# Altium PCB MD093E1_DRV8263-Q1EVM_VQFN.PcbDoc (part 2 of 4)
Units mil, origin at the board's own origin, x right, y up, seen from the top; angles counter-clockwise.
Board outline 3224.41 x 4078.74 mil, 4 copper layers (Top Layer, Signal Layer 1, Signal Layer 2, Bottom Layer), stack 61.2 mil thick; 228 components, 126 nets, 641 pads, 753 vias.
Unrouted connection lines stored in the file: 76.

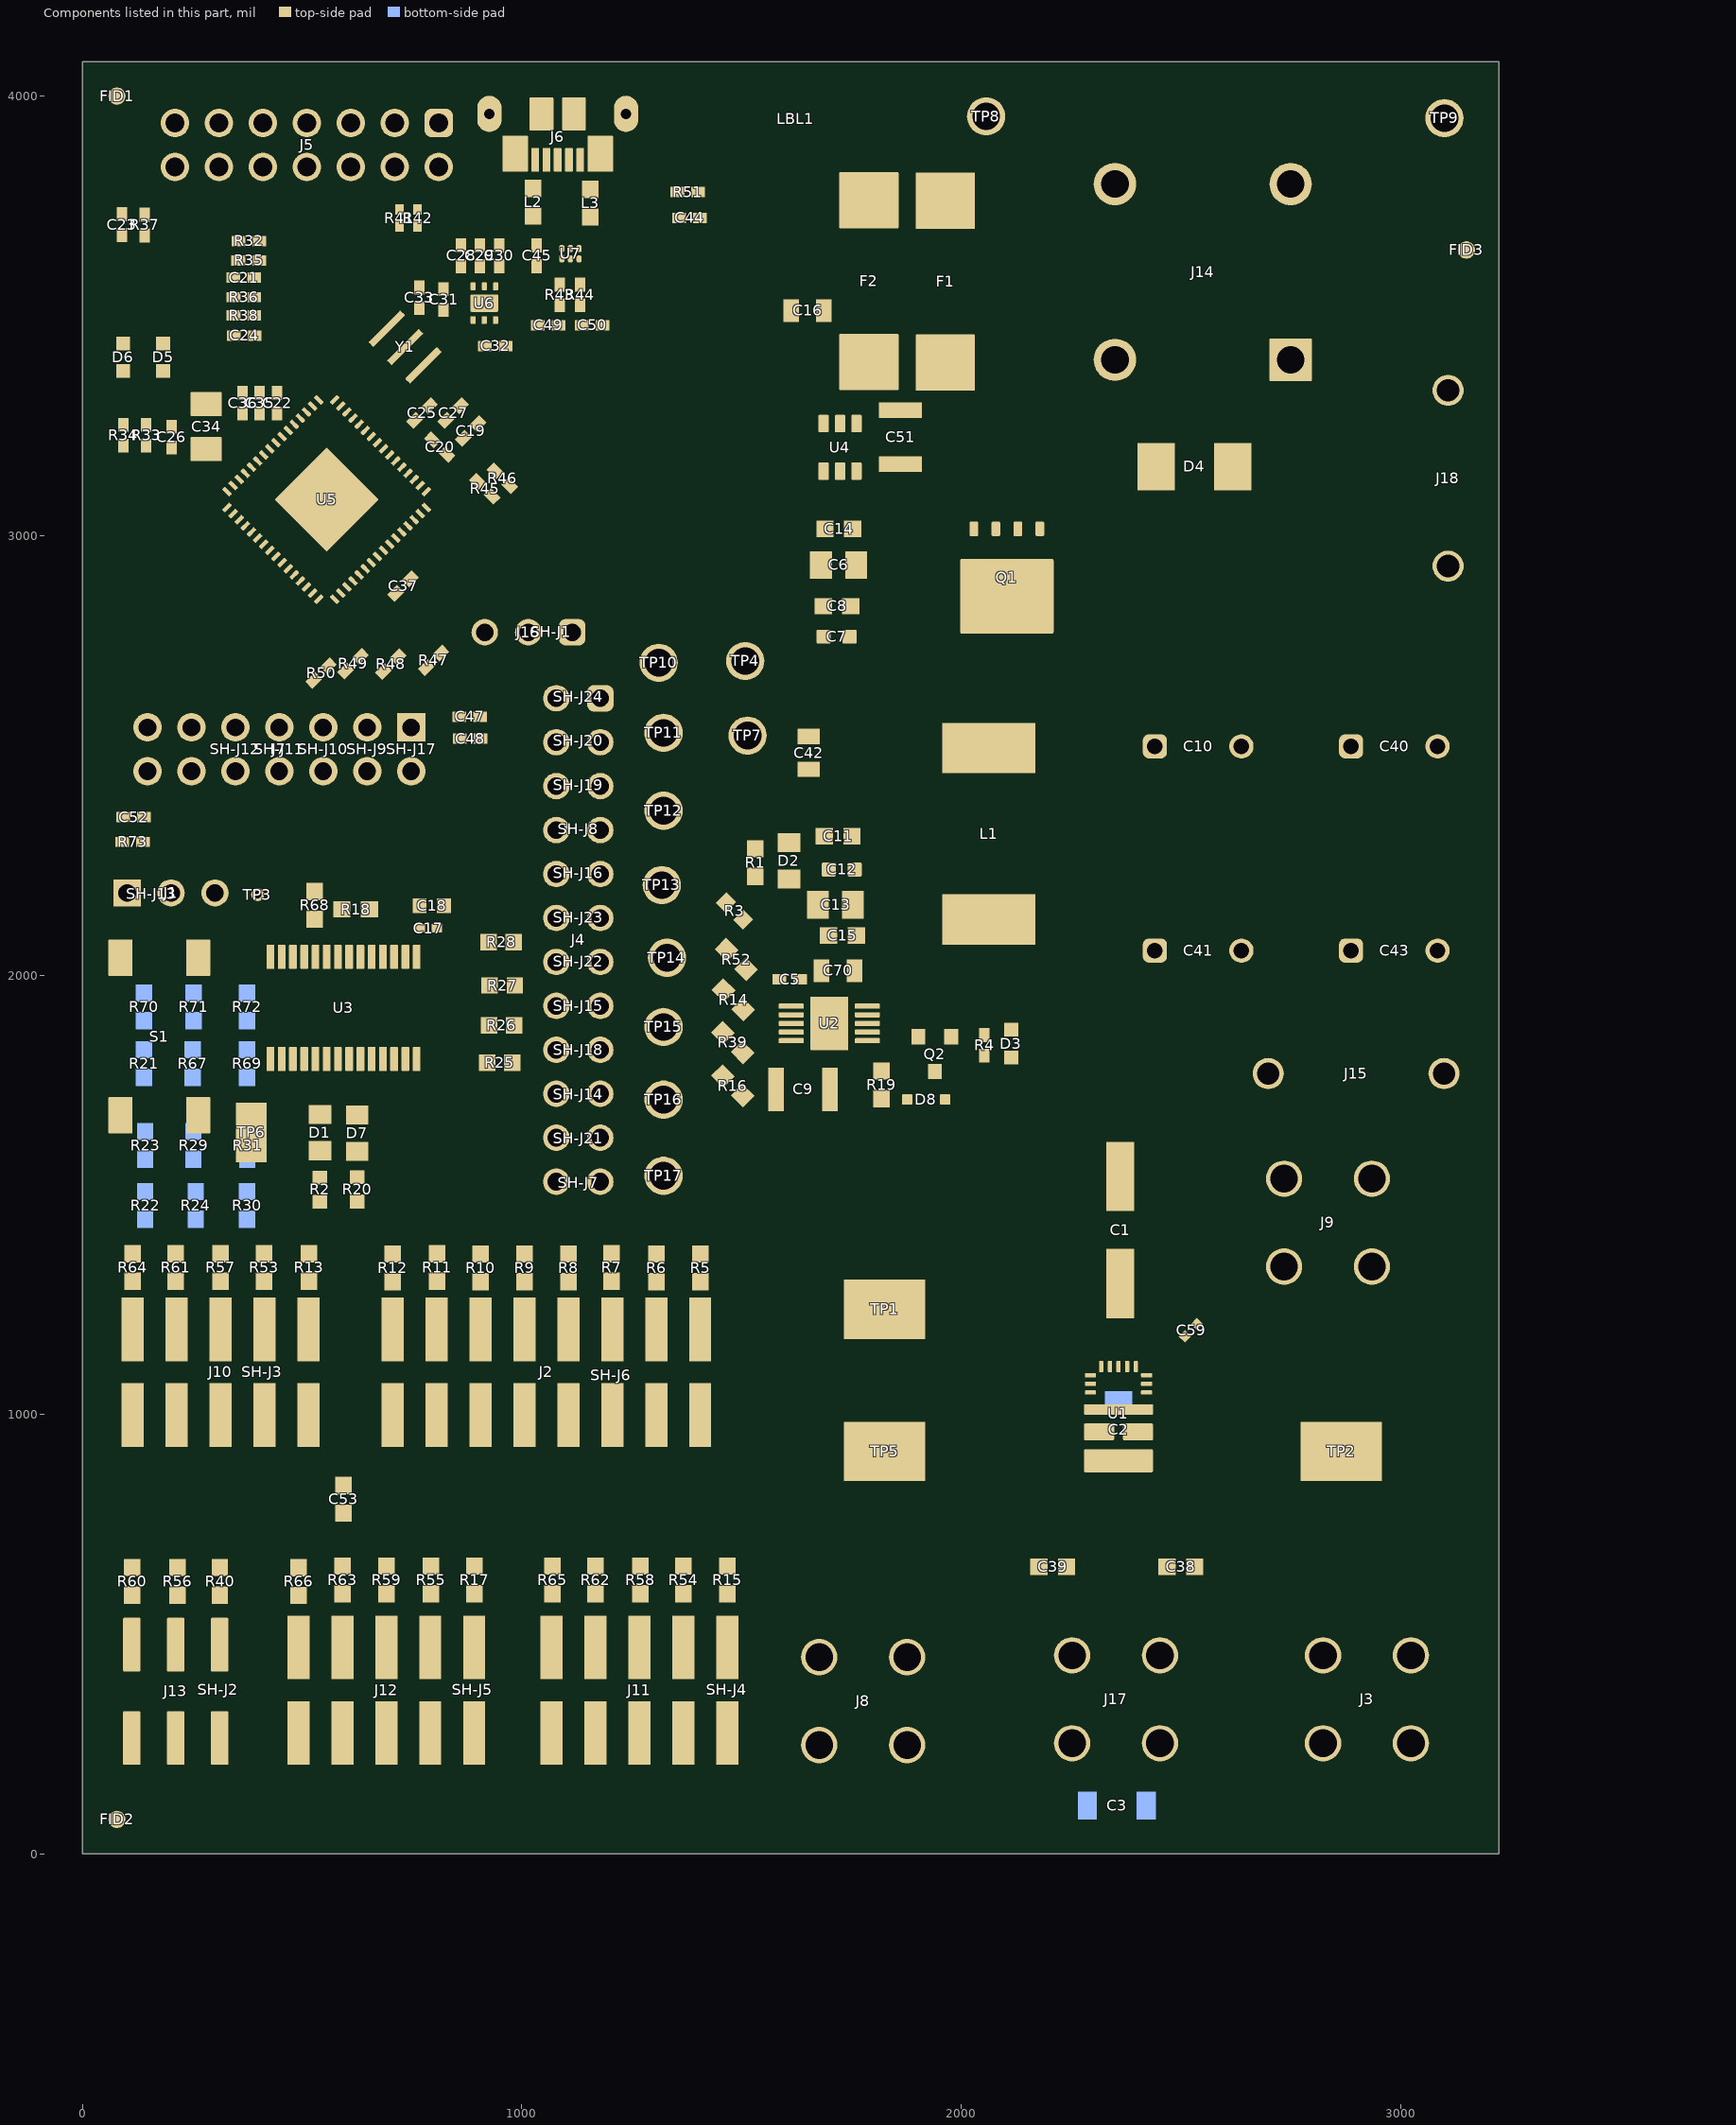
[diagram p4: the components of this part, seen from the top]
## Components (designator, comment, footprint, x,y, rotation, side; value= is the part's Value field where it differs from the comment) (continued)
C10 "860040875004" WCAP-ATUL_D10H20 2539.51,2520.41 r180 top
C11 "885012206114" 0603 1720.21,2315.81 r0 top value=0.01uF
C12 "885012206120" FP-885012206120_0603-MFG 1728.36,2240.08 r0 top value=100nF
C13 "C2012X7S2A105K125AB" 0805_HV 1713.9,2160.08 r0 top value=1uF
C14 "06031C102KAT2A" 0603 1721.82,3015.01 r180 top value=1000pF
C15 "06031C102KAT2A" 0603 1730,2090 r180 top value=1000pF
C16 "885012207124" WCAP-CSGP_0805_L2W1.25H0.8_Reflow 1650.4,3512 r180 top
C17 "Capacitor" 0402_065L 787.4,2106.3 r0 top value=4.7uF
C18 "885012206020" 0603L 795.28,2157.48 r0 top value=0.1uF
C19 "C1005X5R1A475M050BC" 0402 884.15,3238.01 r45 top value=4.7uF
C20 "GRM155R61A104KA01D" 0402 813.3,3201.7 r315 top value=0.1uF
C21 "C1005C0G1H330J050BA" 0402 367.6,3586.85 r180 top value=33pF
C22 "GRM155R61A104KA01D" 0402 443.31,3301.13 r90 top value=0.1uF
C23 "GRM155R71H102KA01D" 0402 90,3707.62 r270 top value=1000pF
C24 "C1005C0G1H330J050BA" 0402 368.6,3454.9 r180 top value=33pF
C25 "GRM155R61A224KE19D" 0402 773.36,3279.06 r45 top value=0.22uF
C26 "GRM155R61C474KE01" 0402 203.16,3224.35 r90 top value=0.47uF
C27 "GRM155R61A224KE19D" 0402 844.2,3279.06 r45 top value=0.22uF
C28 "885012105012" 0402 861.87,3636.71 r90 top value=1uF
C29 "GRM155R61A104KA01D" 0402 904.31,3636.73 r90 top value=0.1uF
C30 "GRM155R71C103KA01D" 0402 948.35,3636.71 r90 top value=0.01uF
C31 "2.2uF" 0402 822,3537 r90 top
C32 "GRM155R71C103KA01D" 0402 939.95,3431.27 r0 top value=0.01uF
C33 "885012105012" 0402 767,3541 r90 top value=1uF
C34 "T520A106M010ATE080" 3216-18 281.9,3247.97 r90 top value=10uF
C35 "GRM155R61A104KA01D" 0402 403.55,3301.13 r90 top value=0.1uF
C36 "GRM155R61A104KA01D" 0402 364.77,3301.13 r90 top value=0.1uF
C37 "GRM155R61A104KA01D" 0402 729.94,2885.18 r225 top value=0.1uF
C38 "CGA3E2X7R2A102K080AA" 0603 2500,653.54 r0 top value=1000pF
C39 "CGA3E2X7R2A102K080AA" 0603 2208.66,653.54 r180 top value=1000pF
C40 "860040875004" WCAP-ATUL_D10H20 2985.96,2520.41 r180 top
C41 "860040875004" WCAP-ATUL_D10H20 2539.51,2055.76 r180 top
C42 "885382207009" WCAP-CSST_0805_L2W1.25H1.25 1653,2505.6 r90 top
C43 "860040875004" WCAP-ATUL_D10H20 2985.96,2055.76 r180 top
C44 "GRM155R61A224KE19D" 0402 1381.91,3722.82 r0 top value=0.22uF
C45 "GRM155R61A104KA01D" 0402 1034.23,3636.73 r90 top value=0.1uF
C47 "GRM1555C1H100FA01D" 0402 881.38,2588 r180 top value=10pF
C48 "GRM1555C1H100FA01D" 0402 882.62,2538 r180 top value=10pF
C49 "GRM1555C1H100FA01D" 0402 1060.06,3478.58 r180 top value=10pF
C50 "GRM1555C1H100FA01D" 0402 1160,3478.58 r0 top value=10pF
C51 "885382209002" WCAP-CSST_1210_L3.2W2.5H2.5 1862,3224.02 r270 top
C52 "GRM155R71H102KA01D" 0402 116.62,2359 r0 top value=1000pF
C53 "CGA3E2X7R1H104K080AA" 0603 594.49,807.09 r270 top value=0.1uF
C59 "885012105001" WCAP-CSGP_0402_L1W0.5H0.5 2523,1192 r45 top
C70 "885012207128" WCAP-CSGP_0805_L2W1.25H1.25 1720,2010 r180 top
D1 "150080VS75000" WL-SMCW_0805_150080xx75000 540.94,1641.73 r90 top
D2 "150080SS75000" WL-SMCW_0805_150080xx75000 1608.19,2260.03 r90 top
D3 "150060VS75000" WL-SMCW_GREEN 2114,1844 r90 top value=Green
D4 "SMBJ33CA-13-F" SMB-Bi 2530.99,3156.95 r180 top value=33V
D5 "150060RS75000" WL-SMCW_RED 183.95,3405.78 r270 top value=Red
D6 "CMP-0002894-2" WL-SMCW_GREEN 93.28,3405.78 r270 top value=Green
D7 "150080VS75000" WL-SMCW_0805_150080xx75000 625.43,1640.3 r90 top
D8 "BZX84J-B4V7,115" FP-BZX84J-B4V7,115_SC90-MFG 1920.31,1717 r180 top
F1 "0463030.ER" Fuse_0463 1964,3577.95 r90 top
F2 "0463030.ER" Fuse_0463 1790,3578.95 r90 top
FID1 "Fiducial" Fiducial10-20 78.74,4000 r0 top
FID2 "Fiducial" Fiducial10-20 78.74,78.74 r90 top
FID3 "Fiducial" Fiducial10-20 3150,3650 r0 top
J1 "PR20203VBNN" FP-PR20203VBNN-MFG 202,2187 r0 top
J2 "TSM-108-01-L-DV" Samtec_TSM-108-01-x-DV 1056.38,1096.5 r270 top
J3 "CT3151SP-2" CTE_CT3151SP-2 2923.62,-492.03 r90 top
J4 "67997-224HLF" FCI_67997-224HLF 1128.74,2079.92 r270 top locked
J5 "61301421121" Wurth_61301421121 511.02,3888.87 r270 top
J6 "CMP-0055311-1" Molex_1051640001 1081.95,4016.64 r180 top
J7 "PEC07DAAN" CONN_PEC07DAAN 448.4,2513.8 r180 top
J8 "CT3151SP-2" CTE_CT3151SP-2 1777.17,-495.97 r90 top
J9 "CT3151SP-2" CTE_CT3151SP-2 3679,1436.74 r180 top
J10 "TSM-105-01-L-DV-P" Samtec_TSM-105-01-x-DV 314.57,1096.5 r270 top
J11 "TSM-105-01-L-DV-P" Samtec_TSM-105-01-x-DV 1267.87,372.64 r270 top
J12 "TSM-105-01-L-DV-P" Samtec_TSM-105-01-x-DV 691.99,372.64 r270 top
J13 "61000621121" Wurth_61000621121 212.6,370.08 r270 top
J14 "691256610002" FP-691256610002_HDR2-MFG 2550,3697.25 r180 top
J15 "D3082-05" Harwin_D3082-05 2899,1776 r180 top
J16 "TSW-103-08-G-S" Samtec_TSW-103-08-x-S 1015,2780 r180 top
J17 "CT3151SP-0" CTE_CT3151SP-0 2352.76,-492.03 r90 top
J18 "D3082-05" Harwin_D3082-05 3108.29,3130.56 r90 top
L1 "7443320100" WE-HCC_1210 2063.14,2321.4 r270 top value=1uH
L2 "BLM18AG151BH1D" 0603 1026,3758.5 r270 top value="150 ohm"
L3 "BLM18AG151BH1D" 0603 1156,3756.5 r270 top value="150 ohm"
LBL1 "THT-14-423-10" Label_650x200 1623,3948 r0 top
Logo1 "CE Mark" CE_Mark_5mm 1592,3556 r180 bottom
Logo2 "Texas Instruments" TI_Symbol_Overlay_Small 249.51,2792.02 r0 top
Logo3 "FCC disclaimer" FCC_disclaimer -3000,2700 r270 bottom
Logo4 "WEEE logo" WEEE_Minimum 169.29,2893.7 r180 bottom
Logo5 "CAUTION.  READ USER GUIDE BEFORE USE" IEC_Caution_Small 2282.71,1759.82 r0 top
LOGO6 "CAUTION HOT SURFACE" IEC_HotSurface_Small 2589,975 r0 top
LOGO7 "CAUTION HOT SURFACE" IEC_HotSurface_Small 2142.87,974.79 r180 bottom
MP1 "RBS-37BK" FP-RBS-37BK_BUMPER_CYLI-MFG 2845.34,893.45 r180 bottom
MP2 "RBS-37BK" FP-RBS-37BK_BUMPER_CYLI-MFG 379.67,389.06 r180 bottom
MP3 "RBS-37BK" FP-RBS-37BK_BUMPER_CYLI-MFG 2677.17,2952.76 r180 bottom
MP4 "RBS-37BK" FP-RBS-37BK_BUMPER_CYLI-MFG 423.03,3391.92 r180 bottom
Q1 "CSD19502Q5B" DNK0008A 2104.16,2904.47 r270 top value=80V
Q2 "BC846BLT1G" ONSC-SOT-23-3-318-08_V 1940,1820 r270 top
R1 "RNCF0603TKY10K0" 0603 1531.5,2255.91 r90 top value=10.0k
R2 "CMP-0025785-4" 0603L 540.94,1511.81 r90 top value=330
R3 "CMP-0025785-4" 0603L 1484.25,2145.67 r315 top value=330
R4 "CRCW040247K0JNED" 0402 2053,1840 r90 top value=47k
R5 "RC0603FR-07470RL" 0603 1406.38,1333.94 r270 top value=470
R6 "RC0603FR-07680RL" 0603 1306.38,1333.94 r270 top value=680
R7 "RC0603FR-071KL" 0603 1204.72,1334.65 r270 top value=1.00k
R8 "RC0603FR-071K5L" 0603 1106.38,1333.94 r270 top value=1.50k
R9 "RC0603FR-072K2L" 0603 1006.38,1333.94 r270 top value=2.20k
R10 "RC0603FR-073K3L" 0603 906.38,1333.94 r270 top value=3.30k
R11 "RC0603FR-074K7L" 0603 807.09,1334.65 r270 top value=4.70k
R12 "RC0603FR-076K8L" 0603 706.38,1333.94 r270 top value=6.80k
R13 "PMR03EZPJ000" 0603 515.75,1334.65 r90 top value=0
R14 "PMR03EZPJ000" 0603 1481.67,1943.53 r135 top value=0
R15 "PMR03EZPJ000" 0603 1467.87,623.86 r90 top value=0
R16 "PMR03EZPJ000" 0603 1480.32,1748.03 r135 top value=0
R17 "PMR03EZPJ000" 0603 891.99,623.86 r90 top value=0
R18 "RC0603JR-0747KL" 0603 622.05,2149.61 r180 top value=47k
R19 "RC0603FR-07470RL" 0603 1819,1750 r90 top value=470
R20 "CMP-0025785-4" 0603L 625.43,1512.35 r90 top value=330
R21 "RC0603JR-0710KL" 0603 140,1798.5 r90 bottom value=10k
R22 "RC0603JR-0710KL" 0603 143,1476 r90 bottom value=10k
R23 "RC0603JR-0710KL" 0603 143,1612.69 r90 bottom value=10k
R24 "RC0603JR-0710KL" 0603 258.09,1476 r90 bottom value=10k
R25 "CRCW06030000Z0EAHP" RESC1609X55X30NL10T20 949.72,1800.27 r180 top value=0
R26 "CRCW06030000Z0EAHP" RESC1609X55X30NL10T20 954.11,1885.29 r180 top value=0
R27 "CRCW06030000Z0EAHP" RESC1609X55X30NL10T20 955.71,1976.38 r180 top value=0
R28 "CRCW06030000Z0EAHP" RESC1609X55X30NL10T20 953.34,2075.24 r180 top value=0
R29 "RC0603JR-0710KL" 0603 252.79,1612.69 r90 bottom value=10k
R30 "RC0603JR-0710KL" 0603 374.89,1476 r90 bottom value=10k
R31 "RC0603JR-0710KL" 0603 375.38,1612.69 r90 bottom value=10k
R32 "CRCW0402240KFKED" 0402 379.06,3670.49 r180 top value=240k
R33 "CRCW0402470RJNED" 0402 145.25,3228.61 r270 top value=470
R34 "CRCW0402390RJNED" 0402 93.28,3228.61 r270 top value=390
R35 "CRCW0402150KFKED" 0402 378.6,3625.98 r0 top value=150k
R36 "RC0402FR-07220KL" 0402 367.72,3542.49 r180 top value=220k
R37 "CRCW040247K0JNED" 0402 141.47,3706.64 r270 top value=47k
R38 "RC0402FR-07220KL" 0402 367.72,3500.73 r0 top value=220k
R39 "PMR03EZPJ000" 0603 1480.31,1846.46 r135 top value=0
R40 "PMR03EZPJ000" 0603 313.01,620.5 r90 top value=0
R41 "ERJ-2GE0R00X" 0402L 721.47,3722.65 r90 top value=0
R42 "ERJ-2GE0R00X" 0402L 762.86,3722.65 r90 top value=0
R43 "CRCW040227R0JNED" 0402 1086.38,3547.48 r270 top value=27
R44 "CRCW040227R0JNED" 0402 1132.41,3547.48 r270 top value=27
R45 "CRCW04021K40FKED" 0402 915.7,3106.3 r315 top value=1.40k
R46 "CRCW04021M00JNED" 0402 955.7,3130.3 r135 top value=1.0Meg
R47 "CRCW040210R0FKED" 0402 799.3,2716.3 r225 top value=10.0
R48 "CRCW040210R0FKED" 0402 702.3,2707.3 r225 top value=10.0
R49 "CRCW040210R0FKED" 0402 616.3,2708.3 r225 top value=10.0
R50 "CRCW040210R0FKED" 0402 543.3,2687.3 r225 top value=10.0
R51 "CRCW040233K0JNED" 0402 1377.97,3781.88 r180 top value=33k
R52 "PMR03EZPJ000" 0603 1488.19,2035.43 r135 top value=0
R53 "CRCW06038K20JNEA" 0603 413.39,1334.65 r270 top value=8.2k
R54 "CRCW06038K20JNEA" 0603 1367.87,623.86 r270 top value=8.2k
R55 "CRCW06038K20JNEA" 0603 793.2,623.86 r270 top value=8.2k
R56 "CRCW06038K20JNEA" 0603 216.58,620.5 r270 top value=8.2k
R57 "CRCW060322K0JNEA" 0603 314.96,1334.65 r270 top value=22k
R58 "CRCW060322K0JNEA" 0603 1270.29,623.86 r270 top value=22k
R59 "CRCW060322K0JNEA" 0603 691.99,623.86 r270 top value=22k
R60 "CRCW060382K0JNEA" 0603 113.01,620.5 r90 top value=82k
R61 "CRCW060347K0FKEA" 0603 212.6,1334.65 r270 top value=47.0k
R62 "CRCW060347K0FKEA" 0603 1167.87,623.86 r270 top value=47.0k
R63 "CRCW060347K0FKEA" 0603 591.99,623.86 r270 top value=47.0k
R64 "CRCW0603100KDHEAP" 0603 114.17,1334.65 r270 top value=100k
R65 "CRCW0603100KDHEAP" 0603 1069.92,623.86 r270 top value=100k
R66 "CRCW0603100KDHEAP" 0603 491.99,620.12 r270 top value=100k
R67 "RC0603JR-0710KL" 0603 251,1798.5 r90 bottom value=10k
R68 "RC0603JR-0710KL" 0603 529,2158.5 r270 top value=10k
R69 "RC0603JR-0710KL" 0603 374.65,1798.5 r90 bottom value=10k
R70 "RC0603JR-0710KL" 0603 140,1927.5 r90 bottom value=10k
R71 "RC0603JR-0710KL" 0603 253,1927.5 r90 bottom value=10k
R72 "RC0603JR-0710KL" 0603 374.65,1927.5 r90 bottom value=10k
R73 "CRCW040247K0JNED" 0402 114.62,2303 r0 top value=47k
S1 "FSM4JSMA" SW_FSM4JSMA 175.2,1860.24 r0 top
SH-J1 "60900213421" Wurth_60900213421 1066.69,2780.75 r180 top
SH-J2 "60900213421" Wurth_60900213421 309.34,374.33 r270 top
SH-J3 "60900213421" Wurth_60900213421 408.98,1097.11 r270 top
SH-J4 "60900213421" Wurth_60900213421 1467.17,374.33 r270 top
SH-J5 "60900213421" Wurth_60900213421 887.75,374.33 r270 top
SH-J6 "60900213421" Wurth_60900213421 1203.05,1088.88 r90 top
SH-J7 "60900213421" Wurth_60900213421 1128.96,1527.56 r180 top
SH-J8 "60900213421" Wurth_60900213421 1128.96,2332.08 r180 top
SH-J9 "60900213421" Wurth_60900213421 648.56,2514.41 r90 top
SH-J10 "60900213421" Wurth_60900213421 548.38,2514.41 r90 top
SH-J11 "60900213421" Wurth_60900213421 448.19,2514.41 r90 top
SH-J12 "60900213421" Wurth_60900213421 348,2514.41 r90 top
SH-J13 "60900213421" Wurth_60900213421 157.53,2185.12 r0 top
SH-J14 "60900213421" Wurth_60900213421 1128.96,1728.69 r180 top
SH-J15 "60900213421" Wurth_60900213421 1128.96,1929.82 r180 top
SH-J16 "60900213421" Wurth_60900213421 1128.96,2231.51 r180 top
SH-J17 "60900213421" Wurth_60900213421 748.75,2514.41 r90 top
SH-J18 "60900213421" Wurth_60900213421 1128.96,1829.25 r180 top
SH-J19 "60900213421" Wurth_60900213421 1128.96,2432.64 r180 top
SH-J20 "60900213421" Wurth_60900213421 1128.96,2533.2 r180 top
SH-J21 "60900213421" Wurth_60900213421 1128.96,1628.12 r180 top
SH-J22 "60900213421" Wurth_60900213421 1128.96,2030.38 r180 top
SH-J23 "60900213421" Wurth_60900213421 1128.96,2130.95 r180 top
SH-J24 "60900213421" Wurth_60900213421 1128.96,2633.77 r180 top
TP1 "5016" Testpoint_Keystone_Compact 1826.1,1239.63 r180 top
TP2 "5016" Testpoint_Keystone_Compact 2865.61,915.83 r180 top
TP3 "TP_H0.45P0.75" TP_H045P075 399,2183 r90 top
TP4 "5010" Keystone5010 1508.68,2714.6 r0 top
TP5 "5016" Testpoint_Keystone_Compact 1826.1,915.83 r180 top
TP6 "5015" Testpoint_Keystone_Miniature 385,1642 r90 top
TP7 "5010" Keystone5010 1514,2545 r0 top
TP8 "5010" Keystone5010 2057,3954 r180 top
TP9 "5011" Keystone5011 3100,3950 r0 top
TP10 "5010" Keystone5010 1311.83,2710.66 r0 top
TP11 "5010" Keystone5010 1322.83,2551.18 r0 top
TP12 "5010" Keystone5010 1322.83,2374.02 r0 top
TP13 "5010" Keystone5010 1318.9,2204.72 r0 top
TP14 "5010" Keystone5010 1330.71,2039.37 r0 top
TP15 "5010" Keystone5010 1322.83,1881.89 r0 top
TP16 "5010" Keystone5010 1322.83,1716.54 r0 top
TP17 "5010" Keystone5010 1322.83,1543.31 r0 top
U1 "DRV8263SQVAKRQ1" VAK0015A-MFG 2358.27,996.06 r0 top
U2 "TPS7A4333DGQ" DGQ0010E-MFG 1700,1890 r0 top
U3 "MSP430G2553IPW28R" PW0028A_N 594.49,1925.2 r270 top
U4 "LM74700QDBVTQ1" DBV0006A_N 1724.41,3200.79 r270 top
U5 "CMP-0039269-4" RGC0064B 556.18,3082.03 r315 top
U6 "TPS73533DRVR" DRV0006A 914.81,3528.82 r90 top
U7 "TPD2E001DRYR" DRY0006A 1110.93,3641.35 r90 top
Y1 "CSTNR4M00GH5L000R0" MuRata_CSTNR 734.65,3429.07 r135 top
ZZ1 "This Assembly Note is for PCB labels only" AssemblyNoteLabel 173.67,4752.96 r0 top
ZZ2 "These assemblies are ESD sensitive, ESD precautions shall be observed." AssemblyNote 173.67,4644.07 r0 top
ZZ3 "These assemblies must be clean and free from flux and all contaminants. Use of no clean flux is not acceptable." AssemblyNote 173.67,4555.52 r0 top
ZZ4 "These assemblies must comply with workmanship standards IPC-A-610 Class 2, unless otherwise specified." AssemblyNote 173.67,4466.96 r0 top

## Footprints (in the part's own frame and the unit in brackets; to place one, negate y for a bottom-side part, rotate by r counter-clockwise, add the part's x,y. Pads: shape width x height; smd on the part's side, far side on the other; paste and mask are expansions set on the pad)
0402 [mm] "0402 from SM-752 data"
  rect 0.8x0.6 smd: 1(-0.6,0) 2(0.6,0)
  silkscreen extent -1.22,-0.52 1.22,0.52, body extent -0.55,-0.3 0.55,0.3, height 0.6
0402_065L [mm] "0402"
  rect 0.6x0.5 smd: 1(-0.5,0) 2(0.5,0)
  body extent -0.55,-0.3 0.55,0.3, height 0.65
0402L [mm] "0402 from SM-752 data"
  rect 0.6x0.5 smd: 1(-0.5,0) 2(0.5,0)
  body extent -0.55,-0.3 0.55,0.3, height 0.6
0603 [mm] "0603 from SM-752 data"
  rect 1x0.95 smd: 1(-0.8,0) 2(0.8,0)
  silkscreen extent -1.52,-0.69 1.52,0.69, body extent -0.87,-0.47 0.87,0.47, height 1
0603L [mm] "0603 from SM-752 data"
  rect 0.8x0.85 smd: 1(-0.7,0) 2(0.7,0)
  silkscreen extent -0.07,-0.33 0.07,0.33, body extent -0.87,-0.47 0.87,0.47, height 1
0805_HV [mil] "0805 with 30mil clearance between pads"
  rect 50x63 smd: 1(-40,0) 2(40,0)
  silkscreen extent -74,-40 74,40, body extent -43,-29 43,29, height 57
1206_180 [mm] "1206_180"
  rect 1.1x1.6 smd: 1(-1.7,0) 2(1.7,0)
  silkscreen extent -0.9,-1 0.9,1, body extent -1.75,-0.95 1.75,0.95, height 1.8
3216-18 [mm] "Based on AVX recommendation in http://www.avx.com/download/software/literature/AVX-Footprint-Library.pdf"
  rrect7% 1.4x1.8 smd: 1(-1.3,0) 2(1.3,0)
  silkscreen extent -1.9,-1.13 0.8,1.12, body extent -1.7,-0.9 1.7,0.9, height 1.82
AssemblyNote [mil] "Assembly Note"
AssemblyNoteLabel [mil] "Assembly Note for PCB Labels"
CE_Mark_5mm [mil] "Minimum text height for CE Mark"
  silkscreen extent -138,-98 138,98
CONN_PEC07DAAN [mil] "SULLINS"
  rect 64.96x64.96 hole 40 mask+0: 1(-300,-50)
  round 64.96 hole 40 mask+0: 2(-300,50) 3(-200,-50) 4(-200,50) 5(-100,-50) 6(-100,50) 7(0,-50) 8(0,50) 9(100,-50) 10(100,50) 11(200,-50) 12(200,50) 13(300,-50) 14(300,50)
  silkscreen extent -373,-126 350,100, body extent -352,-103 352,103, height 330
CTE_CT3151SP-0 [mm] "Banana Jack Insul Nylon Black, R/A, TH"
  round 2.1 hole 1.6: 1(18.898,-2.54) 1(18.898,2.54) 1(23.978,-2.54) 1(23.978,2.54)
  silkscreen extent 0.44,-6.75 18.02,6.75, body extent -3.06,-6.7 24.64,6.8, height 14.37
CTE_CT3151SP-2 [mm] "Banana Jack Insul Nylon Red, R/A, TH"
  round 2.1 hole 1.6: 1(18.898,-2.54) 1(18.898,2.54) 1(23.978,-2.54) 1(23.978,2.54)
  silkscreen extent 0.44,-6.75 18.02,6.75, body extent -3.06,-6.75 24.64,6.75, height 14.37
DBV0006A_N [mm] "SOT23, 6-Leads, Body 2.9x1.6mm, Pitch 0.95mm, Lead Span 2.8mm, IPC Medium Density"
  rrect17% 1x0.6 smd: 1(-1.375,0.95) 2(-1.375,0) 3(-1.375,-0.95) 4(1.375,-0.95) 5(1.375,0) 6(1.375,0.95)
  silkscreen extent -1.68,-1.55 0.5,1.55, body extent -1.42,-1.46 1.42,1.46, height 1.12
DGQ0010E-MFG [mm]
  rrect33% 1.45x0.3 smd paste+0 mask+0: 1(-2.2,1) 2(-2.2,0.5) 3(-2.2,0) 4(-2.2,-0.5) 5(-2.2,-1) 6(2.2,-1) 7(2.2,-0.5) 8(2.2,0) 9(2.2,0.5) 10(2.2,1)
  rrect5% 2.2x3.1 smd paste-1000 mask-1000: 11(0,0)
  silkscreen extent -3.6,-1.65 1.65,1.65, body extent -3.03,-1.8 3.03,1.8, height 0.25
DNK0008A [mm] "SON, 8-Leads, Body 5x6mm"
  rrect39% 0.86x0.51 smd paste-0.05 mask-0.05: 1(-2.82,1.905) 2(-2.82,0.635) 3(-2.82,-0.635) 4(-2.82,-1.905) 5(2.82,-1.905) 6(2.82,-0.635) 7(2.82,0.635) 8(2.82,1.905)
  rrect40% 0.25x0.555 on Top Solder: 9(-0.83,2.372) 9(-0.83,-2.372)
  rrect40% 0.25x0.555 on Top Paste: 9(-0.83,2.372) 9(-0.83,-2.372)
  rrect11% 0.95x1.13 on Top Paste: 9(-0.535,1.33) 9(-0.535,0) 9(-0.535,-1.33) 9(0.615,1.33) 9(0.615,0) 9(0.615,-1.33) 9(1.765,1.33) 9(1.765,-1.33) 9(1.765,0)
  rrect3% 3.58x4 on Top Solder: 9(0.75,0)
  rrect5% 4.34x5.4 smd paste-3 mask-3: 9(1.08,0)
  body extent -3.05,-2.55 3.05,2.55, height 1.06
DRV0006A [mm] "SON, 6-Leads, Body 2x2mm, Pitch 0.65mm, Thermal Pad 1.6x1mm, TI Recommended"
  rrect33% 0.45x0.3 smd: 1(-0.975,0.65) 2(-0.975,0) 3(-0.975,-0.65) 4(0.975,-0.65) 5(0.975,0) 6(0.975,0.65)
  rrect14% 1x0.7 on Top Paste: 7(0,0.45) 7(0,-0.45)
  rrect10% 1x1.6 smd paste-0.5: 7(0,0)
  silkscreen extent -1.05,-1.2 1.05,1.2, body extent -1.05,-1.05 1.05,1.05, height 0.81
DRY0006A [mm] "USON-6"
  rrect67% 0.45x0.3 smd paste-0.05 mask-0.05: 1(-0.275,0.5)
  rrect67% 0.4x0.3 smd paste-0.05 mask-0.05: 2(-0.3,0) 3(-0.3,-0.5) 4(0.3,-0.5) 5(0.3,0) 6(0.3,0.5)
  body extent -0.5,-0.72 0.5,0.73, height 0.58
FCC_disclaimer [mil]
FCI_67997-224HLF [mm] "Header, 2.54mm, 12x2, TH"
  rrect50% 1.53x1.53 hole 1.02: 1(-13.97,1.27)
  round 1.53 hole 1.02: 2(-13.97,-1.27) 3(-11.43,1.27) 4(-11.43,-1.27) 5(-8.89,1.27) 6(-8.89,-1.27) 7(-6.35,1.27) 8(-6.35,-1.27) 9(-3.81,1.27) 10(-3.81,-1.27) 11(-1.27,1.27) 12(-1.27,-1.27) 13(1.27,1.27) 14(1.27,-1.27) 15(3.81,1.27) 16(3.81,-1.27) 17(6.35,1.27) 18(6.35,-1.27) 19(8.89,1.27) 20(8.89,-1.27) 21(11.43,1.27) 22(11.43,-1.27) 23(13.97,1.27) 24(13.97,-1.27)
  body extent -15.24,-2.42 15.24,2.42, height 8.71
Fiducial10-20 [mm]
  round 1 smd mask+0.5: 1(0,0)
  Top Layer keep-out circle w1.178: c0,0 r0.5
FP-691256610002_HDR2-MFG [mm]
  rrect4% 2.45x2.45 hole 1.6 paste-2539.97 mask+0: 1(-5.08,7.55)
  round 2.45 hole 1.6 paste-2539.97 mask+0: 1(-5.08,-2.61) 2(5.08,7.55) 2(5.08,-2.61)
  silkscreen extent -11,-9.2 10.21,9.2, body extent -10.31,-9.3 10.31,9.3, height 0.25
FP-885012206120_0603-MFG [mm]
  rrect13% 0.8x0.8 smd paste+0 mask+0: 1(-0.75,0) 2(0.75,0)
  silkscreen extent -0.85,-0.77 0.85,0.78, body extent -1.25,-0.55 1.25,0.55, height 0.25
FP-BZX84J-B4V7,115_SC90-MFG [mm]
  rrect17% 0.6x0.6 smd paste-1000 mask+0: 1(-1.1,0) 2(1.1,0)
  silkscreen extent -2.08,-0.67 0.42,0.67, body extent -1.53,-0.82 1.52,0.82, height 0.25
FP-PR20203VBNN-MFG [mm]
  rect 1.57x1.57 hole 1.02 paste-2539.97 mask+0: 1(-2.54,0)
  round 1.57 hole 1.02 paste-2539.97 mask+0: 2(0,0) 3(2.54,0)
  silkscreen extent -3.86,-1.83 3.81,1.25, body extent -3.91,-1.35 3.91,1.35, height 0.25
FP-RBS-37BK_BUMPER_CYLI-MFG [mil]
  silkscreen extent -370,-370 370,370, body extent -360,-360 360,360, height 579
Fuse_0463 [mm] "SMD, 2-Leads, Body 10.1x3.12mm"
  rrect3% 3.25x3.43 smd: 1(-4.675,0) 2(4.675,0)
  silkscreen extent -2.6,-1.5 2.6,1.5, body extent -5.05,-1.56 5.05,1.56, height 3.12
Harwin_D3082-05 [mm] "Shorting Plug, 10.16mm spacing, TH"
  round 1.8 hole 1.3: 1(-5.08,0) 2(5.08,0)
  silkscreen extent -3.9,-0.53 3.9,0.53, body extent -5.6,-0.52 5.61,0.52, height 6.63
IEC_Caution_Small [mil]
  silkscreen extent -107,-93 107,92
IEC_HotSurface_Small [mil]
  silkscreen extent -107,-93 107,92
Keystone5010 [mil] "Keystone Multipurpose loops"
  round 87 hole 63: 1(0,0)
  silkscreen extent -70,-70 70,70, body extent -63,-63 63,62, height 319
Keystone5011 [mil] "Keystone Multipurpose loops"
  round 87 hole 63: 1(0,0)
  silkscreen extent -70,-70 70,70, body extent -63,-63 63,62, height 319
Label_650x200 [mil] "Thermal Transfer Label"
  round 1 on Mech13: 0(0,0)
  silkscreen extent -325,-100 325,100, body extent -325,-100 325,100, height 1
Molex_1051640001 [mm] "Receptacle, USB 2.0, Micro B, 5 Pos, 0.65mm Pitch, R/A, SMT"
  rrect22% 0.45x1.38 smd: 1(1.3,4.11) 2(0.65,4.11) 3(0,4.11) 4(-0.65,4.11) 5(-1.3,4.11)
  rrect7% 1.475x2.1 smd: 6(-2.462,3.75) 11(2.462,3.75)
  rrect100% 1.4x2.1 hole 0.6 slot 1.3 at 90 deg: 7(-3.95,1.45) 10(3.95,1.45)
  rrect7% 1.375x1.9 smd: 8(-0.938,1.45) 9(0.938,1.45)
  silkscreen extent 1.2,5.1 1.4,5.4, body extent -4.1,-0.7 4.1,4.47, height 2.45
MuRata_CSTNR [mm] "SMD, 3-Leads, Body 4.5x2mm, Pitch 1.5mm"
  rrect25% 0.4x2.6 smd: 1(-1.5,0) 2(0,0) 3(1.5,0)
  body extent -2.3,-1.05 2.3,1.05, height 1.2
ONSC-SOT-23-3-318-08_V [mm] "SOT23, 3-Leads, Body 2.92x1.3mm, Pitch 0.95mm"
  rect 0.9x0.8 smd: 1(-1,0.95) 2(-1,-0.95) 3(1,0)
  silkscreen extent -1.95,-1.46 0.65,1.6, body extent -0.65,-1.46 0.65,1.46, height 1.11
PW0028A_N [mm] "SOP, 28-Leads, Body 9.8x4.5mm, Pitch 0.65mm, IPC Medium Density"
  rrect22% 1.4x0.45 smd: 1(-2.95,4.225) 2(-2.95,3.575) 3(-2.95,2.925) 4(-2.95,2.275) 5(-2.95,1.625) 6(-2.95,0.975) 7(-2.95,0.325) 8(-2.95,-0.325) 9(-2.95,-0.975) 10(-2.95,-1.625) 11(-2.95,-2.275) 12(-2.95,-2.925) 13(-2.95,-3.575) 14(-2.95,-4.225) 15(2.95,-4.225) 16(2.95,-3.575) 17(2.95,-2.925) 18(2.95,-2.275) 19(2.95,-1.625) 20(2.95,-0.975) 21(2.95,-0.325) 22(2.95,0.325) 23(2.95,0.975) 24(2.95,1.625) 25(2.95,2.275) 26(2.95,2.925) 27(2.95,3.575) 28(2.95,4.225)
  silkscreen extent -3.07,-4.9 1.85,5.13, body extent -3.21,-4.85 3.21,4.85, height 1
RESC1609X55X30NL10T20 [mm] "Chip Resistor, 2-Leads, Body 1.60x0.85mm, IPC Medium Density"
  rect 0.95x0.95 smd: 1(-0.725,0) 2(0.725,0)
  body extent -0.85,-0.48 0.85,0.48, height 0.55
RGC0064B [mm] "VQFN-64"
  rrect42% 0.6x0.24 smd mask+0.07: 1(-4.4,3.75) 2(-4.4,3.25) 3(-4.4,2.75) 4(-4.4,2.25) 5(-4.4,1.75) 6(-4.4,1.25) 7(-4.4,0.75) 8(-4.4,0.25) 9(-4.4,-0.25) 10(-4.4,-0.75) 11(-4.4,-1.25) 12(-4.4,-1.75) 13(-4.4,-2.25) 14(-4.4,-2.75) 15(-4.4,-3.25) 16(-4.4,-3.75) 33(4.4,-3.75) 34(4.4,-3.25) 35(4.4,-2.75) 36(4.4,-2.25) 37(4.4,-1.75) 38(4.4,-1.25) 39(4.4,-0.75) 40(4.4,-0.25) 41(4.4,0.25) 42(4.4,0.75) 43(4.4,1.25) 44(4.4,1.75) 45(4.4,2.25) 46(4.4,2.75) 47(4.4,3.25) 48(4.4,3.75)
  rrect42% 0.24x0.6 smd mask+0.07: 17(-3.75,-4.4) 18(-3.25,-4.4) 19(-2.75,-4.4) 20(-2.25,-4.4) 21(-1.75,-4.4) 22(-1.25,-4.4) 23(-0.75,-4.4) 24(-0.25,-4.4) 25(0.25,-4.4) 26(0.75,-4.4) 27(1.25,-4.4) 28(1.75,-4.4) 29(2.25,-4.4) 30(2.75,-4.4) 31(3.25,-4.4) 32(3.75,-4.4) 49(3.75,4.4) 50(3.25,4.4) 51(2.75,4.4) 52(2.25,4.4) 53(1.75,4.4) 54(1.25,4.4) 55(0.75,4.4) 56(0.25,4.4) 57(-0.25,4.4) 58(-0.75,4.4) 59(-1.25,4.4) 60(-1.75,4.4) 61(-2.25,4.4) 62(-2.75,4.4) 63(-3.25,4.4) 64(-3.75,4.4)
  rrect2% 4.25x4.25 smd paste-2.112: 65(0,0)
  body extent -4.5,-4.5 4.5,4.5, height 1
Samtec_TSM-105-01-x-DV [mm] "Header, 2.54mm, 5x2, SMT"
  rect 3.68x1.27 smd: 1(-2.475,5.08) 2(2.475,5.08) 3(-2.475,2.54) 4(2.475,2.54) 5(-2.475,0) 6(2.475,0) 7(-2.475,-2.54) 8(2.475,-2.54) 9(-2.475,-5.08) 10(2.475,-5.08)
  silkscreen extent -1.65,-6.35 1.65,6.49, body extent -3.85,-6.35 3.85,6.35, height 9.65
Samtec_TSM-108-01-x-DV [mm] "Header, 2.54mm, 8x2, SMT"
  rect 3.68x1.27 smd: 1(-2.475,8.89) 2(2.475,8.89) 3(-2.475,6.35) 4(2.475,6.35) 5(-2.475,3.81) 6(2.475,3.81) 7(-2.475,1.27) 8(2.475,1.27) 9(-2.475,-1.27) 10(2.475,-1.27) 11(-2.475,-3.81) 12(2.475,-3.81) 13(-2.475,-6.35) 14(2.475,-6.35) 15(-2.475,-8.89) 16(2.475,-8.89)
  silkscreen extent -1.65,-10.16 1.65,10.3, body extent -3.85,-10.16 3.85,10.16, height 9.65
Samtec_TSW-103-08-x-S [mm] "Header, 2.54mm, 3x1, TH"
  rrect50% 1.53x1.53 hole 1.02: 1(-2.54,0)
  round 1.53 hole 1.02: 2(0,0) 3(2.515,0)
  body extent -3.94,-1.27 3.81,1.27, height 8.38
SM_RADIAL_E [mm] "8 x 6.2mm:  Panasonic E"
  rect 4x1.6 smd: 1(-3.1,0) 2(3.1,0)
  silkscreen extent -4.25,-4.25 4.25,4.25, body extent -4.25,-4.25 4.25,4.25, height 6.5
SMB-Bi [mil] "Molded Diode, 2-Leads, Body 5.4x3.6mm, IPC Medium Density, based on OnSemi component dimensions"
  rect 85x107.99 smd: 1(-87.01,0) 2(87.01,0)
  silkscreen extent -125,-79 125,79, body extent -104,-73 104,73, height 89
SW_FSM4JSMA [mm] "Alcoswitch"
  rrect7% 1.4x2.1 smd: 1(2.25,4.55) 2(2.25,-4.55) 3(-2.25,4.55) 4(-2.25,-4.55)
  body extent -3,-5 3,5, height 5.09
Testpoint_Keystone_Compact [mil] "Compact SMT test point"
  rect 185x135 smd: 1(0,0)
  silkscreen extent -110,-80 110,80, body extent -75,-56 75,56, height 91
Testpoint_Keystone_Miniature [mil] "Miniature SMT test point"
  rect 135x70 smd: 1(0,0)
  silkscreen extent -78,-46 78,45, body extent -52,-20 52,20, height 61
TI_Symbol_Overlay_Small [mil]
  silkscreen extent -90,-88 91,88
TP_H045P075 [mm] "TP_H0.45P0.75"
  round 0.75 hole 0.45: 1(0,0)
VAK0015A-MFG [mm]
  rrect40% 0.65x0.25 smd paste+0 mask+0: 1(-1.625,2.375) 2(-1.625,1.875) 3(-1.625,1.375) 8(1.625,1.375) 9(1.625,1.875) 10(1.625,2.375)
  rrect17% 4x0.6 smd paste-1000 mask-1000: 4(0,0.4)
  rrect20% 1.75x1 smd paste-1000 mask-1000: 5(-1.125,-0.9) 7(1.125,-0.9)
  rrect15% 4x1.35 smd paste-1000 mask-1000: 6(0,-2.575)
  rrect40% 0.25x0.65 smd paste+0 mask+0: 11(1,2.875) 12(0.5,2.875) 13(0,2.875) 14(-0.5,2.875) 15(-1,2.875)
  silkscreen extent -2.62,2.25 1.8,3.05, body extent -2.1,-3.35 2.1,3.3, height 0.25
WCAP-ATUL_D10H20 [mm] "Aluminum Electrolytic Capacitors, 10x20mm"
  rrect50% 1.4x1.4 hole 0.9: 1(2.5,0)
  round 1.4 hole 0.9: 2(-2.5,0)
  silkscreen extent -5.25,-5.25 5.25,5.25, body extent -4.99,-5 5,5, height 20.31
WCAP-CSGP_0402_L1W0.5H0.5 [mm] "Ceramic Capacitors, body 1x0.5mm"
  rect 0.5x0.5 smd: 1(-0.5,0) 2(0.5,0)
  body extent -0.5,-0.25 0.5,0.25, height 0.5
WCAP-CSGP_0805_L2W1.25H0.8_Reflow [mm] "Ceramic Capacitors, body 2x1.25mm"
  rect 0.9x1.3 smd: 1(-0.95,0) 2(0.95,0)
  body extent -1,-0.62 1,0.63, height 0.8
WCAP-CSGP_0805_L2W1.25H1.25 [mm] "Ceramic Capacitors, body 2x1.25mm"
  rect 0.9x1.3 smd: 1(-0.95,0) 2(0.95,0)
  body extent -1,-0.63 1,0.63, height 1.25
WCAP-CSGP_1210_L3.2W2.5H1.6 [mm] "Ceramic Capacitors, body 3.2x2.5mm"
  rect 0.9x2.5 smd: 1(-1.55,0) 2(1.55,0)
  silkscreen extent -0.8,-1.4 0.8,1.4, body extent -1.6,-1.25 1.6,1.25, height 1.6
WCAP-CSST_0805_L2W1.25H1.25 [mm] "Soft Termination MLCC, body 2.00x1.25mm"
  rect 0.9x1.3 smd: 1(-0.95,0) 2(0.95,0)
  body extent -1,-0.63 1,0.63, height 1.25
WCAP-CSST_1210_L3.2W2.5H2.5 [mm] "Soft Termination MLCC, body 3.20x2.50mm"
  rect 0.9x2.5 smd: 1(-1.55,0) 2(1.55,0)
  silkscreen extent -0.8,-1.5 0.8,1.5, body extent -1.6,-1.25 1.6,1.25, height 2.5
WE-HCC_1210 [mm] "WURTH"
  rect 2.9x5.4 smd: 1(-4.95,0) 2(4.95,0)
  silkscreen extent -6,-5.9 6,5.9, body extent -6,-5.85 6,5.85, height 10
WEEE_Minimum [mil] "WEEElie bin"
  silkscreen extent -95,-172 99,104
WL-SMCW_0805_150080xx75000 [mm] "SMD Mono-color Chip LED, body 2.0x1.25mm"
  rect 1.1x1.3 smd: 1(-1.05,0) 2(1.05,0)
  silkscreen extent -2,-0.6 -1.8,0.6, body extent -1,-0.63 1,0.62, height 0.7
WL-SMCW_GREEN [mm] "WURTH"
  rect 0.8x0.8 smd: 1(-0.8,0) 2(0.8,0)
  silkscreen extent -1.9,-0.8 1.2,0.8, body extent -0.85,-0.45 0.85,0.45, height 0.8
WL-SMCW_RED [mm] "WURTH"
  rect 0.8x0.8 smd: 1(-0.8,0) 2(0.8,0)
  silkscreen extent -1.9,-0.8 1.2,0.8, body extent -0.85,-0.45 0.85,0.45, height 0.8
Wurth_60900213421 [mil] "Shunt, 2.54mm, Black"
  round 1 on Mech3: 0(0,0)
  body extent -98,-48 98,48, height 338
Wurth_61000621121 [mm] "Header, 2.54mm, 3x2, SMT"
  rrect10% 3.1x1 smd: 1(-2.7,2.54) 2(2.7,2.54) 3(-2.7,0) 4(2.7,0) 5(-2.7,-2.54) 6(2.7,-2.54)
  body extent -3.75,-3.81 3.75,3.81, height 9.6
Wurth_61301421121 [mm] "Header, 2.54mm, 7x2, TH"
  rrect50% 1.65x1.65 hole 1.1: 1(-1.27,7.62)
  round 1.65 hole 1.1: 2(1.27,7.62) 3(-1.27,5.08) 4(1.27,5.08) 5(-1.27,2.54) 6(1.27,2.54) 7(-1.27,0) 8(1.27,0) 9(-1.27,-2.54) 10(1.27,-2.54) 11(-1.27,-5.08) 12(1.27,-5.08) 13(-1.27,-7.62) 14(1.27,-7.62)
  body extent -2.54,-8.89 2.54,8.89, height 8.55

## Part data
C1: library part CMP-0011164-2, "CAP, AL, 10 uF, 100 V, +/- 20%, AEC-Q200 Grade 3, SMD", Cap_Case=8.0x6.0mm, Manufacturer=Panasonic, Supplier Part Number 1=PCE3966CT-ND, Tolerance_%=20%, Value1=Unknown, Value2=100V, ValueDisplayed=10uF
C2 C3: library part CMP-0008709-2, "CAP, CERM, 0.1 uF, 100 V, +/- 10%, X7R, 1206", Cap_Case=1206_180, Manufacturer=TDK, Supplier Part Number 1=445-1377-1-ND, TempCo=X7R, Tolerance_%=10%, Value1="0.030343 ohm", Value2=100V, ValueDisplayed=0.1uF
C5 C28 C33: library part CMP-0064924-2, "CAP, CERM, 1 uF, 10 V,+/- 20%, X5R, 0402", Cap_Case=0402, Manufacturer="Wurth Elektronik", Supplier Part Number 1=732-7489-1-ND, TempCo=X5R, Tolerance_%=20%, Value1=Unknown, Value2=10V, ValueDisplayed=1uF
C6 C13: library part CMP-0007891-2, "CAP, CERM, 1 uF, 100 V, +/- 10%, X7S, 0805", Cap_Case=0805, Manufacturer=TDK, Supplier Part Number 1=445-5205-1-ND, TempCo=X7S, Tolerance_%=10%, Value1="0.008255 ohm", Value2=100V, ValueDisplayed=1uF
C7 C12: library part CMP-0097294-1, "0.1 µF ±10% 100V Ceramic Capacitor X7R 0603 (1608 Metric)", Digikey Part Number=732-885012206120TR-ND, Manufacturer="Wurth Electronics", Mouser Part Number=710-885012206120, Operating Temperature Range="-55°C to +125°C", TempCo=15%, Temperature Characteristic=X7R, Tolerance_%=10%, ValueDisplayed=100nF
C8 C11: library part CMP-0079993-1, "CAP, CERM, 0.01 µF, 100 V,+/- 10%, X7R, 0603", Cap_Case=0603, Manufacturer="Wurth Elektronik", Supplier Part Number 1=45AC8565, TempCo=X7R, Tolerance_%=10%, Value2=100V, ValueDisplayed=0.01µF
C9: library part CMP-0105009-1, "WCAP-CSGP Multilayer Ceramic Chip Capacitor, General Purpose, size 1210, X7R, 3.3µF, 25VDC", Capacitance Tolerance=+/-10%, Insulation Resistance=0.2GOhm, Manufacturer="Wurth Elektronik", Operating Temperature Max=125°C, Operating Temperature Min=-55°C, Rated Voltage (DC)=25V
C10 C40 C41 C43: library part CMP-0102582-1, "WCAP-ATUL Aluminum Electrolytic Capacitor, Radial, THT, D10 x H20mm, 82µF, 100V", Capacitance Tolerance=20%, Leakage Current=82uA, Manufacturer="Wurth Elektronik", Operating Temperature Max=105°C, Operating Temperature Min=-40°C, Rated Voltage (DC)=100V, Ripple Current=600mA
C14 C15: library part CMP-0006724-5, "CAP, CERM, 1000 pF, 100 V, +/- 10%, X7R, 0603", Cap_Case=0603, Manufacturer=AVX, Supplier Part Number 1=478-1199-1-ND, TempCo=X7R, Tolerance_%=10%, Value1="0.276 ohm", Value2=100V, ValueDisplayed=1000pF
C16: library part CMP-0115610-1, "WCAP-CSGP Multilayer Ceramic Chip Capacitor, General Purpose, size 0805, X7R, 22nF, 100VDC", Capacitance Tolerance=+/-10%, Insulation Resistance=4.5GOhm, Manufacturer="Wurth Elektronik", Operating Temperature Max=125°C, Operating Temperature Min=-55°C, Rated Voltage (DC)=100V
C17: library part CMP-0006268-2, "CAP, CERM, 4.7 uF, 10 V, +/- 10%, X5R, 0402", Cap_Case=0402_065, Manufacturer=TDK, PartNumber=C1005X5R1A475K050BC, Supplier Part Number 1=445-13820-1-ND, TempCo=X5R, Tolerance_%=10%, Value1="0.003417 ohm", Value2=10V, ValueDisplayed=4.7uF
C18: library part CMP-0064931-4, "CAP, CERM, 0.1 uF, 10 V,+/- 10%, X7R, 0603", Cap_Case=0603, Manufacturer="Wurth Elektronik", Supplier Part Number 1=732-7939-1-ND, TempCo=X7R, Tolerance_%=10%, Value1=Unknown, Value2=10V, ValueDisplayed=0.1uF
C19: library part CMP-0006269-2, "CAP, CERM, 4.7 uF, 10 V, +/- 20%, X5R, 0402", Cap_Case=0402, Manufacturer=TDK, Supplier Part Number 1=445-8023-1-ND, TempCo=X5R, Tolerance_%=20%, Value1=Unknown, Value2=10V, ValueDisplayed=4.7uF
C20 C22 C29 C35 C36 C37 C45: library part CMP-0006562-2, "CAP, CERM, 0.1 uF, 10 V, +/- 10%, X5R, 0402", Cap_Case=0402, Manufacturer=MuRata, Supplier Part Number 1=490-1318-1-ND, TempCo=X5R, Tolerance_%=10%, Value1=Unknown, Value2=10V, ValueDisplayed=0.1uF
C21 C24: library part CMP-0006250-2, "CAP, CERM, 33 pF, 50 V, +/- 5%, C0G/NP0, 0402", Cap_Case=0402, Manufacturer=TDK, Supplier Part Number 1=445-1241-1-ND, TempCo=C0G/NP0, Tolerance_%=5%, Value1=Unknown, Value2=50V, ValueDisplayed=33pF
C23 C52: library part CMP-0006673-2, "CAP, CERM, 1000 pF, 50 V, +/- 10%, X7R, 0402", Cap_Case=0402, Manufacturer=MuRata, Supplier Part Number 1=490-1303-1-ND, TempCo=X7R, Tolerance_%=10%, Value1=Unknown, Value2=50V, ValueDisplayed=1000pF
C25 C27 C44: library part CMP-0006570-2, "CAP, CERM, 0.22 uF, 10 V, +/- 10%, X5R, 0402", Cap_Case=0402, Manufacturer=MuRata, Supplier Part Number 1=490-3910-1-ND, TempCo=X5R, Tolerance_%=10%, Value1=Unknown, Value2=10V, ValueDisplayed=0.22uF
C26: library part CMP-0006600-2, "CAP, CERM, 0.47 uF, 16 V, +/- 10%, X5R, 0402", Cap_Case=0402, Manufacturer=MuRata, TempCo=X5R, Tolerance_%=10%, Value1=Unknown, Value2=16V, ValueDisplayed=0.47uF
C30 C32: library part CMP-0006639-2, "CAP, CERM, 0.01 uF, 16 V, +/- 10%, X7R, 0402", Cap_Case=0402, Manufacturer=MuRata, Supplier Part Number 1=490-1313-1-ND, TempCo=X7R, Tolerance_%=10%, Value1=Unknown, Value2=16V, ValueDisplayed=0.01uF
C31: library part CMP-0006594-2, "CAP, CERM, 2.2 uF, 16 V, +/- 10%, X5R, 0402", Cap_Case=0402, Manufacturer=MuRata, PartNumber=GRM155R61C225KE11D, Supplier Part Number 1=490-10695-1-ND, TempCo=X5R, Tolerance_%=10%, Value1=Unknown, Value2=16V
C34: library part CMP-0084376-1, "CAP, Tantalum Polymer, 10 µF, 10 V,+/- 20%, 0.08 ohm, 3216-18 SMD", Cap_Case=3216-18, Manufacturer=Kemet, Tolerance_%=20%, Value1="0.08 ohm", Value2=10V, ValueDisplayed=10µF
C38 C39: library part CMP-0007081-4, "CAP, CERM, 1000 pF, 100 V, +/- 10%, X7R, AEC-Q200 Grade 1, 0603", Cap_Case=0603, Manufacturer=TDK, Supplier Part Number 1=445-5806-1-ND, TempCo=X7R, Tolerance_%=10%, Value1="1.97137 ohm", Value2=100V, ValueDisplayed=1000pF
C42: library part CMP-0105213-1, "WCAP-CSST Multilayer Ceramic Chip Capacitor, Soft Termination, size 0805, X7R Class II, 10nF, 100VDC", Capacitance Tolerance=+/-10%, Insulation Resistance=10GOhm, Manufacturer="Wurth Elektronik", Operating Temperature Max=125°C, Operating Temperature Min=-55°C, Rated Voltage (DC)=100V
C47 C48 C49 C50: library part CMP-0064916-2, "CAP, CERM, 10 pF, 50 V,+/- 1%, C0G/NP0, 0402", Cap_Case=0402, Manufacturer=MuRata, Supplier Part Number 1=490-6186-1-ND, TempCo=C0G/NP0, Tolerance_%=1%, Value1=Unknown, Value2=50V, ValueDisplayed=10pF
C51: library part CMP-0119921-1, "WCAP-CSST Multilayer Ceramic Chip Capacitor, Soft Termination, size 1210, X7R Class II, 2.2µF, 100VDC", Capacitance Tolerance=+/-10%, Insulation Resistance=0.05GOhm, Manufacturer="Wurth Elektronik", Operating Temperature Max=125°C, Operating Temperature Min=-55°C, Rated Voltage (DC)=100V
C53: library part CMP-0007078-4, "CAP, CERM, 0.1 uF, 50 V, +/- 10%, X7R, AEC-Q200 Grade 1, 0603", Cap_Case=0603, Manufacturer=TDK, Supplier Part Number 1=445-5666-1-ND, TempCo=X7R, Tolerance_%=10%, Value1="0.0296 ohm", Value2=50V, ValueDisplayed=0.1uF
C59: library part CMP-0115207-1, "WCAP-CSGP Multilayer Ceramic Chip Capacitor, General Purpose, size 0402, X5R, 100nF, 6.3VDC", Capacitance Tolerance=+/-20%, Insulation Resistance=1GOhm, Manufacturer="Wurth Elektronik", Operating Temperature Max=85°C, Operating Temperature Min=-55°C, Rated Voltage (DC)=6.3V
C70: library part CMP-0108445-1, "WCAP-CSGP Multilayer Ceramic Chip Capacitor, General Purpose, size 0805, X7R, 100nF, 100VDC", Capacitance Tolerance=+/-10%, Insulation Resistance=1GOhm, Manufacturer="Wurth Elektronik", Operating Temperature Max=125°C, Operating Temperature Min=-55°C, Rated Voltage (DC)=100V
D1 D7: library part CMP-1426-00009-5, "SMD mono-color Chip LED, WL-SMCW, Bright Green", Case Code (Imperial)=0805, Case Code (Metric)=2012, Color=Green, Forward Current=100mA, Forward Voltage=2V, Manufacturer="Wurth Elektronik", Max Junction Temperature (Tj)=95°C, Max Operating Temperature=85°C, Max Reverse Voltage (DC)=5V, Min Operating Temperature=-40°C, Power Dissipation=72mW, Test Current=20mA
D2: library part CMP-1426-00010-3, "SMD mono-color Chip LED, WL-SMCW, Super Red", Case Code (Imperial)=0805, Case Code (Metric)=2012, Color=Red, Forward Current=100mA, Forward Voltage=1.9V, Manufacturer="Wurth Elektronik", Max Junction Temperature (Tj)=95°C, Max Operating Temperature=85°C, Max Reverse Voltage (DC)=5V, Min Operating Temperature=-40°C, Power Dissipation=72mW, Test Current=20mA
D3: library part CMP-0002894-2, "LED, Green, SMD", Color=green, Manufacturer="Wurth Elektronik", Value1=W, Value2=2V
D4: library part CMP-0005564-3, "Diode, TVS, Bi, 33 V, SMB", Manufacturer="Diodes Inc.", Value1=600W
D5: library part CMP-0002947-3, "LED, Red, SMD", Color=Red, Manufacturer="Wurth Elektronik", Power_TotalModule=72mW, Value1=0.072W, Value2=2V
D6: "LED, Green, SMD", Color=green, Manufacturer="Wurth Elektronik", PartNumber=150060VS75000, Value1=W, Value2=2V
D8: library part CMP-0097377-1, "Diode Zener Single 4.7V 2% 550mW Automotive 2-Pin SOD-323F T/R", Digikey Part Number=1727-1672-1-ND, Forward Current=250mA, Manufacturer=Nexperia, Max Reverse Leakage Current=3uA, Mouser Part Number=771-BZX84J-B4V7,115, Operating Temperature Range="to +150°C", Power_W=550mW
F1 F2: library part CMP-0077200-3, "Fuse, 30 A, 250 VAC, 100 VDC, SMD", Irating_A=30A, Manufacturer=Littelfuse, Supplier Part Number 1=F6439CT-ND
FID1 FID2 FID3: library part CMP-0077181-1, "Fiducial mark.  There is nothing to buy or mount.", Manufacturer=N/A
J1: library part CMP-77940-000002-1, "CONN HEADER VERT 3POS 2.54MM", Current Rating=3A, Manufacturer="Metz Connect", Temperature="-40°C to +105°C", Temperature Range High=+105°C, Temperature Range Low=-40°C
J2: library part CMP-0075595-1, "Header, 2.54mm, 8x2, Gold, SMT", Color=Black, Current_A=4.9A, Manufacturer=Samtec, Supplier Part Number 1=SAM8884-ND, Voltage_V=475V
J3 J8 J9: library part CMP-0055418-2, "Banana Jack Insul Nylon Red, R/A, TH", Color=Red, Current_A=25A, Manufacturer="Cal Test Electronics", Supplier Part Number 1=BKCT3151SP-2-ND, Voltage_V=1kV
J4: library part CMP-0085938-1, "Header, 2.54mm, 12x2, Gold, TH", Color=Black, Current_A=5A, Manufacturer=FCI, Voltage_V=1.5kV
J5: library part CMP-0086014-1, "Header, 2.54mm, 7x2, Gold, TH", Color=Black, Current_A=3A, Manufacturer="Wurth Elektronik", Voltage_V=250V
J6: "Receptacle, USB 2.0, Micro B, 5 Position, R/A, SMT", Color=Black, Current_A=1.8A, Manufacturer=Molex, PartNumber=1051640001, Supplier Part Number 1=WM11263CT-ND, Voltage_V=30V
J7: library part CMP-0002339-2, "Header, 100mil, 7x2, Tin, TH", Color=Black, Current_A=3A, Manufacturer="Sullins Connector Solutions", Supplier Part Number 1=S2012E-07-ND, Voltage_V=1.8kV
J10 J11 J12: library part CMP-0055598-2, "Header, 2.54mm, 5x2, Gold, SMT", Color=Black, Current_A=5.4A, Manufacturer=Samtec, Supplier Part Number 1=SAM8741-ND, Voltage_V=475V
J13: library part CMP-0079534-2, "Header, 2.54mm, 3x2, Gold, SMT", Color=Black, Current_A=3A, Manufacturer="Wurth Elektronik", Supplier Part Number 1=732-5461-5-ND, Voltage_V=250V
J14: library part CMP-0086764-1, Current_A=57A, Manufacturer=Wurth, Voltage_V=750V
J15 J18: library part CMP-0075110-1, "1mm Uninsulated Shorting Plug, 10.16mm spacing, TH", Manufacturer=Harwin, Supplier Part Number 1=952-1873-ND
J16: library part CMP-0079327-1, "Header, 2.54mm, 3x1, Gold, TH", Color=Black, Manufacturer=Samtec, Supplier Part Number 1=SAM1038-03-ND
J17: library part CMP-0055417-2, "Banana Jack Insul Nylon Black, R/A, TH", Color=Black, Current_A=25A, Manufacturer="Cal Test Electronics", Supplier Part Number 1=BKCT3151SP-0-ND, Voltage_V=1kV
L1: library part CMP-0063986-1, "Inductor, Shielded Drum Core, Ferrite, 1 uH, 24 A, 0.0012 ohm, SMD", Manufacturer="Wurth Elektronik", Supplier Part Number 1=732-2138-1-ND, Value1="0.0012 ohm", Value2=24A, ValueDisplayed=1uH
L2 L3: library part CMP-0081962-1, "Ferrite Bead, 150 ohm @ 100 MHz, 0.7 A, 0603", Manufacturer=MuRata, Supplier Part Number 1=490-14035-1-ND, Value1="0.35 ohm", Value2=0.7A, ValueDisplayed="150 ohm"
LBL1: library part CMP-0003625-1, "Thermal Transfer Printable Labels, 0.650\" W x 0.200\" H - 10,000 per roll", Manufacturer=Brady, Supplier Part Number 1=97C5133
Logo1: library part CMP-0074844-2, Manufacturer="Texas Instruments"
Logo2: library part CMP-0074838-1, "Texas Instrument Corporate Signature"
Logo3: library part CMP-0074847-1, "FCC_disclaimer"
Logo4: library part CMP-0074769-4, Manufacturer="Texas Instruments"
Logo5: library part CMP-0074836-1, "IEC 61010-1 Caution Warning"
LOGO6 LOGO7: library part CMP-0074837-2, "IEC 61010-1 Hot Surface Warning", Manufacturer="Texas Instruments"
MP1 MP2 MP3 MP4: library part CMP-0122650-1, "Bumper Cylindrical, Dome 0.720\" Dia (18.30mm) Polyurethane Black", Digikey Part Number=RPC4835-ND, Manufacturer="Essentra Components", Mouser Part Number=144-RBS-37BK, Operating Temperature Range="32°F to 122°F"
Q1: library part CMP-0000915-2, "MOSFET, N-CH, 80 V, 100 A, DNK0008A (VSON-CLIP-8)", Alternate Manufacturer=None, Manufacturer="Texas Instruments", Supplier Part Number 1=296-37194-1-ND, Value2="48 nC"
Q2: library part CMP-1048-00779-1, "General Purpose Transistor, NPN Silicon, 3-Pin SOT-23, Pb-Free, Tape and Reel", Manufacturer="On Semiconductor"
R1: library part CMP-0023626-3, "RES, 10.0 k, 0.01%, 0.063 W, 0603", Manufacturer="Stackpole Electronics Inc", Power_W=63mW, Supplier Part Number 1=RNCF0603TKY10K0CT-ND, TempCo="5 ppm/C", Tolerance_%=0.01%, Value2=0.063W, Value_Code=10k0, ValueDisplayed=10.0k
R2 R3 R20: "RES, 330, 5%, 0.1 W, AEC-Q200 Grade 0, 0603", Manufacturer=Vishay-Dale, PartNumber=CRCW0603330RJNEA, Power_W=100mW, Supplier Part Number 1=541-330GCT-ND, TempCo="200 ppm/C", Tolerance_%=5%, Value2=0.1W, Value_Code=330R, ValueDisplayed=330
R4 R37 R73: library part CMP-0026935-3, "RES, 47 k, 5%, 0.063 W, AEC-Q200 Grade 0, 0402", Manufacturer=Vishay-Dale, Power_W=63mW, Supplier Part Number 1=541-47KJCT-ND, TempCo="200 ppm/C", Tolerance_%=5%, Value2=0.063W, Value_Code=47k0, ValueDisplayed=47k
R5 R19: library part CMP-0023129-5, "RES, 470, 1%, 0.1 W, 0603", Manufacturer=Yageo, Power_W=100mW, Supplier Part Number 1=311-470HRCT-ND, TempCo="100 ppm/C", Tolerance_%=1%, Value2=0.1W, Value_Code=470R, ValueDisplayed=470
R6: library part CMP-0023235-5, "RES, 680, 1%, 0.1 W, 0603", Manufacturer=Yageo, Power_W=100mW, Supplier Part Number 1=311-680HRCT-ND, TempCo="100 ppm/C", Tolerance_%=1%, Value2=0.1W, Value_Code=680R, ValueDisplayed=680
R7: library part CMP-0022895-5, "RES, 1.00 k, 1%, 0.1 W, 0603", Manufacturer=Yageo, Power_W=100mW, Supplier Part Number 1=311-1.00KHRCT-ND, TempCo="100 ppm/C", Tolerance_%=1%, Value2=0.1W, Value_Code=1k00, ValueDisplayed=1.00k
R8: library part CMP-0022883-5, "RES, 1.50 k, 1%, 0.1 W, 0603", Manufacturer=Yageo, Power_W=100mW, Supplier Part Number 1=311-1.50KHRCT-ND, TempCo="100 ppm/C", Tolerance_%=1%, Value2=0.1W, Value_Code=1k50, ValueDisplayed=1.50k
R9: library part CMP-0022986-5, "RES, 2.20 k, 1%, 0.1 W, 0603", Manufacturer=Yageo, Power_W=100mW, Supplier Part Number 1=311-2.20KHRCT-ND, TempCo="100 ppm/C", Tolerance_%=1%, Value2=0.1W, Value_Code=2k20, ValueDisplayed=2.20k
R10: library part CMP-0023081-5, "RES, 3.30 k, 1%, 0.1 W, 0603", Manufacturer=Yageo, Power_W=100mW, Supplier Part Number 1=311-3.30KHRCT-ND, TempCo="100 ppm/C", Tolerance_%=1%, Value2=0.1W, Value_Code=3k30, ValueDisplayed=3.30k
R11: library part CMP-0023153-5, "RES, 4.70 k, 1%, 0.1 W, 0603", Manufacturer=Yageo, Power_W=100mW, Supplier Part Number 1=311-4.70KHRCT-ND, TempCo="100 ppm/C", Tolerance_%=1%, Value2=0.1W, Value_Code=4k70, ValueDisplayed=4.70k
R12: library part CMP-0023253-5, "RES, 6.80 k, 1%, 0.1 W, 0603", Manufacturer=Yageo, Power_W=100mW, Supplier Part Number 1=311-6.80KHRCT-ND, TempCo="100 ppm/C", Tolerance_%=1%, Value2=0.1W, Value_Code=6k80, ValueDisplayed=6.80k
R13 R14 R15 R16 R17 R39 R40 R52: library part CMP-0086358-1, "RES, 0, 0%, 0.25 W, AEC-Q200 Grade 0, 0603", Manufacturer=Rohm, Power_W=250mW, Tolerance_%=0%, Value2=0.25W, Value_Code=0000, ValueDisplayed=0
R18: library part CMP-0025925-5, "RES, 47 k, 5%, 0.1 W, 0603", Manufacturer=Yageo, Power_W=100mW, Supplier Part Number 1=311-47KGRCT-ND, TempCo="100 ppm/C", Tolerance_%=5%, Value2=0.1W, Value_Code=47k0, ValueDisplayed=47k
R21 R22 R23 R24 R29 R30 R31 R67 R69 R70 R71 R72: library part CMP-0025886-5, "RES, 10 k, 5%, 0.1 W, 0603", Manufacturer=Yageo, Power_W=100mW, Supplier Part Number 1=311-10KGRCT-ND, TempCo="100 ppm/C", Tolerance_%=5%, Value2=0.1W, Value_Code=10k0, ValueDisplayed=10k
R25 R26 R27 R28: library part CMP-2000-03817-1, Manufacturer="Vishay Dale"
R32: library part CMP-0026190-2, "RES, 240 k, 1%, 0.063 W, AEC-Q200 Grade 0, 0402", Manufacturer=Vishay-Dale, Power_W=63mW, Supplier Part Number 1=541-240KLCT-ND, TempCo="100 ppm/C", Tolerance_%=1%, Value2=0.063W, Value_Code=240k
R33: library part CMP-0026934-3, "RES, 470, 5%, 0.063 W, AEC-Q200 Grade 0, 0402", Manufacturer=Vishay-Dale, Power_W=63mW, Supplier Part Number 1=541-470JCT-ND, TempCo="200 ppm/C", Tolerance_%=5%, Value2=0.063W, Value_Code=470R, ValueDisplayed=470
R34: library part CMP-0026914-3, "RES, 390, 5%, 0.063 W, AEC-Q200 Grade 0, 0402", Manufacturer=Vishay-Dale, Power_W=63mW, Supplier Part Number 1=541-390JCT-ND, TempCo="200 ppm/C", Tolerance_%=5%, Value2=0.063W, Value_Code=390R, ValueDisplayed=390
R35: library part CMP-0026021-3, "RES, 150 k, 1%, 0.063 W, AEC-Q200 Grade 0, 0402", Manufacturer=Vishay-Dale, Power_W=63mW, Supplier Part Number 1=541-150KLCT-ND, TempCo="100 ppm/C", Tolerance_%=1%, Value2=0.063W, Value_Code=150k
R36 R38: library part CMP-0026728-1, "RES, 220 k, 1%, 0.0625 W, 0402", Manufacturer="Yageo America", Power_W=62.5mW, Supplier Part Number 1=311-220KLRCT-ND, TempCo="100 ppm/C", Tolerance_%=1%, Value2=0.0625W, Value_Code=220k
R41 R42: library part CMP-0026992-3, "RES, 0, 5%, 0.1 W, AEC-Q200 Grade 0, 0402", Manufacturer=Panasonic, Power_W=100mW, Supplier Part Number 1=P0.0JCT-ND, TempCo="600 ppm/C", Tolerance_%=5%, Value2=0.1W, Value_Code=0000, ValueDisplayed=0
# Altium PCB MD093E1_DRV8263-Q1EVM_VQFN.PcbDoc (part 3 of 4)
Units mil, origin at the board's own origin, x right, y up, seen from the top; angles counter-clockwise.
Board outline 3224.41 x 4078.74 mil, 4 copper layers (Top Layer, Signal Layer 1, Signal Layer 2, Bottom Layer), stack 61.2 mil thick; 228 components, 126 nets, 641 pads, 753 vias.
Unrouted connection lines stored in the file: 76.

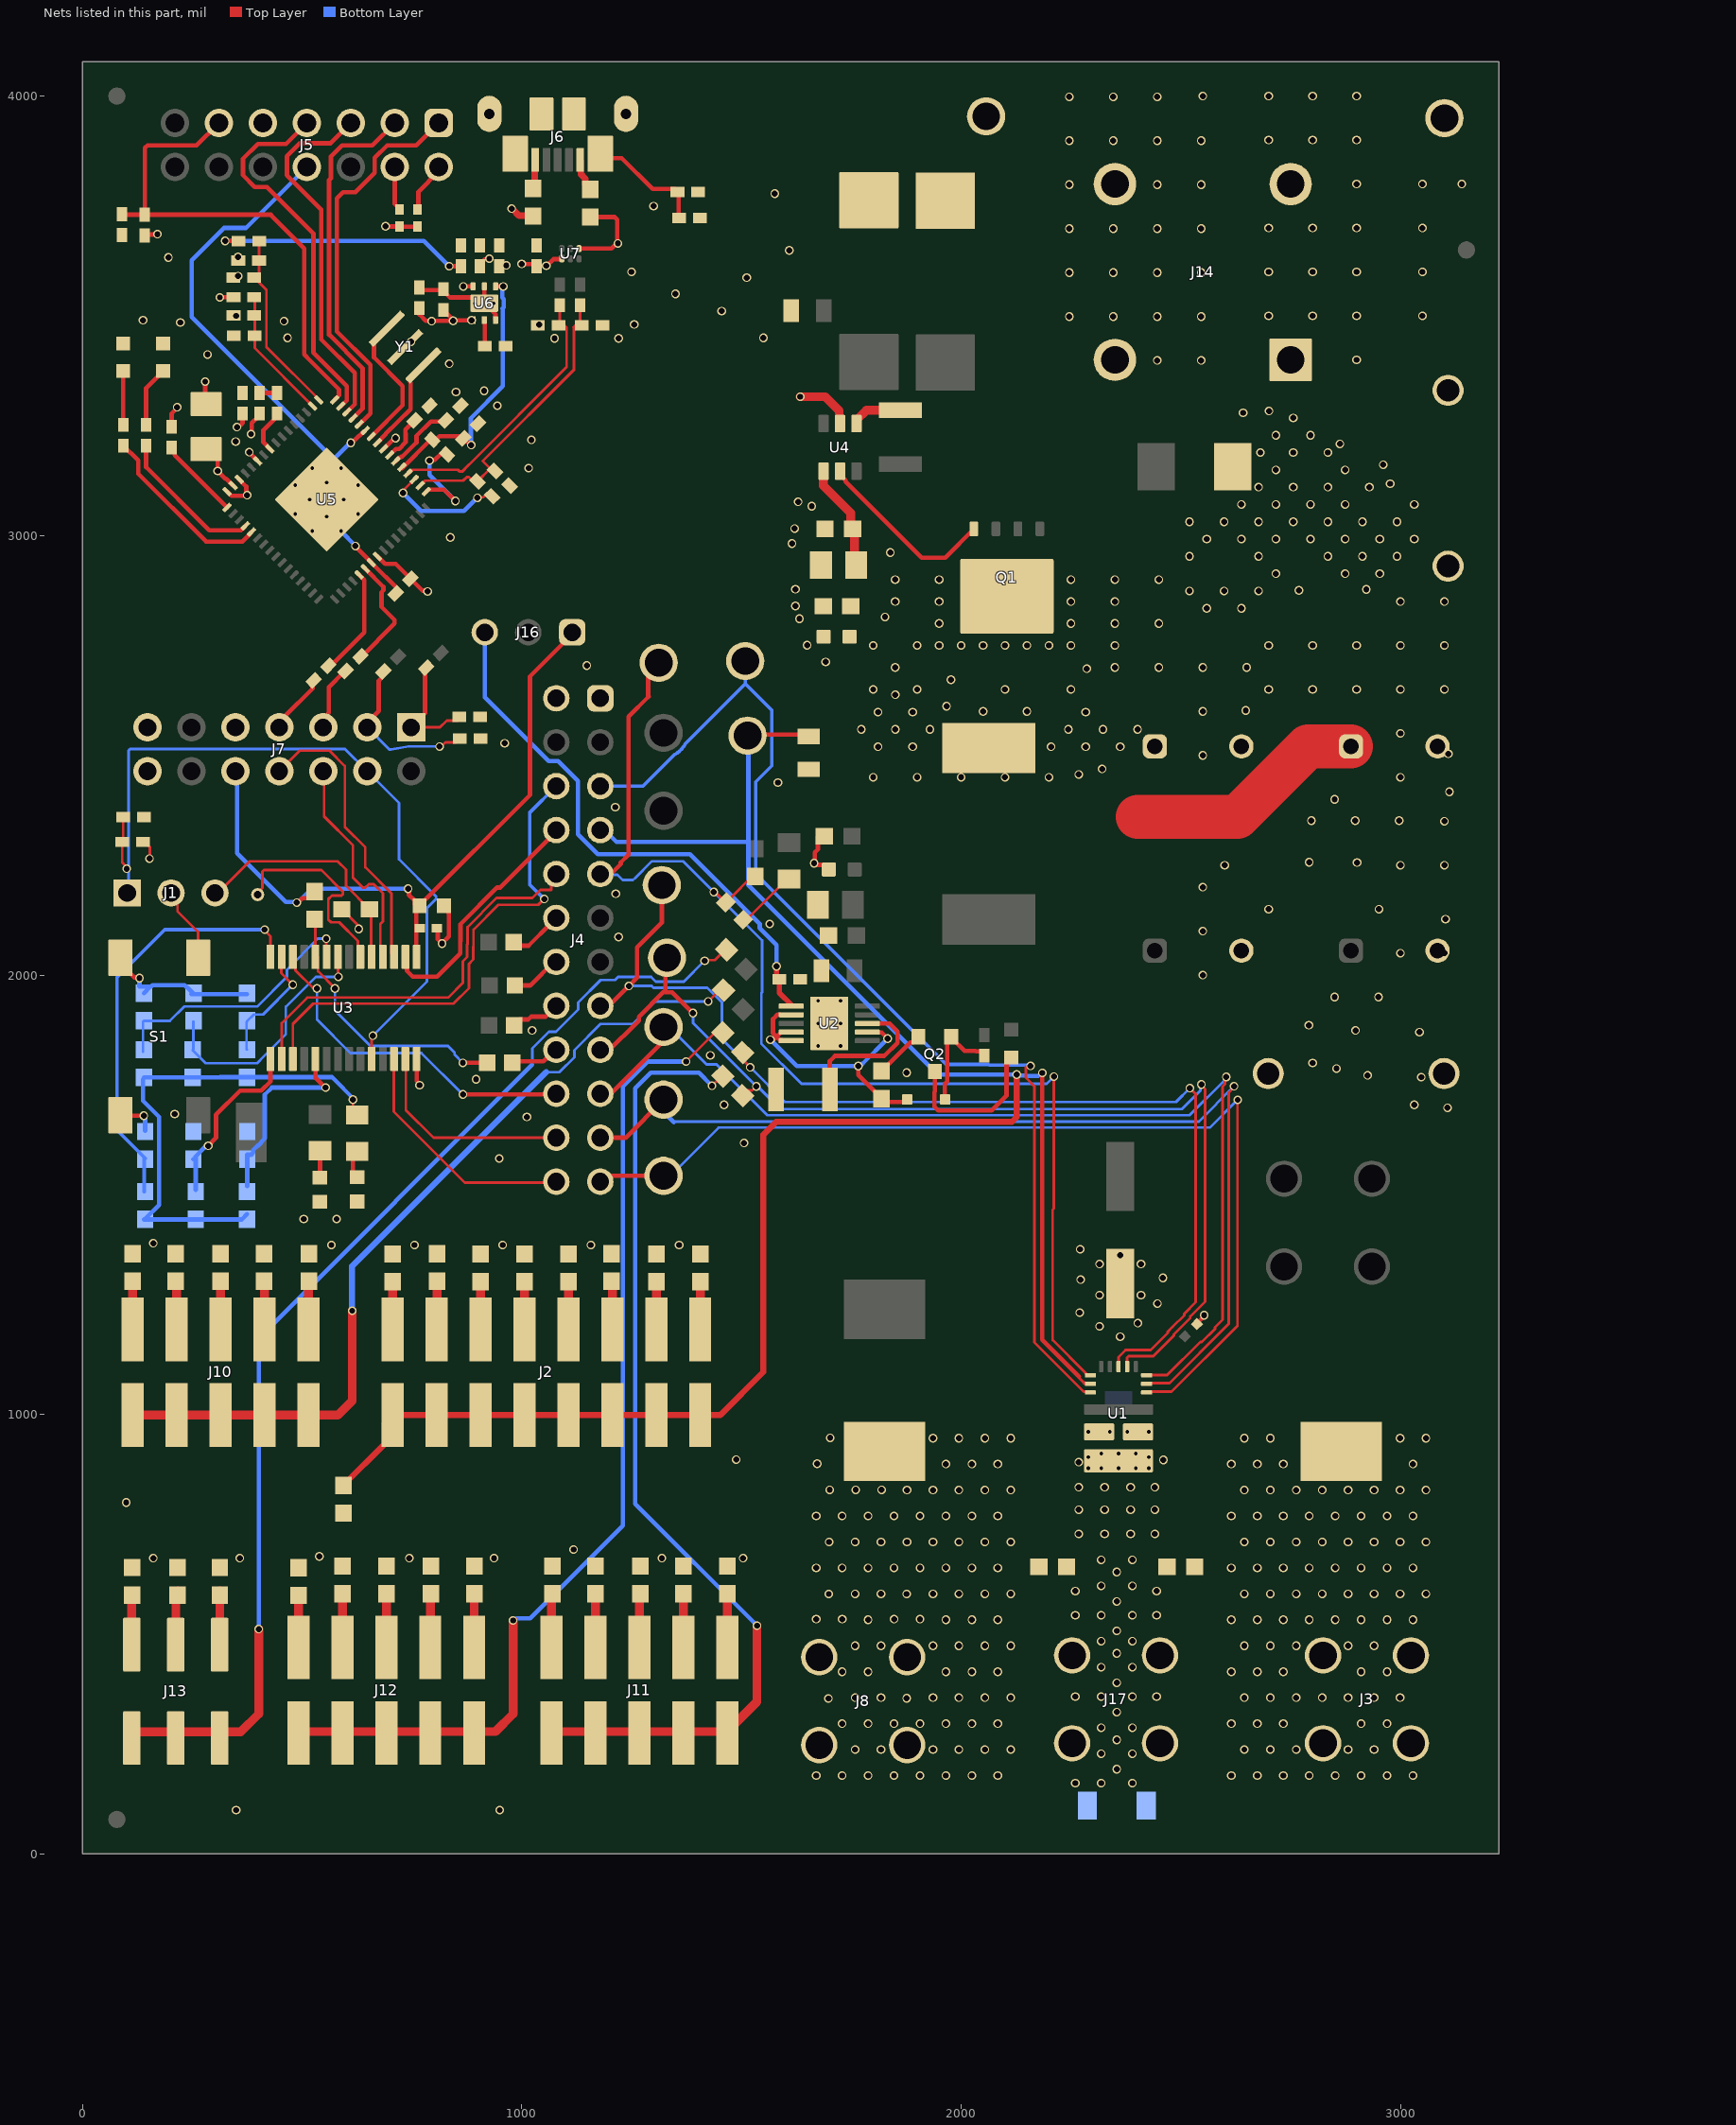
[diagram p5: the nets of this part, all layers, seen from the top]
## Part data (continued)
R43 R44: library part CMP-0026888-3, "RES, 27, 5%, 0.063 W, AEC-Q200 Grade 0, 0402", Manufacturer=Vishay-Dale, Power_W=63mW, Supplier Part Number 1=541-27JCT-ND, TempCo="200 ppm/C", Tolerance_%=5%, Value2=0.063W, Value_Code=27R0, ValueDisplayed=27
R45: library part CMP-0026085-3, "RES, 1.40 k, 1%, 0.063 W, AEC-Q200 Grade 0, 0402", Manufacturer=Vishay-Dale, Power_W=63mW, Supplier Part Number 1=541-1.40KLCT-ND, TempCo="100 ppm/C", Tolerance_%=1%, Value2=0.063W, Value_Code=1k40, ValueDisplayed=1.40k
R46: library part CMP-0026859-2, "RES, 1.0 M, 5%, 0.063 W, AEC-Q200 Grade 0, 0402", Manufacturer=Vishay-Dale, Power_W=63mW, Supplier Part Number 1=541-1.0MJCT-ND, TempCo="200 ppm/C", Tolerance_%=5%, Value2=0.063W, Value_Code=1M00, ValueDisplayed=1.0M
R47 R48 R49 R50: library part CMP-0025963-3, "RES, 10.0, 1%, 0.063 W, AEC-Q200 Grade 0, 0402", Manufacturer=Vishay-Dale, Power_W=63mW, Supplier Part Number 1=541-10.0LCT-ND, TempCo="100 ppm/C", Tolerance_%=1%, Value2=0.063W, Value_Code=10R0, ValueDisplayed=10.0
R51: library part CMP-0026907-3, "RES, 33 k, 5%, 0.063 W, AEC-Q200 Grade 0, 0402", Manufacturer=Vishay-Dale, Power_W=63mW, Supplier Part Number 1=541-33KJCT-ND, TempCo="200 ppm/C", Tolerance_%=5%, Value2=0.063W, Value_Code=33k0, ValueDisplayed=33k
R53 R54 R55 R56: library part CMP-0025862-4, "RES, 8.2 k, 5%, 0.1 W, AEC-Q200 Grade 0, 0603", Manufacturer=Vishay-Dale, Power_W=100mW, Supplier Part Number 1=541-8.2KGCT-ND, TempCo="200 ppm/C", Tolerance_%=5%, Value2=0.1W, Value_Code=8k20, ValueDisplayed=8.2k
R57 R58 R59: library part CMP-0025757-4, "RES, 22 k, 5%, 0.1 W, AEC-Q200 Grade 0, 0603", Manufacturer=Vishay-Dale, Power_W=100mW, Supplier Part Number 1=541-22KGCT-ND, TempCo="200 ppm/C", Tolerance_%=5%, Value2=0.1W, Value_Code=22k0, ValueDisplayed=22k
R60: library part CMP-0025860-4, "RES, 82 k, 5%, 0.1 W, AEC-Q200 Grade 0, 0603", Manufacturer=Vishay-Dale, Power_W=100mW, Supplier Part Number 1=541-82KGCT-ND, TempCo="200 ppm/C", Tolerance_%=5%, Value2=0.1W, Value_Code=82k0, ValueDisplayed=82k
R61 R62 R63: library part CMP-0022438-4, "RES, 47.0 k, 1%, 0.1 W, AEC-Q200 Grade 0, 0603", Manufacturer=Vishay-Dale, Power_W=100mW, Supplier Part Number 1=541-47.0KHCT-ND, TempCo="100 ppm/C", Tolerance_%=1%, Value2=0.1W, Value_Code=47k0, ValueDisplayed=47.0k
R64 R65 R66: library part CMP-0086261-1, "RES, 100 k, 0.5%, 0.1 W, AEC-Q200 Grade 0, 0603", Manufacturer=Vishay-Dale, Power_W=100mW, TempCo="50 ppm/C", Tolerance_%=0.5%, Value2=0.1W, Value_Code=100k
R68: library part CMP-0025886-3, "RES, 10 k, 5%, 0.1 W, 0603", Manufacturer="Yageo America", Power_W=100mW, Supplier Part Number 1=311-10KGRCT-ND, TempCo="100 ppm/C", Tolerance_%=5%, Value2=0.1W, Value_Code=10k0, ValueDisplayed=10k
S1: library part CMP-0002134-3, "Switch, Tactile, SPST-NO, 0.05A, 12V, SMT", CurrentRating_mA=50A, Manufacturer="TE Connectivity", Supplier Part Number 1=450-1129-ND
SH-J1 SH-J2 SH-J3 SH-J4 SH-J5 SH-J6 SH-J7 SH-J8 SH-J9 SH-J10 SH-J11 SH-J12 SH-J13 SH-J14 SH-J15 SH-J16 SH-J17 SH-J18 SH-J19 SH-J20 SH-J21 SH-J22 SH-J23 SH-J24: library part CMP-0003761-2, "Shunt, 2.54mm, Gold, Black", Manufacturer="Wurth Elektronik", Supplier Part Number 1=732-2678-ND
TP1 TP2 TP5: library part CMP-0055153-2, "Test Point, Compact, SMT", Manufacturer="Keystone Electronics", Supplier Part Number 1=36-5016TR-ND
TP3: library part CMP-0003719-1, "Testpoint", Manufacturer="Texas Instruments"
TP4 TP7 TP8 TP10 TP11 TP12 TP13 TP14 TP15 TP16 TP17: library part CMP-0055147-2, "Test Point, Multipurpose, Red, TH", Color=Red, Manufacturer="Keystone Electronics", Supplier Part Number 1=36-5010-ND
TP6: library part CMP-0055152-2, "Test Point, Miniature, SMT", Manufacturer="Keystone Electronics", Supplier Part Number 1=36-5015TR-ND
TP9: library part CMP-0055148-2, "Test Point, Multipurpose, Black, TH", Color=Black, Manufacturer="Keystone Electronics", Supplier Part Number 1=36-5011-ND
U1: library part CMP-0121932-1, "Automotive 65-V H-Bridge Driver with Integrated Current Sense and Diagnostics", Manufacturer="Texas Instruments", Max Supply Voltage=65V, Min Supply Voltage=3V, Nominal Supply Current=3mA, Operating Temperature Range="-40°C to +150°C", Switching Frequency=0-100kHz
U2: library part CMP-0090815-1, "LDO, Fixed Output, Dual, 3.3V, 10/12/15V, 50mA, Precision Enable, Power-Good, HVSSOP10", Dropout Voltage=200/800mV, Manufacturer="Texas Instruments", Max Supply Voltage=85V, Min Supply Voltage=4V, Nominal Supply Current=100uA, Operating Temperature Range="-40°C to +125°C", Output Voltage=3.3/10/12/15V
U3: library part CMP-0365-00685-2, "16 MHz Mixed Signal Microcontroller with 16 KB Flash, 512 B SRAM and 24 GPIOs, -40 to 85 degC, 28-pin SOP (PW), Green (RoHS & no Sb/Br)", Frequency(MHz)=16, Manufacturer="Texas Instruments", Temp Sensor=Yes
U4: library part CMP-0079180-1, "Low Iq Always ON Smart Diode Controller, DBV0006A (SOT-23-6)", Alternate Manufacturer="Texas Instruments", Alternate PartNumber=LM74700QDBVRQ1
U5: "16-Bit Ultra-Low-Power Microcontroller, 128KB Flash, 8KB RAM, USB, 12Bit ADC, 2 USCIs, 32Bit HW MPY, RGC0064B (VQFN-64)", Alternate Manufacturer="Texas Instruments", Alternate PartNumber=MSP430F5528IRGCR, Frequency(MHz)=25, Operating Temperature Range="-40 to 85 C", PartNumber=MSP430F5528IRGCT, Rating=Catalog, Temp Sensor=Yes
U6: library part CMP-0036330-5, "Single Output High PSRR LDO, 500 mA, Fixed 3.3 V Output, 2.7 to 6.5 V Input, with Low IQ, 6-pin SON (DRV), -40 to 125 degC, Green (RoHS & no Sb/Br)", Manufacturer="Texas Instruments"
U7: library part CMP-0043099-3, "Low-Capacitance 2-Channel +/-15kV ESD Protection Array for High-Speed Data Interfaces, DRY0006A (USON-6)", Breakdown Voltage(Min)(V)=11, IO Capacitance(Typ)(pF)=1.5, IO Leakage Current(nA)=1, Manufacturer="Texas Instruments", Operating Temperature Range="-40 to 85 C", Rating=Catalog
Y1: library part CMP-0085483-1, "Oscillator, 4 MHz, 700 ppm, 39 pF, SMD", Frequency_Fixed=4MHz, Frequency Tolerance="700 ppm", Load Capacitance="39 pF", Manufacturer=MuRata
ZZ1: library part CMP-0003616-3
ZZ2: library part CMP-0077236-1
ZZ3: library part CMP-0077237-1
ZZ4: library part CMP-0077238-1

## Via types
v1: diameter 19.68, hole 13.78, Top Layer to Bottom Layer, tented both sides, 714 vias
v2: diameter 19.68, hole 7.87, Top Layer to Bottom Layer, 20 vias
v3: diameter 19.68, hole 7.87, Top Layer to Bottom Layer, tented both sides, 19 vias

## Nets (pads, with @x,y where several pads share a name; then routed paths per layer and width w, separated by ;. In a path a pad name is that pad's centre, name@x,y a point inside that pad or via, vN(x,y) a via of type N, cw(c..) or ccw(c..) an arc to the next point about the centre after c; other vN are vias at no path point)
3V3_LDO: C5.1 J16.3 U2.1 | length 1273.2
  Top Layer w12: v1(1580,2020) 1580,1996.81 C5.1@1586.59,1990.22 ; C5.1@1586.38,1990 1586.38,1959.62 U2.1@1615,1931
  Bottom Layer w10: J16.3@916,2779 916,2631.86 1060.93,2486.93 1082.53,2486.93 1127.71,2441.75 1127.71,2320.15 1172.89,2274.97 1383.14,2274.97 1541.56,2116.55 1541.56,2106.87 1580,2068.43 v1(1580,2020)
3V3_MCU: C17.1 C18.1 D7.2 J7.10 J16.1 R18.2 R21.1 R22.1 R24.1 R30.1 R67.1 R68.1 R69.1 R73.2 U3.1 | length 2863.3
  Top Layer w6: R73.2@138.24,2303 142.18,2303 153.99,2291.19 v1@153.99,2260.01 ; R18.2@590.55,2149.61 591.54,2149.61 626.38,2114.76 626.38,2107.62 v1(629,2105) ; v1(615.74,1716.54) 615.74,1691.33 D7.2@625.43,1681.64
  Top Layer w10: v1(488,2165) 490.62,2165 500.93,2175.31 522.31,2175.31 R68.1@534,2187 ; v1(741.38,2196.38) 743.23,2194.52 743.23,2182.95 756.97,2169.21 756.97,2160.35 759.84,2157.48 U3.1@759.84,2035.43 ; C18.1@769.9,2160.65 1018.78,2409.53 1018.78,2679.39 J16.1@1118.47,2779.08
  Bottom Layer w10: R21.1@138,1763 138,1713.95 174.57,1677.37 174.57,1477.06 143,1445.49 R22.1@143,1444.5 ; R21.1@140,1767.01 R67.1@251,1767.01 312.47,1767.01 313.18,1767.72 R69.1@374.65,1767.72 ; R22.1@140.42,1443.9 362.6,1443.9 R30.1@374.89,1456.19 ; J7.10@348.4,2463.8 352.02,2460.19 352.02,2277.27 463.16,2166.13 486.87,2166.13 v1(488,2165) 490.54,2165 521.92,2196.38 v1(741.38,2196.38) ; R69.1@375.79,1767.72 568.05,1767.72 v1@620.76,1715
  other v1: 153,2265
DRVOFF: J4.23 TP17.1 U1.8 | length 2316.9
  Top Layer w6: U1.8@2422.24,1050.2 2424.17,1052.12 2479.12,1052.12 2629,1202 2629,1715.41 v1(2629.59,1716)
  Top Layer w10: J4.23@1185.04,1531.5 1196.85,1543.31 TP17.1@1322.83,1543.31
  Bottom Layer w6: TP17.1@1318.9,1523.62 1448.25,1652.98 2565.98,1652.98 2629,1716 v1(2629.59,1716)
DRVOFF_MCU: J4.24 U3.26 | length 557.4
  Top Layer w6: U3.26@709.65,1809.06 708.66,1808.07 708.66,1688.98 870.08,1527.56 J4.24@1078.74,1527.56
EN/IN1: J4.21 TP16.1 U1.9 | length 2320.9
  Top Layer w6: U1.9@2424.17,1071.8 2474.16,1071.8 2608.87,1206.51 2608.87,1732.48 2621.18,1744.78 v1(2621.18,1747.07)
  Top Layer w10: J4.21@1192.91,1629.92 1236.22,1629.92 TP16.1@1322.83,1716.54
  Bottom Layer w6: 1346.47,1666.85 2540.96,1666.85 v1(2621.18,1747.07)
  Bottom Layer w10: TP16.1@1322.83,1716.54 1322.83,1688.98 1346.46,1665.35
EN/IN1_MCU: J4.22 U3.27 | length 485.2
  Top Layer w6: U3.27@735.24,1809.06 736.22,1808.07 736.22,1692.91 799.21,1629.92 J4.22@1078.74,1629.92
EZFET_AVBUS: C21.1 R32.1 R35.2 U5.1 | length 427.3
  Top Layer w6: C21.1@391.23,3586.85 391.23,3586.69 417.96,3559.95 ; C21.1@402.23,3584.85 402.23,3666.67 R32.1@403.05,3667.49 ; 418.96,3559.95 418.96,3429.04 U5.1@543.02,3304.97
EZFET_AVCC2ADC: C24.1 R36.1 R38.2 U5.2 | length 300.7
  Top Layer w6: R36.1@392.34,3542.49 392.34,3500.74 392.34,3426.83 U5.2@523.17,3296
EZFET_D_N: C49.1 R43.2 U5.52 | length 658.4
  Top Layer w6.3: U5.52@737.17,3139 740.65,3139 751.51,3149.86 854.92,3149.86 859.13,3145.65 864.35,3145.65 879.08,3160.38 883.16,3164.46 1102.24,3383.55 1102.24,3473.56 ; R43.2@1086.38,3523.86 C49.1@1086.38,3488.43 ; C49.1@1086.38,3488.43 1101.24,3473.56 ; C49.1@1086.38,3488.43 1101.24,3473.56 ; C49.1@1086.38,3488.43 1101.24,3473.56
EZFET_D_P: C50.1 R44.2 R45.1 R46.2 U5.50 | length 646.3
  Top Layer w6.3: U5.50@769.15,3114.05 769.63,3114.05 780.56,3124.98 866.73,3124.98 875.06,3133.31 880.28,3133.31 885.88,3127.7 891.85,3127.7 R45.1@893.18,3129.04 ; R45.1@899,3123 928.36,3152.36 921.68,3159.03 911.23,3169.48 1118.54,3376.8 1118.54,3473.56 ; 1118.04,3474.06 1132.41,3488.43 R44.2@1132.41,3523.86
EZFET_LED0: R33.2 U5.20 | length 338.5
  Top Layer w10: R33.2@145.25,3204.99 145.25,3155.76 288.66,3012.35 361.23,3012.35 U5.20@371.06,3022.18
EZFET_LED1: R34.2 U5.21 | length 407.7
  Top Layer w10: R34.2@93.28,3204.99 127.37,3170.9 127.37,3140.63 279.92,2988.08 ; 281.12,2986.61 364.54,2986.61 378.83,3000.9 378.83,3001.72 384.98,3007.87 U5.21@384.98,3008.26
EZFET_PUR: R45.2 U5.51 | length 284.3
  Top Layer w6: v1(730,3097) 732.62,3099.62 732.62,3105.35 U5.51@755.23,3127.97 ; v1(899,3086) 900.24,3087.24 912.4,3087.24 917.35,3092.19 932.18,3092.19 R45.2@938.37,3086
  Bottom Layer w10: v1(730,3097) 771,3056 869,3056 v1(899,3086)
EZFET_RST: C23.1 J5.11 R37.1 U5.64 | length 1170.7
  Top Layer w10: C23.1@92,3732 93.73,3730.27 R37.1@141.47,3730.27 R37.1@142.47,3730.27 ; J5.11@311.02,3938.87 260.15,3888 148.33,3888 142.47,3882.14 R37.1@142.47,3730.27 ; 428.66,3729.34 505,3653 505,3412.02 518.47,3398.55 584.17,3332.85 584.17,3318.8 U5.64@574.28,3308.92 ; 429.13,3730.27 R37.1@142.47,3730.27
EZFET_TCK: J5.7 U5.63 | length 860.5
  Top Layer w10: J5.7@511.02,3938.87 463.58,3891.43 399.44,3891.43 365.66,3857.65 365.66,3820.08 392.23,3793.51 420.49,3793.51 525.87,3688.13 525.87,3416.42 602.04,3340.26 602.04,3307.4 U5.63@590.2,3295.56
EZFET_TDI: J5.3 U5.61 | length 814.5
  Top Layer w10: U5.61@616.04,3267.16 637.79,3288.91 637.79,3380.89 561.62,3457.06 561.62,3809.15 565.66,3813.2 565.66,3862.48 591.07,3887.88 660.03,3887.88 J5.3@711.02,3938.87
EZFET_TDO: J5.1 U5.60 | length 877.6
  Top Layer w10: U5.60@631.96,3253.8 655.66,3277.51 655.66,3388.3 579.49,3464.46 579.49,3767.75 593.44,3781.7 621.65,3781.7 665.66,3825.71 665.66,3859.63 693.91,3887.88 760.03,3887.88 J5.1@811.02,3938.87
EZFET_TEST: J5.8 U5.59 | length 1027.6
  Top Layer w10: v1(611,3211) 613.62,3211 629.62,3227 631,3227 U5.59@641,3237
  Bottom Layer w10: J5.8@511.02,3838.87 372.15,3700 322.56,3700 249,3626.44 249,3497 571.58,3174.42 572.42,3174.42 v1@608,3210
EZFET_TMS: J5.5 U5.62 | length 829.9
  Top Layer w10: U5.62@602.12,3281.08 619.91,3298.88 619.91,3370.09 543.75,3446.25 543.75,3742 465.66,3820.08 465.66,3862.86 495.68,3892.88 565.03,3892.88 J5.5@611.02,3938.87
EZFET_UARTRXD: R49.1 U5.38 | length 265.1
  Top Layer w10: R49.1@633.78,2722.78 710.85,2799.85 710.85,2808.14 680.88,2838.11 680.88,2871.03 685.09,2875.24 685.09,2883.53 U5.38@643.88,2924.74
EZFET_UARTTXD: R50.1 U5.37 | length 243.2
  Top Layer w10: R50.1@566,2704 641.84,2779.84 641.84,2898.94 U5.37@629.96,2910.82
EZFET_USB_Shield: C44.1 J6.6 J6.7 J6.8 J6.9 J6.10 J6.11 R51.2 | length 298.1
  Top Layer w10: J6.10@929,3937.3 J6.10@929,3951 ; J6.11@985,3869 J6.11@985,3881.3 ; J6.6@1178.9,3869 1189.11,3858.79 1227.59,3858.79 1297.68,3788.69 1350.34,3788.69 R51.2@1359.04,3780 ; C44.1@1357.29,3722.82 R51.2@1357.29,3777.94
EZFET_V18: C25.1 U5.55 | length 100.1
  Top Layer w10: U5.55@704.57,3188.27 711.71,3195.41 713.72,3197.42 720.92,3197.42 735.71,3212.22 735.71,3232.61 735.45,3232.87 735.45,3241.16 C25.1@756.66,3262.36
EZFET_VBUS: C19.1 C20.1 C28.1 C29.1 C30.1 C45.1 L2.2 R32.2 U5.53 U6.4 U6.6 U7.1 | length 1368.8
  Top Layer w6: U6.4@940.4,3567.21 U6.4@940.4,3567.21 ; v1@961.02,3615.09 v1@962,3614.11
  Top Layer w10: v1(325.17,3670.49) R32.2@355.43,3670.49 ; U5.53@727.42,3153.18 792.81,3218.57 794.28,3217.09 803.91,3217.09 813.15,3226.33 C19.1@862.43,3226.33 ; v1(835,3613) 861.77,3613 C28.1@861.87,3613.09 ; C19.1@867.45,3221.31 v1@878.92,3209.84 ; v1@873.5,3567.21 U6.6@889.22,3567.21 ; C29.1@904.31,3613.11 904.31,3617.05 915.52,3628.27 924.46,3628.27 v1(926.31,3630.12) ; U6.4@940.4,3567.21 v1@956.15,3567.17 ; C30.1@948.35,3613.09 950.26,3615 960.92,3615 v1@961.02,3615.09 ; v1(1000,3618.11) C45.1@1029.2,3618.11 ; v1@1057.09,3614.22 1071.87,3629 1090.34,3629 1091,3629.66 U7.1@1091,3631
  Top Layer w15: v1@980.2,3741.72 993.59,3728.34 1024.67,3728.34 L2.2@1026,3727.01
  Bottom Layer w10: v1(325.17,3670.49) 776.83,3670.49 v1@835.2,3612.11 ; v1(885,3206) 884.26,3206.74 884.26,3267.26 957.15,3340.15 957.15,3516.38 ; 956.15,3516.38 959.18,3519.41 959.18,3538.23 956.15,3541.26 v1@956.15,3567.17
  other v1: 867,3567 958,3567 1056,3614 965,3615 977,3744
EZFET_VCC: C31.1 C33.1 C34.1 C35.1 C36.1 C37.1 J7.9 R36.2 R37.2 R41.1 R42.1 U5.11 U5.15 U5.40 U6.1 | length 677.6
  Top Layer w10: R37.2@141.47,3683.02 143.44,3684.99 v1@169.88,3684.99 ; C34.1@281.9,3196.79 285.6,3196.79 308.16,3174.23 v1(308.16,3147.19) ; v1@307.09,3147.93 325.56,3129.45 327.42,3129.45 342.83,3114.05 U5.15@343.22,3114.05 ; v1@314.17,3542.49 R36.2@344.09,3542.49 ; v1@352.76,3247.97 356.7,3247.97 364.77,3256.04 C36.1@364.77,3277.51 ; v1@380.55,3188.45 U5.11@394.27,3174.73 ; v1(384,3231) 385.85,3232.85 385.85,3255.87 403.55,3273.57 C35.1@403.55,3277.51 ; U5.40@671.72,2952.58 689,2935.29 713.24,2935.29 C37.1@746.65,2901.89 773.68,2874.85 784.15,2874.85 v1@785,2874 ; v1(690,3704) 690.52,3703.48 720.95,3703.48 R41.1@721.47,3702.96 R42.1@762.85,3702.96 ; C33.1@767,3517.38 767,3503.36 781.54,3488.82 v1@793.35,3488.82 ; v1(795,3488) 795.41,3488.41 843.4,3488.41 845.43,3490.44 846.23,3489.63 888.41,3489.63 U6.1@889.22,3490.44 ; C31.1@821.8,3513.18 v1@845.43,3489.56
  other v1: 786,2873 380,3190 349,3214 352,3247 844.06,3488.82 886,3490 313,3542 171,3686
EZFET_Vcore: C26.1 U5.17 | length 189
  Top Layer w10: C26.1@203.16,3200.72 209.97,3193.91 209.97,3183.27 U5.17@329.3,3063.94
EZFET_VREF: C22.1 U5.9 | length 99
  Top Layer w10: U5.9@426.73,3197.56 412.04,3212.25 412.04,3240.23 443.31,3271.5 C22.1@443.31,3277.51
EZFET_VUSB: C27.1 U5.54 | length 161.2
  Top Layer w10: U5.54@713.47,3169.72 713.86,3169.72 721.67,3177.53 724.23,3177.53 726.25,3179.55 728.32,3179.55 760.44,3211.67 760.44,3226.68 793.34,3259.58 824.71,3259.58 C27.1@827.49,3262.36
EZFET_XT2IN: U5.57 Y1.1 | length 195.5
  Top Layer w10: U5.57@671.72,3211.48 690.28,3230.05 690.28,3231.33 718.01,3259.05 718.44,3259.05 746.87,3287.49 746.87,3347.64 745.79,3348.72 745.79,3357.53 Y1.1@758.28,3370.02
EZFET_XT2OUT: U5.58 Y1.3 | length 272
  Top Layer w10: U5.58@657.8,3225.4 729,3296.61 729,3340.24 663.79,3405.45 Y1.3@663.79,3440.88
GND: C1.2 C2.2 C5.2 C6.1 C7.1 C8.1 C9.2 C10.2 C11.1 C12.1 C13.1 C14.2 C15.2 C16.2 C17.2 C18.2 C19.2 C20.2 C21.2 C22.2 C23.2 C24.2 C25.2 C26.2 C27.2 C28.2 C29.2 C30.2 C31.2 C32.2 C33.2 C34.2 C35.2 C36.2 C37.2 C38.1 C39.1 C40.2 C41.2 C42.1 C43.2 C44.2 C45.2 C47.1 C48.1 C49.2 C50.2 C52.2 C53.2 C59.2 C70.2 D4.1 D5.1 D6.1 D8.2 J4.1 J4.2 J5.9 J7.13 J7.14 J14.1 J15.1 J15.2 J17.1 J18.1 J18.2 L3.2 R2.1 R5.1 R6.1 R7.1 R8.1 R9.1 R10.1 R11.1 R12.1 R13.2 R15.2 R17.2 R19.1 R20.1 R23.2 R29.2 R31.2 R35.1 R38.1 R40.2 R46.1 R51.1 R53.1 R54.1 R55.1 R56.1 R57.1 R58.1 R59.1 R60.2 R61.1 R62.1 R63.1 R64.1 R65.1 R66.1 R70.2 R71.2 R72.2 S1.3 S1.4 TP9.1 U1.6 U2.2 U2.4 U2.5 U2.7 U2.11 U3.28 U4.2 U5.14 U5.16 U5.39 U5.49 U5.56 U5.65 U6.3 U6.5 U6.7@914.81,3528.82 U7.4 Y1.2 | length 2731.1
  Top Layer w10: S1.4@87,1692 99.12,1679.88 v1(139.94,1679.88) ; S1.3@88,2041 88,2024.2 117.35,1994.85 128.15,1994.85 v1(130,1993) ; C26.2@203.16,3247.97 203.16,3278.16 v1@217,3292 ; v1(279.53,3350.39) 279.53,3298.47 C34.2@285,3293 ; U5.16@329.3,3100.13 329.69,3100.13 339.51,3090.3 371.9,3090.3 v1@373.28,3091.69 ; U5.14@357.14,3127.97 357.14,3127.58 373.25,3111.46 373.25,3094.73 v1@375.63,3092.35 ; C35.2@403.55,3324.75 439.75,3324.75 C22.2@444,3329 ; v1(621.4,2976.2) 621.4,2975.45 658.95,2937.89 658.95,2936.15 U5.39@659.54,2935.57 ; U5.39@662.61,2933.85 715.79,2880.67 715.79,2871.03 C37.2@713.24,2868.48 ; U5.56@685.63,3197.56 686.02,3197.56 710.38,3221.92 v1(713,3221.92) ; U3.28@760.83,1809.06 760.83,1758.89 767.67,1752.05 v1(767.67,1749.43) ; C33.2@767,3564.62 772.62,3559 822,3559 822,3556.69 836.68,3542 888.32,3542 893.16,3537.16 v2(893.16,3528.82) ; U5.49@783.07,3100.13 787.69,3104.75 822.97,3104.75 v1(849,3078.72) ; v1(790,3170.73) 791.85,3172.58 802.38,3172.58 817.58,3187.78 829.22,3187.78 C20.2@835,3182 ; C17.2@807.09,2106.3 808.97,2104.41 808.97,2081.46 v1(818.69,2071.74) 818.69,2072.16 834.57,2088.04 834.57,2139.89 833.58,2140.87 833.58,2146.73 C18.2@822.83,2157.48 ; U6.5@914.81,3567.21 U6.7@914.81,3528.82 940.4,3503.23 U6.3@940.4,3490.44 ; U7.4@1130.61,3653.16 1204.54,3653.16 1218.38,3667 v1@1219,3667 ; L3.2@1156,3725.01 1211.29,3725.01 1217.15,3719.15 1217.15,3665.85 v1@1219,3664 ; v1(1566,1853) 1567.85,1854.85 1575.29,1854.85 1580.03,1859.59 ; U2.2@1589,1910 1581.87,1910 1571.97,1900.1 1571.97,1867.65 1580.03,1859.59 ; U2.5@1594,1851 1593.46,1851.54 1588.08,1851.54 1580.03,1859.59 ; U2.4@1597,1870 1590.43,1870 1580.03,1859.59 ; C11.1@1678.5,2320 1674.03,2315.53 1674.03,2285.88 1667.27,2279.12 1667.27,2256.49 v1(1665.41,2254.64) 1668.03,2254.64 1671.85,2250.83 1690.61,2250.83 C12.1@1700.81,2240.63 ; v1@1766,1792 1766,1772.49 1819,1719.49 R19.1@1819,1718.5 1826.5,1711 D8.2@1877,1711 ; U2.7@1806,1870 1806.59,1869.41 1819.35,1869.41 1832.85,1855.9 v1(1832.85,1855.49) ; C59.2@2536.92,1205.92 2536.92,1207.79 2553.13,1224 v1(2553.13,1225.87)
  Top Layer w20: v1(1634,3316) 1690.62,3316 1722.6,3284.02 1722.6,3256.82 U4.2@1725.37,3254.04
  Bottom Layer w10: v1(130,1993) 130,1973.69 R70.2@153.7,1973.69 ; R70.2@140,1959 153.7,1972.7 R70.2@153.7,1973.69 ; v1@141.66,1677.34 143,1676 R23.2@143,1645.5 ; R71.2@248.31,1956.69 R72.2@374.65,1956.69 ; R71.2@253,1957 253,1957.98 239.3,1971.69 238.31,1971.69 233,1977 159.56,1977 156.24,1973.69 R70.2@153.7,1973.69 ; v2(589.03,3010.49) 589.03,3009.52 621.4,2977.16 v1(621.4,2976.2) ; v1(790,3170.73) 790,3137.72 v1(849,3078.72) ; v1(1566,1853) 1626,1793 1768.62,1793 1773.46,1797.84 1775.2,1797.84 v1(1832.85,1855.49)
  other v1: 350,100 950,100 2259.84,161.42 2318.9,161.42 2389.76,161.42 2354.33,192.91 2318.9,228.35 2389.76,228.35 2354.33,259.84 2318.9,287.4 2389.76,287.4 2354.33,322.83 2259.84,358.27 2318.9,358.27 2389.76,358.27 2444.88,358.27 2354.33,389.76 2318.9,425.2 2389.76,425.2 2354.33,456.69 2318.9,484.25 2389.76,484.25 2354.33,507.87 2259.84,543.31 2318.9,543.31 2389.76,543.31 2444.88,543.31 2354.33,574.8 2259.84,598.43 2444.88,598.43 2318.9,610.24 2389.76,610.24 2354.33,641.73 2318.9,669.29 2389.76,669.29 161.42,673.23 358.27,673.23 744.09,673.23 937.01,673.23 1318.9,673.23 1503.94,673.23 539.37,677.17 1118.11,692.91 2267.72,728.35 2326.77,728.35 2385.83,728.35 2440.95,728.35 2267.72,783.46 2326.77,783.46 2385.83,783.46 2440.95,783.46 100,800 2267.72,834.65 2326.77,834.65 2385.83,834.65 2440.95,834.65 2267.72,891.73 2460.35,896.73 1488.19,897.64 2362.2,1177.17 2314.96,1200.79 2402.16,1208.08 2270,1232 2446.75,1252.67 2314.96,1271.65 2409.45,1271.65 2272,1307 2459.21,1311.02 2314.96,1342.52 2409.45,1342.52 2362.2,1362.2 2271,1376 566.93,1385.83 755.91,1385.83 956.69,1385.83 1157.48,1385.83 1358.27,1385.83 161.42,1389.76 503.94,1444.88 578.74,1444.88 948.82,1582.68 1506,1618 1011.81,1677.17 210.3,1683.88 3107,1698 1460.63,1704.72 3031.5,1704.72 896.14,1762.97 3047.24,1767.72 2925.2,1771.65 1876,1778 2854.33,1787.4 1766,1793 2800,1800 1429.13,1817.56 3043.31,1870.08 1023.62,1874.02 2897.64,1874.02 2791.34,1885.83 2850,1950 2950,1950 2550,2000 3000,2050 3100,2050 1220.47,2086.61 2550,2100 1564.28,2116.28 3102.24,2127.35 2700,2150 2950.89,2149.96 1213.97,2184.87 2550,2200 2600,2250 3000,2250 3100,2250 2901.09,2255.96 2792.27,2256.82 3100,2350 2796.98,2351.43 2896.98,2351.43 2996.98,2351.43 1213,2382 2850,2400 3111.23,2416.93 1583,2438 3000,2450 2550,2500 3108.87,2503.55 961.23,2527.69 3000,2550 2550,2600 2647.85,2602.15 2700,2650 2800,2650 2900,2650 3000,2650 3100,2650 2550,2700 2650,2700 1148.12,2704.34 1691.95,2712.57 1649.48,2750.45 2700,2750 2800,2750 2900,2750 3000,2750 3100,2750 1632,2811 2559.06,2834.65 2637.8,2834.65 1623,2840 3000,2850 3100,2850 2519.69,2874.02 2598.43,2874.02 2677.17,2874.02 2768.87,2875.55 1623,2878 2922.26,2877.56 2716.54,2913.39 2874.02,2913.39 2952.76,2913.39 2519.69,2952.76 2677.17,2952.76 2834.65,2952.76 2913.39,2952.76 2992.13,2952.76 1615,2982 2559.06,2992.13 2637.8,2992.13 2716.54,2992.13 2795.28,2992.13 2874.02,2992.13 2952.76,2992.13 3031.5,2992.13 837.65,2995.84 1621,3016 2519.69,3031.5 2598.43,3031.5 2677.17,3031.5 2755.91,3031.5 2834.65,3031.5 2913.39,3031.5 2992.13,3031.5 1660,3067 2637.8,3070.87 2716.54,3070.87 2795.28,3070.87 2874.02,3070.87 3031.5,3070.87 1629,3077 375.1,3091.96 2677.17,3110.24 2755.91,3110.24 2834.65,3110.24 2929.13,3110.24 2976.38,3118.11 2716.54,3149.61 2874.02,3149.61 1015.75,3153.54 2960.63,3161.42 2681.1,3188.98 2755.91,3188.98 2834.65,3188.98 2862.2,3208.66 1022,3218 2716.54,3228.35 2795.28,3228.35 2755.91,3267.72 2641.73,3279.53 2700.79,3283.46 216,3292 944.64,3295.52 850.39,3326.77 914.48,3329.61 835,3391 2900,3400 285,3412 748.03,3440.94 1074.8,3448.82 1220.47,3448.82 467,3450 1550,3450 1039.37,3480.32 1255.91,3480.32 223,3485 459,3488 138,3490 350.39,3499.99 2700,3500 2800,3500 2900,3500 3050,3500 1455,3511 1350,3550 1512,3587 354.33,3590.55 1250,3600 2700,3600 2800,3600 2900,3600 3050,3600 196,3633 354.33,3633.86 1609,3649 1219,3665 2700,3700 2800,3700 2900,3700 3050,3700 1300,3750 1576,3778 2900,3800 3050,3800 3139.57,3800 2700,3900 2800,3900 2900,3900 2700,4000 2800,4000 2900,4000
  other v2: 1674.41,1838.82 1725.59,1838.82 1674.41,1890 1725.59,1890 1674.41,1941.18 1725.59,1941.18 523.33,3010.49 556.18,3043.34 484.64,3049.18 627.73,3049.18 517.49,3082.03 594.88,3082.03 484.64,3114.88 627.73,3114.88 556.18,3120.73 523.33,3153.58 589.03,3153.58 936.47,3528.82
  other v3: 2289.37,877.95 2318.9,877.95 2358.27,877.95 2397.64,877.95 2427.17,877.95 2289.37,903.54 2427.17,903.54 2318.9,911.42 2358.27,911.42 2397.64,911.42
ID0: R22.2 R23.1 U3.14 | length 958.6
  Top Layer w6: v1(415,2103.39) 415,2101.65 428.15,2088.5 428.15,2044.85 U3.14@429.58,2043.43
  Bottom Layer w8: R22.2@141,1507 R23.1@141,1582.5 ; R23.1@141,1585.49 79,1647.49 79,1995 187.39,2103.39 v1(415,2103.39) ; R23.1@143,1582.5 R23.1@143,1583.49
ID1: R21.2 R70.1 U3.9 | length 613.7
  Top Layer w6: v1(555.12,2082.68) 555.12,2047.24 U3.9@559.06,2043.31
  Bottom Layer w6: R21.2@138,1826 138,1894.01 R70.1@140,1896.01 199.24,1896.01 231.67,1928.44 397.85,1928.44 465.65,1996.24 465.65,2012.26 536.06,2082.68 v1(555.12,2082.68)
ID2: R67.2 R71.1 U3.8 | length 576.5
  Top Layer w6: U3.8@581.69,2041.34 581.69,1993.11 v1@582.68,1992.13
  Bottom Layer w6: R67.2@251.01,1829.01 280.67,1799.35 397.76,1799.35 404.22,1805.81 404.22,1806.52 463.23,1865.53 463.23,1928.06 531.23,1996.06 v1(582.68,1996.06) ; R67.2@252,1830 253,1831 R71.1@253,1894.01
ID3: R69.2 R72.1 U3.13 | length 279.8
  Top Layer w6: U3.13@452.76,2043.31 452.76,2004.24 v1(479,1978)
  Bottom Layer w6: R69.2@374.65,1830.71 373.65,1831.71 373.65,1892.7 374.65,1893.7 374.65,1894.68 390.35,1910.39 411.39,1910.39 v1(479,1978)
ID4: R24.2 R29.1 U3.15 | length 403.7
  Top Layer w10: v1(286.46,1611.5) 304.21,1629.26 304.21,1681.92 359.16,1736.87 407.11,1736.87 428.15,1757.91 U3.15@428.15,1809.06
  Bottom Layer w10: R29.1@252.79,1581.19 R29.1@258.09,1581.19 ; R24.2@258.09,1511.69 R29.1@258.09,1581.19 ; v1(286.46,1611.5) 284.6,1609.65 280.26,1609.65 258.09,1587.47 R29.1@258.09,1581.19
ID5: R30.2 R31.1 U3.19 | length 449
  Top Layer w10: U3.19@530.51,1809.06 530.51,1766.5 552.64,1744.37 v1@552.64,1742.13
  Bottom Layer w10: R30.2@375.18,1519.69 375.38,1519.88 R31.1@375.38,1591.17 ; R31.1@378.27,1591.17 384.37,1591.17 389.08,1595.87 389.08,1601.98 398.72,1611.62 399.41,1611.62 406.95,1619.16 406.95,1619.85 415.24,1628.14 415.24,1727.96 431.26,1743.98 v1(553.87,1743.98)
IPROPI: C42.2 C53.1 J2.2 J2.4 J2.6 J2.8 J2.10 J2.12 J2.14 J2.16 J4.7 TP7.1 U1.2 | length 4760.9
  Top Layer w6: v1(2184.91,1777.35) v1@2187.1,1775.15 ; 2268.63,1086.05 2268.63,1083.28 2278.14,1073.77 2280.11,1071.8 ; U1.2@2282.46,1070.8 U1.2@2293.37,1070.8
  Top Layer w8: 2280.11,1071.8 2281.46,1071.8 U1.2@2282.46,1070.8 ; U1.2@2293.37,1070.8 U1.2@2294.29,1069.88
  Top Layer w10: TP7.1@1515.75,2547.24 1648.76,2547.24 C42.2@1653,2543 ; v1@2187.1,1775.15 2184.91,1772.96 2184.91,1169.77 2268.62,1086.06
  Top Layer w14: C53.1@594.49,838.58 594.49,839.57 688.38,933.46 688.38,981.06 J2.16@706.38,999.06 J2.2@1402.52,999.06 ; J2.2@1406.38,999.06 1452.38,999.06 1550,1096.68 1550,1636.61 1579.34,1665.96 2115.96,1665.96 2126.57,1676.57 v1(2126.57,1773.52)
  Bottom Layer w10: J4.7@1178.74,2329.92 1188.7,2329.92 1215.62,2303 1515.75,2303 ; TP7.1@1515.75,2547.24 1515.75,2303 ; v1(2126.57,1773.52) 2126.57,1772 2125.04,1773.52 1946.95,1773.52 1515.75,2204.73 1515.75,2303 ; v1@2128.09,1773.52 2129.94,1771.67 2147.49,1771.67 2148.59,1770.57 2175.51,1770.57 2182.29,1777.35 v1(2184.91,1777.35)
IPROPI_MCU: J4.8 U3.2 | length 557.9
  Top Layer w10: U3.2@732.28,2039.37 732.28,2019.23 739.09,2019.23 739.09,2008.94 751.97,1996.06 807.09,1996.06 860.01,2048.99 860.01,2076.47 860.7,2077.15 860.7,2115.75 944.21,2199.27 951.23,2199.27 J4.8@1078.74,2326.77
MCU_UARTRXD: J7.8 U3.3 | length 664.4
  Top Layer w6: J7.8@447.81,2463.5 495.06,2510.75 562.39,2510.75 ; 562.77,2510.75 597.42,2476.1 597.42,2337.52 644,2290.94 644,2245.64 703.79,2185.85 703.79,2069.41 703.79,2047.2 U3.3@709.65,2041.34
MCU_UARTTXD: J7.6 U3.4 | length 508.4
  Top Layer w6: J7.6@550.17,2463.5 550.17,2361.14 616,2295.32 616,2221.3 638.64,2198.66 643.61,2198.66 651.73,2206.79 663.23,2206.79 684.1,2185.91 684.1,2122.31 678.2,2116.4 678.2,2047.2 U3.4@684.05,2041.34
NetC9_1: C9.1 U2.8 | length 337.5
  Top Layer w10: C9.1@1701.02,1740 1701.02,1804.21 1712.91,1816.1 1825.59,1816.1 1855.57,1846.09 1855.57,1871.9 1837.47,1890 U2.8@1787.52,1890
NetC32_1: C32.1 U6.2 | length 59.9
  Top Layer w10: C32.1@909.89,3437.14 C32.1@910.26,3436.77 ; U6.2@915.81,3490.44 915.81,3431.79 C32.1@916.33,3431.27
NetC47_2: C47.2 J7.1 R47.2 | length 270.5
  Top Layer w6: J7.1@748.4,2563.8 813.8,2563.8 829.19,2579.19 856.19,2579.19 C47.2@865,2588
  Top Layer w10: J7.1@748.4,2563.8 780,2595.4 780,2686.99 779.81,2687.18 779.81,2694.21 R47.2@780,2694.4
NetC48_2: C48.2 J7.3 R48.2 | length 373
  Top Layer w6: v1(813,2520) 816.7,2520 825.89,2529.19 850.19,2529.19 C48.2@859,2538 C48.2@861,2540
  Top Layer w10: J7.3@671,2571.61 660.98,2581.62 660.98,2587.13 674.62,2600.76 674.62,2670.25 682.81,2678.44 R48.2@682.81,2687.78
  Bottom Layer w6: J7.3@648.4,2563.8 697.22,2514.99 698.88,2513.32 702.5,2513.32 742.17,2520.33 cw(c959.63,1289.55) 742.85,2520.45 794.93,2520.45 797.33,2520.56 cw(c814.24,2137.11) v1@814.24,2520.93
NetC51_1: C51.1 U4.1 | length 117.3
  Top Layer w20: U4.1@1761.81,3254.92 1761.81,3262.8 1784.06,3285.05 C51.1@1862,3285.05
NetD1_1: D1.1 R2.2 | length 60.7
  Top Layer w10: R2.2@540.94,1539.37 540.94,1594.49 D1.1@544.87,1598.43
NetD2_1: D2.1 R3.2 | length 142.8
  Top Layer w6: R3.2@1503.74,2126.18 1511.75,2126.18 1604.26,2218.69 D2.1@1608.19,2218.69
NetD3_1: D3.1 Q2.3 | length 351.2
  Top Layer w10: Q2.3@1940,1780.63 1940,1735.01 1938.93,1733.94 1938.93,1701.03 1947.84,1692.13 2069.71,1692.13 2103.25,1725.67 2103.25,1804.93 D3.1@2110.28,1811.97
NetD5_2: D5.2 R33.1 | length 138.1
  Top Layer w10: R33.1@145.25,3252.24 145.25,3335.59 D5.2@183.94,3374.28
NetD6_2: D6.2 R34.1 | length 122
  Top Layer w10: R34.1@93.28,3252.24 D6.2@93.28,3374.28
NetD7_1: D7.1 R20.2 | length 67.1
  Top Layer w10: R20.2@625.43,1539.91 615.74,1549.6 615.74,1589.27 D7.1@625.43,1598.96
NetD8_1: D8.1 Q2.1 R4.1 | length 259.1
  Top Layer w10: D8.1@1963.31,1710 1963.31,1752.27 1968.62,1757.58 1968.62,1850.62 Q2.1@1977.4,1859.37 ; Q2.1@1977.4,1859.37 1977.4,1857.4 2007.68,1827.13 2033.19,1827.13 2034.08,1826.23 2046.19,1826.23 2051.95,1820.48 R4.1@2051.95,1808.37
NetF1_2: F1.2 F2.2 J14.2 TP8.1
  other v1: 2446.35,3398.54 2546.35,3398.54 2246.35,3498.54 2346.35,3498.54 2446.35,3498.54 2546.35,3498.54 2246.35,3598.54 2346.35,3598.54 2446.35,3598.54 2546.35,3598.54 2246.35,3698.54 2346.35,3698.54 2446.35,3698.54 2546.35,3698.54 2246.35,3798.54 2446.35,3798.54 2546.35,3798.54 2246.35,3898.54 2346.35,3898.54 2446.35,3898.54 2546.35,3898.54 2246.35,3998.54 2346.35,3998.54 2446.35,3998.54 2550,4000
NetJ1_2: J1.2 S1.1 | length 165.2
  Top Layer w6: J1.2@216.54,2185.04 216.54,2145.67 263.78,2098.43 S1.1@263.78,2039.37
NetJ2_1: J2.1 R5.2 | length 106.5
  Top Layer w20: J2.1@1406.38,1193.94 1406.38,1296.14 R5.2@1409.45,1299.21
NetJ2_3: J2.3 R6.2 | length 111.1
  Top Layer w20: J2.3@1306.38,1193.94 1306.38,1298.5 R6.2@1311.02,1303.15
NetJ2_5: J2.5 R7.2 | length 110.2
  Top Layer w20: J2.5@1206.38,1193.94 1206.38,1300.87 R7.2@1208.66,1303.15
NetJ2_7: J2.7 R8.2 | length 109.2
  Top Layer w20: R8.2@1106.3,1303.15 1106.38,1303.07 R8.2@1106.38,1302.44 J2.7@1106.38,1193.94
NetJ2_9: J2.9 R9.2 | length 111.5
  Top Layer w20: J2.9@1006.38,1193.94 1006.38,1297.72 R9.2@1011.81,1303.15
NetJ2_11: J2.11 R10.2 | length 110.5
  Top Layer w20: J2.11@906.38,1193.94 906.38,1300.08 R10.2@909.45,1303.15
NetJ2_13: J2.13 R11.2 | length 107.9
  Top Layer w20: J2.13@803.15,1196.85 807.09,1200.79 R11.2@807.09,1303.15
NetJ2_15: J2.15 R12.2 | length 110.2
  Top Layer w20: J2.15@706.38,1193.94 706.38,1300.87 R12.2@708.66,1303.15
NetJ4_12: J4.12 R28.1 | length 110.8
  Top Layer w10: R28.1@981.88,2075.24 991.59,2065.53 992.86,2066.8 1015.62,2066.8 J4.12@1066.93,2118.11
NetJ4_14: J4.14 R27.1 | length 113.4
  Top Layer w10: R27.1@984.25,1976.38 1019.69,1976.38 J4.14@1074.8,2031.5
NetJ4_16: J4.16 R26.1 | length 114.2
  Top Layer w10: R26.1@982.65,1885.29 996.36,1898.99 1014.83,1898.99 1021.36,1905.51 1055.12,1905.51 J4.16@1078.74,1929.13
NetJ4_18: J4.18 R25.1 | length 112.8
  Top Layer w10: R25.1@978.27,1800.27 981.81,1803.81 1049.33,1803.81 1075.45,1829.92 J4.18@1078.74,1829.92
NetJ5_2: J5.2 R42.2 | length 118.6
  Top Layer w10: R42.2@765,3739.36 765,3782.56 811.02,3828.58 J5.2@811.02,3838.87
NetJ5_4: J5.4 R41.2 | length 99.5
  Top Layer w10: J5.4@711.02,3838.87 711.02,3754.75 721.77,3744 R41.2@722,3744
NetJ6_1: J6.1 L2.1 | length 58.8
  Top Layer w15: L2.1@1026,3790 1029.41,3793.41 J6.1@1029.41,3847.41
NetJ6_5: J6.5 L3.1 | length 75.2
  Top Layer w15: J6.5@1133.82,3854.06 1134.49,3853.4 1134.49,3822.48 1144.8,3812.17 1144.8,3799.2 L3.1@1156,3788
NetJ7_5: J7.5 R49.2 | length 131.3
  Top Layer w10: J7.5@559.48,2575.73 558.92,2576.3 558.92,2594.81 561.25,2597.14 561.25,2655.25 R49.2@597,2691
NetJ7_7: J7.7 R50.2 | length 139.6
  Top Layer w10: J7.7@469,2562.98 459.98,2572 459.98,2588.13 523.81,2651.95 523.81,2667.9 R50.2@527,2671.09
NetJ10_1: J10.1 R13.1 | length 110.4
  Top Layer w20: R13.1@511.81,1303.15 514.57,1300.39 J10.1@514.57,1193.94
NetJ10_2: J10.2 J10.4 J10.6 J10.8 J10.10 R14.2 | length 1957.1
  Top Layer w6: v1(1424.33,1940.08) 1451.41,1967.15 R14.2@1458.05,1967.15
  Top Layer w10: J10.2@519.69,946.5 J10.2@519.69,972.44
  Top Layer w20: J10.10@116.38,999.06 J10.8@214.57,999.06 J10.6@314.57,999.06 J10.4@414.57,999.06 J10.2@514.57,999.06 514.8,999.06 J10.2@515.75,1000 ; J10.2@516.38,999.06 581.73,999.06 614.17,1031.5 v1(614.17,1236.22)
  Bottom Layer w6: 1055.61,1779.19 1085.98,1779.19 1119.73,1812.94 1119.73,1828.88 1179.78,1888.93 1252.98,1888.93 1304.12,1940.08 v1(1424.33,1940.08)
  Bottom Layer w14: v1(614.17,1236.22) 614.17,1337.75 1055.61,1779.19
NetJ10_3: J10.3 R53.2 | length 113.6
  Top Layer w20: R53.2@413.39,1307.09 414.57,1305.91 J10.3@414.57,1193.94
NetJ10_5: J10.5 R57.2 | length 109.4
  Top Layer w20: J10.5@314.57,1193.94 314.57,1302.76 R57.2@314.96,1303.15
NetJ10_7: J10.7 R61.2 | length 110
  Top Layer w20: R61.2@212.6,1303.15 214.57,1301.18 J10.7@214.57,1193.94
NetJ10_9: J10.9 R64.2 | length 110.7
  Top Layer w20: J10.9@114.57,1193.94 114.57,1299.61 R64.2@118.11,1303.15
NetJ11_1: J11.1 R15.1 | length 126.3
  Top Layer w20: J11.1@1467.87,470.08 1467.87,589.92 R15.1@1472.44,594.49
NetJ11_2: J11.2 J11.4 J11.6 J11.8 J11.10 R16.2 | length 2240.6
  Top Layer w6: v1(1433.07,1748.03) R16.2@1456.69,1771.65
  Top Layer w20: J11.10@1067.87,278.77 1467.87,278.77 1535.43,346.32 v1(1535.43,519.69)
  Bottom Layer w10: v1(1433.07,1748.03) 1403.1,1778 1294,1778 1258,1742 1258,797.12 1532.32,522.8 v1@1535.43,522.8
NetJ11_3: J11.3 R54.2 | length 128.7
  Top Layer w20: J11.3@1367.87,473.65 R54.2@1367.87,602.36
NetJ11_5: J11.5 R58.2 | length 129.7
  Top Layer w20: J11.5@1267.87,473.65 1267.87,599.94 R58.2@1270.29,602.36
NetJ11_7: J11.7 R62.2 | length 128.7
  Top Layer w20: J11.7@1167.87,473.65 R62.2@1167.87,602.36
NetJ11_9: J11.9 R65.2 | length 129.6
  Top Layer w20: J11.9@1067.87,473.65 1067.87,600.31 R65.2@1069.92,602.36
NetJ12_1: J12.1 R17.1 | length 128.7
  Top Layer w20: J12.1@891.99,473.65 R17.1@891.99,602.36
NetJ12_2: J12.2 J12.4 J12.6 J12.8 J12.10 R39.2 | length 2337.8
  Top Layer w6: v1(1374.02,1803.15) 1437.72,1866.85 1452.05,1866.85 R39.2@1456.69,1862.2
  Top Layer w20: J12.10@491.99,278.77 691.99,278.77 890.53,278.77 J12.2@893.7,275.59 ; J12.2@891.99,278.77 940.18,278.77 980.32,318.9 v1(980.32,531.5)
  Bottom Layer w10: v1(980.32,531.5) 983.48,531.5 988.09,536.1 1019.1,536.1 1230,747 1230,1747 1286.15,1803.15 v1(1374.02,1803.15)
NetJ12_3: J12.3 R55.2 | length 129.2
  Top Layer w20: J12.3@791.99,473.65 791.99,601.15 R55.2@793.2,602.36
NetJ12_5: J12.5 R59.2 | length 128.7
  Top Layer w20: J12.5@691.99,473.65 R59.2@691.99,602.36
NetJ12_7: J12.7 R63.2 | length 128.7
  Top Layer w20: J12.7@591.99,473.65 R63.2@591.99,602.36
NetJ12_9: J12.9 R66.2 | length 116.6
  Top Layer w20: J12.9@491.99,470.08 491.99,586.48 R66.2@492.13,586.61
NetJ13_1: J13.1 R40.1 | length 108.6
  Top Layer w20: J13.1@313.01,490.38 R40.1@313.01,599
NetJ13_2: J13.2 J13.4 J13.6 R52.2 | length 2632.9
  Top Layer w6: v1(1416.45,2032.41) 1418.03,2033.98 1439.49,2033.98 R52.2@1464.57,2059.06
  Top Layer w20: J13.6@113.01,277.78 312.77,277.78 J13.2@314.96,275.59 ; J13.2@313.01,277.78 360.46,277.78 401.57,318.9 v1(401.57,511.81)
  Bottom Layer w6: 1024,1796 1024,1833.15 1061.76,1870.91 1077.7,1870.91 1128.74,1921.95 1128.74,1937.89 1179.78,1988.93 1212.71,1988.93 1219.58,1995.81 1294.59,1995.81 1305.4,1985 1369.04,1985 1415.05,2031 v1@1417,2031
  Bottom Layer w10: v1(401.57,511.81) 401.57,1173.57 1024,1796
NetJ13_3: J13.3 R56.2 | length 110.1
  Top Layer w20: J13.3@213.01,490.38 213.01,595.43 R56.2@216.58,599
NetJ13_5: J13.5 R60.1 | length 115.2
  Top Layer w20: R60.1@110.24,590.55 112.6,588.19 J13.5@112.6,476.38
NetQ1_4: Q1.4 U4.5 | length 419.9
  Top Layer w10: U4.5@1724.41,3146.65 1724.41,3138.78 1737.13,3126.06 1737.13,3122.81 1909.94,2950 1963.66,2950 Q1.4@2029.16,3015.5
NetQ2_2: Q2.2 R19.2 | length 117.8
  Top Layer w10: R19.2@1820,1781.5 1820,1782.48 1884.17,1846.65 1891.85,1846.65 1904,1858.8 Q2.2@1904,1860
nFAULT: J4.9 R1.1 R3.1 TP10.1 U1.1 | length 2804.1
  Top Layer w6: v1(1437.01,2188.98) 1440.94,2188.98 R3.1@1464.57,2165.35 ; R3.1@1464.76,2165.16 1535.43,2235.83 R1.1@1535.43,2240.16 ; v1(2211.17,1769) 2211.13,1768.95 2211.13,1468.76 2208.43,1466.07 2208.43,1169.58 2284.5,1093.52 2284.5,1091.49 2286.42,1089.57 U1.1@2294.29,1089.57
  Top Layer w10: J4.9@1196.85,2224.41 1225.31,2252.87 1225.31,2256.18 1243.19,2274.06 1243.19,2588.19 1288.81,2633.81 ; 1287.83,2632.91 TP10.1@1287.83,2710.66
  Bottom Layer w6: J4.9@1173.29,2228.41 1217.86,2228.41 1229.73,2216.54 1252.66,2216.54 1258.39,2220.78 1258.39,2221.11 1296.38,2259.1 1366.89,2259.1 v1(1437.01,2188.98) 1546.97,2079.01 1546.97,1960.71 1545.28,1959.02 1545.28,1844.42 1636.89,1752.81 2194.98,1752.81 v1(2211.17,1769)
nFAULT_MCU: J4.10 U3.16 | length 919
  Top Layer w6: U3.16@453.74,1809.06 453.74,1890.75 511.81,1948.82 832.45,1948.82 865.95,1982.32 865.95,2031.18 875.89,2041.12 875.89,2069.89 876.57,2070.58 876.57,2109.18 942.61,2175.22 1023.87,2175.22 1042.6,2193.94 1066.93,2193.94 J4.10@1066.93,2224.41
nSCS/DIAG: J4.17 R16.1 TP14.1 U1.12 | length 2431.4
  Top Layer w6: R16.1@1502.59,1737.57 1502.69,1737.47 1524.53,1737.47 1533.72,1746.65 v1(1534.05,1746.65) ; U1.12@2377.95,1109.25 2377.95,1129.41 2381.47,1132.92 2437.54,1132.92 2484.29,1179.66 2484.29,1182.59 2521.51,1219.82 2521.51,1223.56 2555,1257.04 2555,1740.64 2547,1748.64 v1(2547,1751)
  Top Layer w10: J4.17@1192.91,1822.83 1266.46,1896.38 1266.46,1905.24 1321.85,1960.63 ; TP14.1@1326.77,2035.43 1326.77,1965.55 1321.85,1960.63 ; v1(1389.76,1913.39) 1342.52,1960.63 1321.85,1960.63
  Bottom Layer w6: v1@1393.7,1909.45 1392.15,1909.45 1389.76,1907.06 1389.76,1890.94 v1(1534.05,1746.65) 1536.81,1746.65 1588.49,1694.98 2502.27,1694.98 2544.38,1737.08 2544.38,1748.38 v1(2547,1751)
nSCS_MCU: R25.2 R68.2 U3.10 | length 625.3
  Top Layer w6: U3.10@530.51,2047.24 530.51,2111.09 R68.2@530.51,2116.01 ; U3.10@531.5,2047.24 536.37,2042.37 536.37,2008.63 575,1970 v1(575,1969.6) ; R25.2@917.24,1800.27 R25.2@926.1,1809.13
  Top Layer w10: v1(866.06,1800.27) 917.24,1800.27 R25.2@921.18,1800.27
  Bottom Layer w6: v1(575,1969.6) 575,1919.32 655.74,1838.58 832.09,1838.58 847.28,1823.39 847.28,1819.05 v1(866.06,1800.27)
nSLEEP: J4.5 TP4.1 U1.3 | length 2579.8
  Top Layer w6: v1(2158,1793.28) 2155.98,1791.26 2147.28,1791.26 2147.28,1766.42 2167,1746.7 2167,1163.88 2278.76,1052.12 2292.37,1052.12 U1.3@2294.29,1050.2
  Bottom Layer w8: J4.5@1178.74,2429.92 1275.92,2429.92 1347.71,2501.71 ccw(c1322.83,2551.18) 1372.31,2526.31 1509,2663 1569.37,2602.63 1569.37,2476.3 1532.62,2439.55 1532.62,2230.38 1966,1797 2062.1,1797 2063.86,1795.24 2156.04,1795.24 v1(2158,1793.28) ; 1508.69,2663 TP4.1@1508.69,2714.6
nSLEEP_MCU: J4.6 U3.17 | length 1136.5
  Top Layer w6: U3.17@479.33,1809.06 479.33,1888.78 525.5,1934.94 844.39,1934.94 879.83,1970.38 879.83,2025.43 889.76,2035.37 889.76,2064.15 890.45,2064.83 890.45,2103.43 946.81,2159.8 1037.75,2159.8 v1(1051.18,2173.23)
  Bottom Layer w8: v1@1050,2173 1050,2174.41 1018,2206.41 1018,2369.18 J4.6@1078.74,2429.92
OUT1: C3.1 C38.2 J3.1 TP2.1 U1.7
  other v1: 2615.09,178.6 2674.14,178.6 2733.2,178.6 2792.25,178.6 2851.31,178.6 2910.36,178.6 2969.42,178.6 3028.47,178.6 2644.61,237.65 2703.67,237.65 2762.72,237.65 2880.83,237.65 2939.89,237.65 2615.09,296.71 2674.14,296.71 2733.2,296.71 2910.36,296.71 2969.42,296.71 2644.61,355.76 2703.67,355.76 2762.72,355.76 2821.78,355.76 2880.83,355.76 2939.89,355.76 2998.94,355.76 2615.09,414.82 2674.14,414.82 2733.2,414.82 2910.36,414.82 2969.42,414.82 2644.61,473.87 2703.67,473.87 2762.72,473.87 2880.83,473.87 2939.89,473.87 2615.09,532.93 2674.14,532.93 2733.2,532.93 2792.25,532.93 2851.31,532.93 2910.36,532.93 2969.42,532.93 3028.47,532.93 2644.61,591.98 2703.67,591.98 2762.72,591.98 2821.78,591.98 2880.83,591.98 2939.89,591.98 2998.94,591.98 3058,591.98 2615.09,651.04 2674.14,651.04 2733.2,651.04 2792.25,651.04 2851.31,651.04 2910.36,651.04 2969.42,651.04 3028.47,651.04 2644.61,710.09 2703.67,710.09 2762.72,710.09 2821.78,710.09 2880.83,710.09 2939.89,710.09 2998.94,710.09 3058,710.09 2615.09,769.15 2674.14,769.15 2733.2,769.15 2792.25,769.15 2851.31,769.15 2910.36,769.15 2969.42,769.15 3028.47,769.15 2644.61,828.2 2703.67,828.2 2762.72,828.2 2821.78,828.2 2880.83,828.2 2939.89,828.2 2998.94,828.2 3058,828.2 2615.09,887.26 2674.14,887.26 2733.2,887.26 3028.47,887.26 2644.61,946.32 2703.67,946.32 2998.94,946.32 3058,946.32
  other v3: 2377.95,960.63 2427.17,960.63
OUT2: C3.2 C39.2 J8.1 TP5.1 U1.5
  other v1: 1670.2,178.6 1729.26,178.6 1788.31,178.6 1847.37,178.6 1906.42,178.6 1965.48,178.6 2024.53,178.6 2083.59,178.6 1758.79,237.65 1817.84,237.65 1935.95,237.65 1995.01,237.65 2054.06,237.65 2113.12,237.65 1729.26,296.71 1788.31,296.71 1847.37,296.71 1906.42,296.71 1965.48,296.71 2024.53,296.71 2083.59,296.71 1698.07,353.85 1875.97,354.33 1758.79,355.76 1817.84,355.76 1935.95,355.76 1995.01,355.76 2054.06,355.76 2113.12,355.76 1729.26,414.82 1788.31,414.82 1965.48,414.82 2024.53,414.82 2083.59,414.82 1758.79,473.87 1817.84,473.87 1935.95,473.87 1995.01,473.87 2054.06,473.87 2113.12,473.87 1788.31,532.93 1965.48,532.93 2024.53,532.93 2083.59,532.93 1670.3,534.39 1729.36,534.39 1847.47,534.39 1906.52,534.39 1698.83,591.63 1758.79,591.98 1817.84,591.98 1875.99,591.63 1935.95,591.98 1995.01,591.98 2054.06,591.98 2113.12,591.98 1670.2,651.04 1729.26,651.04 1788.31,651.04 1847.37,651.04 1906.42,651.04 1965.48,651.04 2024.53,651.04 2083.59,651.04 1699.73,710.09 1758.79,710.09 1817.84,710.09 1876.9,710.09 1935.95,710.09 1995.01,710.09 2054.06,710.09 2113.12,710.09 1670.2,769.15 1729.26,769.15 1788.31,769.15 1847.37,769.15 1906.42,769.15 1965.48,769.15 2024.53,769.15 2083.59,769.15 1876.9,828.2 1935.95,828.2 1995.01,828.2 2054.06,828.2 2113.12,828.2 1701.02,828.67 1760.07,828.67 1819.13,828.67 1965.48,887.26 2024.53,887.26 2083.59,887.26 1672.4,888.08 1935.95,946.32 1995.01,946.32 2054.06,946.32 2113.12,946.32 1701.93,947.13
  other v3: 2289.37,960.63 2338.58,960.63
P1.4: TP3.1 U3.6 | length 469.7
  Top Layer w6: TP3.1@404.47,2189.21 404.47,2192.9 409.84,2198.28 409.84,2235.58 413.35,2239.09 543.91,2239.09 593.35,2189.65 593.35,2184.68 589.83,2181.17 568.35,2181.17 559.99,2172.81 559.99,2126.4 566.36,2120.03 584.67,2120.03 627.02,2077.69 627.02,2047.2 U3.6@632.87,2041.34
P_IN: C6.2 C7.2 C8.2 C10.1 C14.1 C40.1 L1.1 Q1.5 Q1.6 Q1.7 Q1.8 Q1.9@2104.16,2861.95 U4.4 | length 790
  Top Layer w10: v1(2267.72,2456.69) v1@2268.94,2457.91
  Top Layer w20: U4.4@1687.01,3146.65 1686.73,3146.37 1686.73,3113.63 1748.93,3051.43 C14.1@1748.93,3018.41 ; C14.1@1753.32,3015.01 1757.16,3011.17 1757.16,2935.92 C6.2@1758.15,2934.92
  Top Layer w100: 2401.94,2359.89 2628.88,2359.89 2789.4,2520.41 C40.1@2887.53,2520.41
  other v1: 1800,2450 1900,2450 2000,2450 2100,2450 2200,2450 2321,2469 1811.02,2519.69 1889.76,2519.69 2204.72,2519.69 2283.46,2519.69 2362.2,2519.69 1772.72,2559.06 1850.39,2559.06 1929.13,2559.06 2244.09,2559.06 2322.83,2559.06 2401.57,2559.06 1811.02,2598.43 1889.76,2598.43 2283.46,2598.43 2050,2600 2150,2600 1966.84,2611.7 1850.39,2637.8 1800,2650 1900,2650 2100,2650 2250,2650 1977.04,2672.11 2286,2697 1850,2700 2350,2700 2450,2700 1800,2750 1900,2750 1950,2750 2000,2750 2050,2750 2100,2750 2150,2750 2200,2750 2250,2750 2350,2750 1950,2800 2250,2800 2350,2800 2450,2800 1826.77,2814.96 1850,2850 1950,2850 2250,2850 2350,2850 1850,2900 1950,2900 2250,2900 2350,2900 2450,2900 1838.9,2961.56
PH/IN2: J4.19 TP15.1 U1.10 | length 2385
  Top Layer w6: U1.10@2430.12,1089.57 2468.57,1089.57 2544.26,1165.26 2548,1165.26 2577.59,1194.84 2577.59,1198.59 2595,1216 2595,1746.26 2600.75,1752.02 2600.75,1765.49 v1(2603.37,1768.11)
  Top Layer w10: J4.19@1196.85,1724.41 1322.83,1850.39 TP15.1@1322.83,1881.89
  Bottom Layer w6: TP15.1@1322.63,1877.95 1339.44,1877.95 1420.55,1796.84 1443.31,1796.84 1559.06,1681.1 2519.82,1681.1 2603.37,1764.65 v1(2603.37,1768.11)
PH/IN2_MCU: J4.20 U3.12 | length 785
  Top Layer w6: U3.12@479.33,2041.34 485.19,2035.48 485.19,2010.42 523.45,1972.15 531.38,1972.15 v1(534,1969.53)
  Top Layer w10: v1(866.14,1728.35) J4.20@1078.74,1728.35
  Bottom Layer w6: v1(534,1969.53) 534,1899.07 610.24,1822.83 771.65,1822.83 v1(866.14,1728.35)
PUSH: J1.3 R18.1 U3.5 | length 551.7
  Top Layer w6: J1.3@305.56,2183.56 380.78,2258.78 581.22,2258.78 600.93,2239.07 ; 600,2238.14 600,2203.15 R18.1@653.54,2149.61 ; U3.5@657.48,2043.31 R18.1@657.48,2149.61
RST/SBWTDIO: C52.1 J1.1 J7.4 R73.1 U3.24 | length 1792.7
  Top Layer w6: R73.1@91,2303 91,2255.7 101,2245.7 v1(101,2242) ; R73.1@92.76,2305.76 C52.1@92.76,2359 ; U3.24@658.46,1809.06 658.46,1859.25 v1(661.42,1862.2)
  Bottom Layer w6: J1.1@105.29,2183.12 105.29,2459.19 cw(c148.4,2463.8) 105.29,2468.42 105.29,2511.17 107.05,2512.93 108.81,2514.69 597.52,2514.69 J7.4@648.4,2463.8 ; J7.4@648.35,2463.75 720.66,2391.44 720.66,2263.34 805.34,2178.66 805.34,2173.68 784.1,2152.44 784.1,1984.89 v1(661.42,1862.2)
SCLK/SR: J4.15 R39.1 TP13.1 U1.13 | length 2565.5
  Top Layer w5.98: 2481.29,1199.22 2507.65,1225.57 2507.65,1229.3 2534,1255.65 2534,1729.43 v1(2520.72,1742.72)
  Top Layer w6: R39.1@1502.59,1824.19 1502.59,1807.41 v1(1520,1790) ; U1.13@2358.27,1117.13 2358.27,1118.94 2358.38,1119.05 2358.38,1131.05 2374.13,1146.8 2431.8,1146.8 2470.41,1185.41 2470.41,1188.34 2481.29,1199.22
  Top Layer w10: J4.15@1188.98,1921.26 1242.81,1975.09 v1(1243.93,1975.09) 1262.87,1994.03 1262.87,2005.06 1262.52,2005.41 1262.52,2062.72 1318.9,2119.09 TP13.1@1318.9,2204.72
  Bottom Layer w6: v1(1243.93,1975.09) 1295.68,1975.09 1299.65,1971.12 1422.58,1971.12 1455.56,1938.14 1455.56,1854.44 v1(1520,1790) 1598.81,1711.19 2489.19,1711.19 v1(2520.72,1742.72)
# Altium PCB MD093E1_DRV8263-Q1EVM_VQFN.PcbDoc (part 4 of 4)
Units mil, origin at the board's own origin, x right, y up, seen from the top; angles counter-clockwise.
Board outline 3224.41 x 4078.74 mil, 4 copper layers (Top Layer, Signal Layer 1, Signal Layer 2, Bottom Layer), stack 61.2 mil thick; 228 components, 126 nets, 641 pads, 753 vias.
Unrouted connection lines stored in the file: 76.

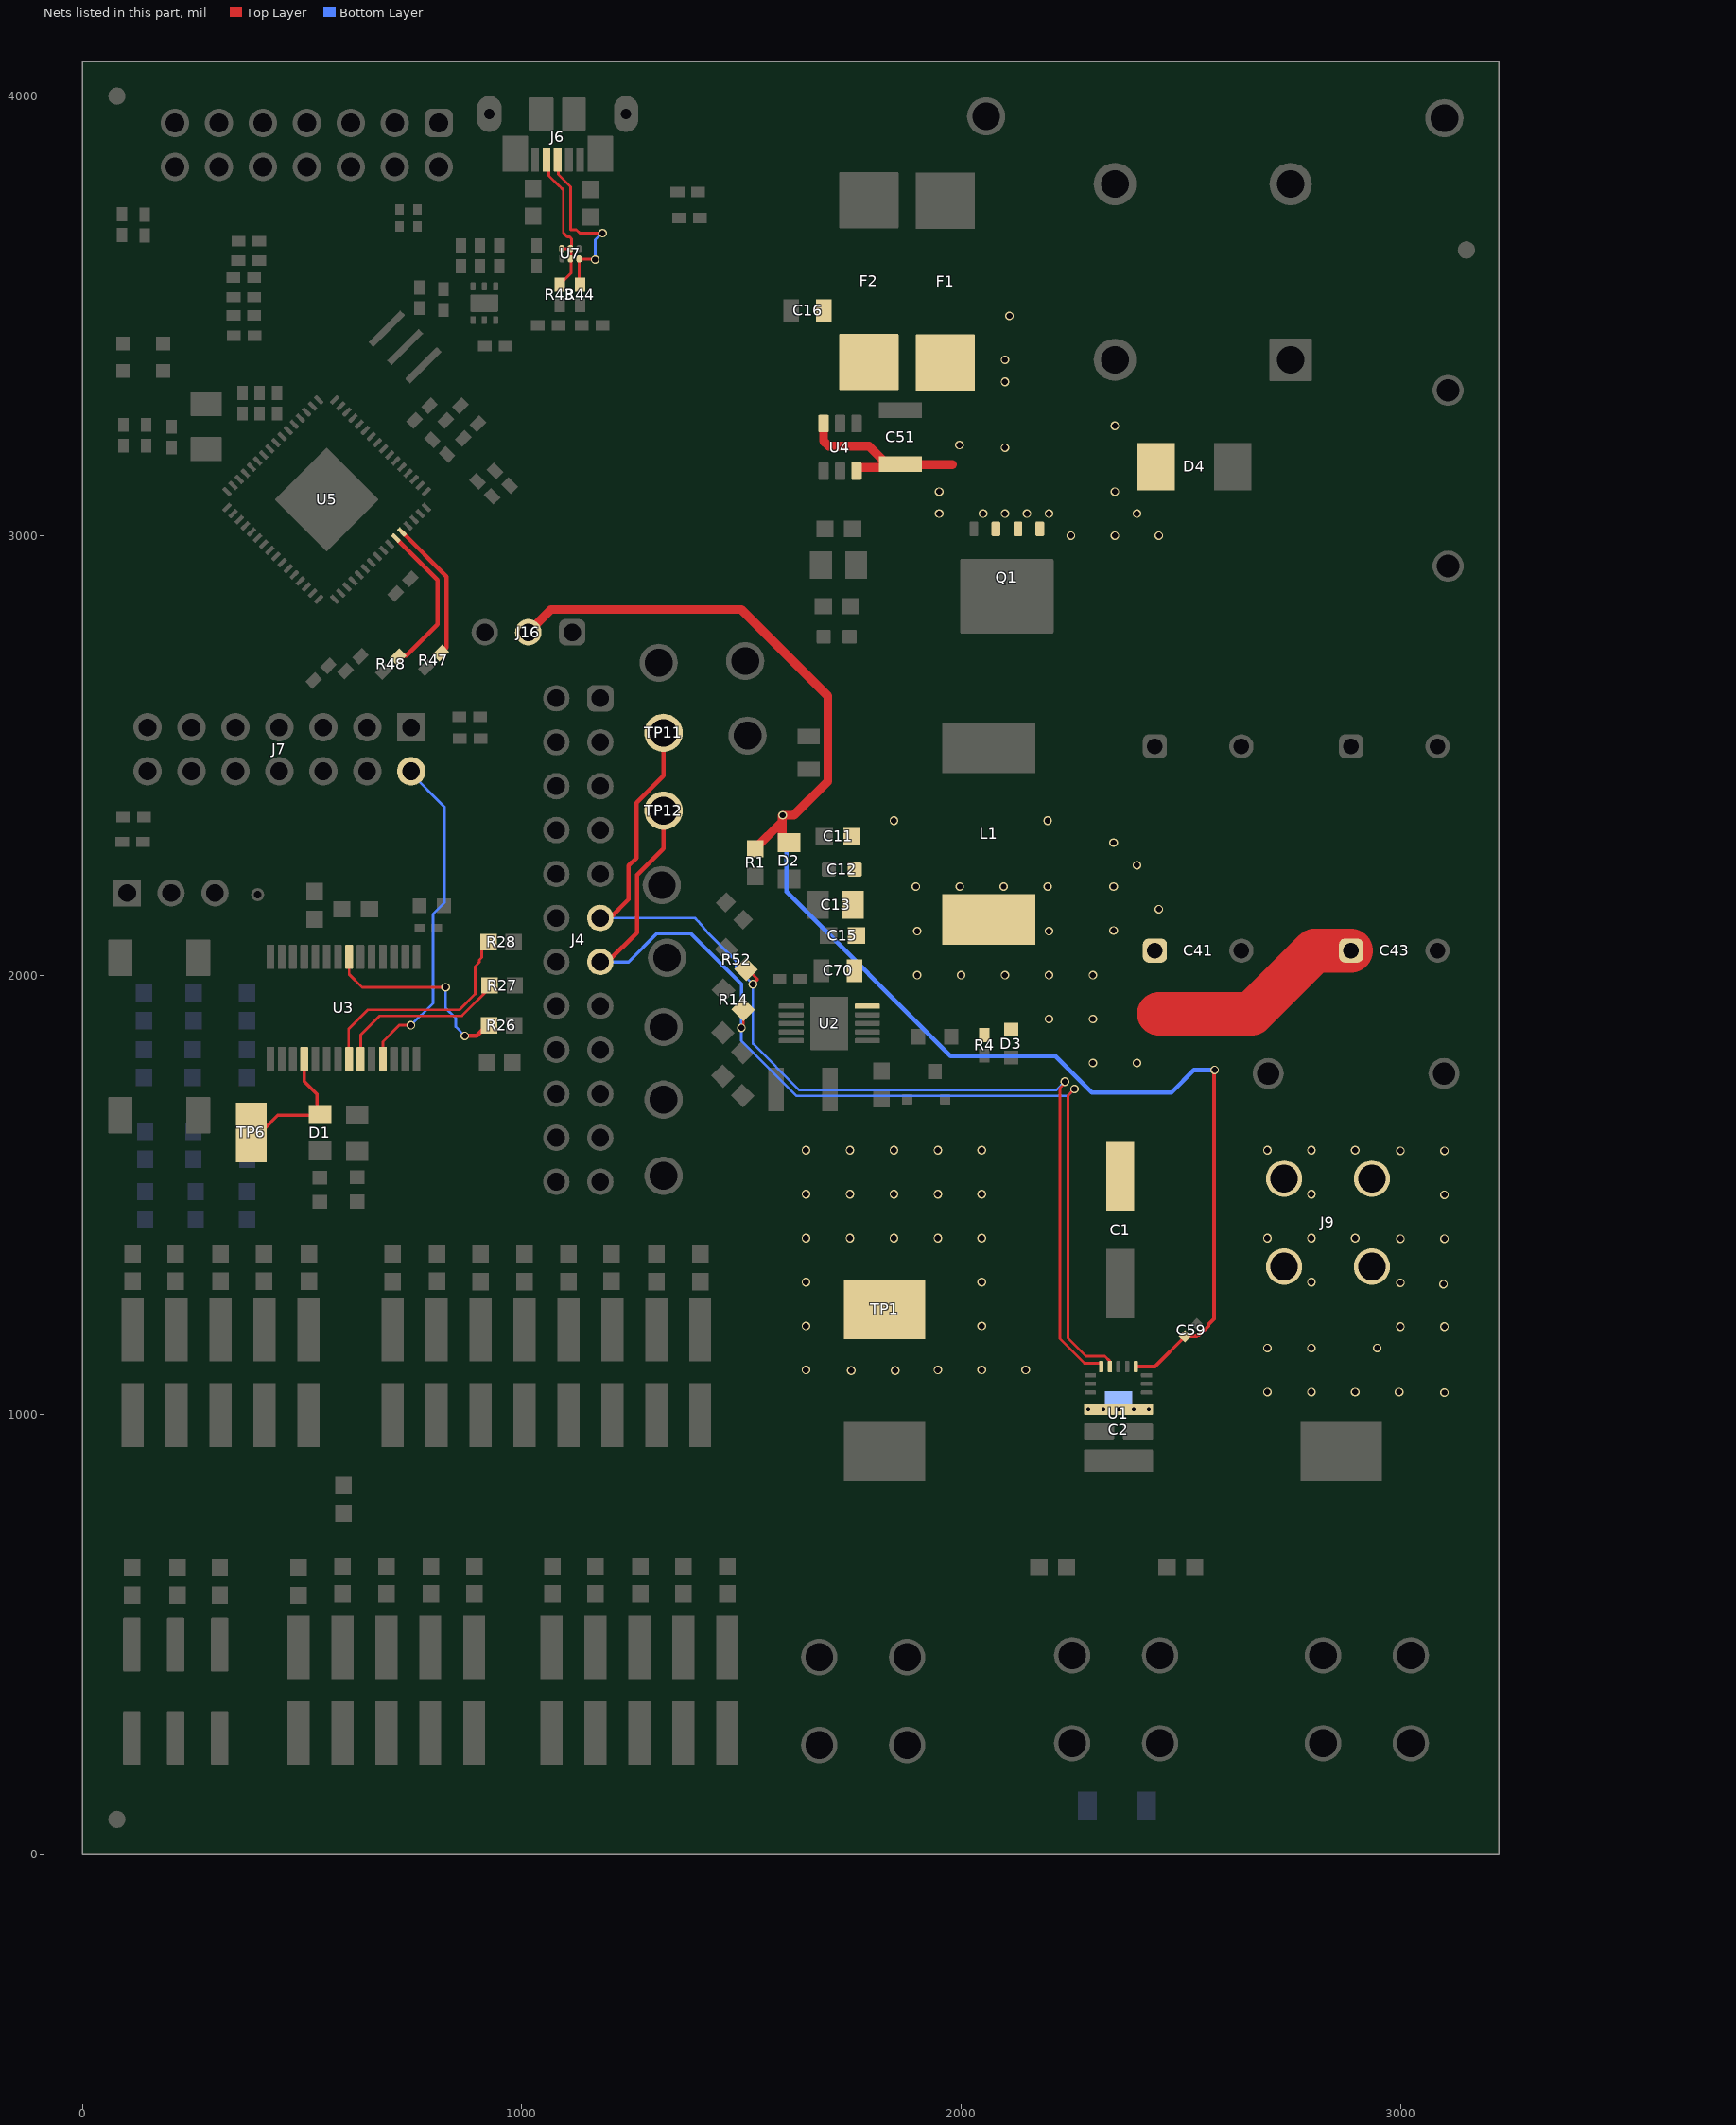
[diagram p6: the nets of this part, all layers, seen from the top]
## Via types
v1: diameter 19.68, hole 13.78, Top Layer to Bottom Layer, tented both sides, 714 vias
v2: diameter 19.68, hole 7.87, Top Layer to Bottom Layer, 20 vias
v3: diameter 19.68, hole 7.87, Top Layer to Bottom Layer, tented both sides, 19 vias

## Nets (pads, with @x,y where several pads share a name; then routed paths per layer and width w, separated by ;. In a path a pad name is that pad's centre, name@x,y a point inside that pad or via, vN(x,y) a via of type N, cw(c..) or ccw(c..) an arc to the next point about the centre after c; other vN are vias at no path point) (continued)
SCLK_MCU: R26.2 U3.7 | length 461
  Top Layer w6: U3.7@607.28,2041.34 607.28,2001.82 636.66,1972.44 v1(826.77,1972.44)
  Top Layer w10: v1(870.45,1861.67) 898.01,1861.67 R26.2@921.63,1885.29
  Bottom Layer w6: v1(826.77,1972.44) 826.77,1925.2 849.62,1902.35 849.62,1882.5 v1(870.45,1861.67)
SDI/ITRIP: J4.13 R14.1 TP12.1 U1.14 | length 2484.7
  Top Layer w6: R14.1@1503.94,1921.26 1504.63,1920.56 v1@1504.63,1888.34 ; v1(2258.11,1740.77) 2257.77,1740.77 2243.06,1726.06 2243.06,1174.2 2284.34,1132.92 2327.17,1132.92 2338.45,1121.64 U1.14@2338.45,1116.14
  Top Layer w10: J4.13@1181.1,2015.75 1229.25,2063.9 1229.88,2063.9 1262.52,2096.54 1262.52,2228.08 1322.83,2288.39 TP12.1@1322.83,2374.02
  Bottom Layer w6: v1@1500,1877 1500,1850.46 1625.4,1725.06 2242.06,1725.06 2257.77,1740.77 v1(2258.11,1740.77)
  Bottom Layer w8: J4.13@1178.74,2029.92 1242.95,2029.92 1307.77,2094.74 1384.83,2094.74 1500,1979.57 v1(1500,1880)
SDI_MCU: R27.2 U3.23 | length 398.4
  Top Layer w6: U3.23@632.87,1809.06 633.86,1809.06 633.86,1863.94 677.11,1907.2 863.89,1907.2 925.2,1968.5 R27.2@925.2,1976.38
SDO/MODE: J4.11 R52.1 TP11.1 U1.15 | length 2559.9
  Top Layer w6: R52.1@1510.46,2013.16 1514.4,2013.16 1536.87,1990.69 1536.87,1989.84 1526.25,1979.23 v1(1526.25,1979.01) ; v1(2236.23,1757.52) 2236.23,1753.82 2225,1742.59 2225,1172.64 2280.56,1117.08 2316.98,1117.08 2318.9,1115.16 U1.15@2318.9,1109.25
  Top Layer w10: J4.11@1200.79,2129.92 1243.19,2172.32 1243.19,2248.78 1261.06,2266.65 1261.06,2391.97 1322.83,2453.74 TP11.1@1322.83,2551.18
  Bottom Layer w6: J4.11@1173.23,2125.98 1177.17,2129.92 1393.7,2129.92 1401.15,2122.47 1423.13,2096.46 1487.31,2032.29 1487.31,2017.96 v1(1526.25,1979.01) 1526.25,1843.83 1631.15,1738.93 2217.64,1738.93 v1(2236.23,1757.52)
SDO_MCU: R28.2 U3.22 | length 521.3
  Top Layer w6: U3.22@607.28,1809.06 606.3,1809.06 606.3,1877.95 649.42,1921.07 858.08,1921.07 893.7,1956.69 893.7,2019.69 903.64,2029.62 903.64,2034.67 909.1,2040.13 909.1,2059.54 R28.2@924.8,2075.24
STATUS: D1.2 TP6.1 U3.18 | length 313
  Top Layer w8: TP6.1@374.02,1649.61 413.39,1649.61 444.88,1681.1 534,1681.1 534,1729 504.92,1758.08 U3.18@504.92,1809.06
T_RST_RST: R48.1 U5.43 | length 343.3
  Top Layer w10: U5.43@718.29,2989.52 808.72,2899.1 808.72,2797.72 737.78,2726.78 R48.1@724.05,2726.78
T_TEST_TCKC: R47.1 U5.44 | length 331.5
  Top Layer w10: U5.44@727.39,3008.26 829,2906.65 829,2745.49 R47.1@810.16,2726.65
TST/SBWTCK: J7.2 U3.25 | length 761.6
  Top Layer w6: U3.25@684.05,1809.06 684.05,1848.57 721.31,1885.83 v1(748.03,1885.83)
  Bottom Layer w6: J7.2@743.09,2463.5 824,2382.59 824,2164.78 797.97,2138.76 797.97,1935.77 v1(748.03,1885.83)
USB_D_N: J6.2 R43.1 U7.2 U7.5 U7.6 | length 352.9
  Top Layer w6.3: J6.2@1055.72,3865.22 1062.07,3858.88 1062.07,3818.69 1084.98,3795.78 1085.63,3795.78 1094.64,3786.77 1094.64,3689.15 1104.46,3679.33 1109.49,3679.33 1113.18,3675.64 1113.18,3656.56 U7.5@1109.45,3652.83 ; R43.1@1086.38,3571.1 1112,3596.72 1112,3629.54 U7.5@1112,3650.48 ; U7.6@1091.24,3653.16 1109.11,3653.16 U7.5@1110.8,3651.48 ; U7.5@1110.93,3651.61 U7.5@1110.93,3653.16
USB_D_P: J6.3 R44.1 U7.3 | length 412.1
  Top Layer w6.3: J6.3@1081.95,3854.83 1083.21,3853.56 1083.21,3821.9 1111.4,3793.71 1111.4,3696.09 1124.07,3696.09 1132.17,3688 v1(1184,3688) ; R44.1@1132.41,3571.1 1130.61,3572.9 1130.61,3629.97 1131.81,3628.77 1166.23,3628.77 v1(1167,3628)
  Bottom Layer w6.3: v1(1167,3628) 1167,3673.26 1181.74,3688 v1(1184,3688)
VBAT: C16.1 C51.2 D4.2 F1.1 F2.1 Q1.1 Q1.2 Q1.3 U4.3 U4.6 | length 392.6
  Top Layer w20: U4.3@1687.01,3254.92 1687.01,3215.11 1698.72,3203.4 1790.11,3203.4 1822.79,3170.72 1822.79,3168.72 1826.5,3165 1826.5,3159 1822.79,3155.28 1762.57,3155.28 U4.6@1761.81,3154.53 ; C51.2@1862,3163 1863.19,3161.81 1980.38,3161.81
  other v1: 2250,3000 2350,3000 2450,3000 1950,3050 2050,3050 2100,3050 2150,3050 2200,3050 2400,3050 1950,3100 2350,3100 2100,3200 1996.29,3205.97 2350,3250 2100,3350 2100,3400 2110,3500
VDD: C59.1 D2.2 J16.2 R1.2 U1.11 | length 3426.4
  Top Layer w8: U1.11@2397.64,1109.25 2441.25,1109.25 C59.1@2509.46,1177.46 ; C59.1@2509.08,1178.08 2536.05,1178.08 2538.1,1180.13 2541.84,1180.13 2562.71,1201.01 2562.71,1204.75 2575.72,1217.75 2575.72,1782.72 v1(2577,1784)
  Top Layer w20: J16.2@1015,2780 1066.63,2831.63 1499.74,2831.63 1696.46,2634.91 1696.46,2441 1619.37,2363.9 v1(1593.96,2363.9) 1592.6,2362.55 1592.6,2349.5 ; R1.2@1531.5,2287.4 1531.5,2288.39 1592.6,2349.5 ; D2.2@1608.19,2306.18 1599.44,2306.18 1592.6,2313.02 1592.6,2349.5
  Bottom Layer w10: v1(1593.96,2363.9) 1593.96,2338.6 1591.92,2336.57 1591.92,2313.88 1602.36,2303.44 1602.36,2189.64 1976,1816 2215,1816 2298,1733 2478.87,1733 2529.87,1784 v1(2577,1784)
VM: C1.1 C2.1 C11.2 C12.2 C13.2 C15.1 C41.1 C43.1 C70.1 D3.2 J9.1 L1.2 R4.2 TP1.1 U1.4 U2.10 | length 497.1
  Top Layer w100: 2450,1911.89 2661,1911.89 2804.87,2055.76 C43.1@2887.53,2055.76
  other v1: 3100,1050 2696.98,1051.43 2796.98,1051.43 2896.98,1051.43 2996.98,1051.43 1750,1100 1850,1100 1646.98,1101.43 1946.98,1101.43 2046.98,1101.43 2146.98,1101.43 2696.98,1151.43 2796.98,1151.43 2946.98,1151.43 3000,1200 3100,1200 1646.98,1201.43 2046.98,1201.43 3097.91,1296.73 3000,1300 1646.98,1301.43 2046.98,1301.43 2796.98,1301.43 3000,1400 3100,1400 1646.98,1401.43 1746.98,1401.43 1846.98,1401.43 1946.98,1401.43 2046.98,1401.43 2696.98,1401.43 2796.98,1401.43 2896.98,1401.43 3100,1500 1646.98,1501.43 1746.98,1501.43 1846.98,1501.43 1946.98,1501.43 2046.98,1501.43 2796.98,1501.43 3000,1600 3100,1600 1646.98,1601.43 1746.98,1601.43 1846.98,1601.43 1946.98,1601.43 2046.98,1601.43 2696.98,1601.43 2796.98,1601.43 2896.98,1601.43 2300,1800 2400,1800 2200,1900 2300,1900 1900,2000 2000,2000 2100,2000 2200,2000 2300,2000 1900,2100 2200,2100 2346.98,2101.43 2450,2150 1896.98,2201.43 1996.98,2201.43 2096.98,2201.43 2196.98,2201.43 2346.98,2201.43 2400,2250 2346.98,2301.43 1846.98,2351.43 2196.98,2351.43
  other v3: 2289.37,1011.81 2323.82,1011.81 2358.27,1011.81 2392.72,1011.81 2427.17,1011.81
pads on no net: FID1.1 FID2.1 FID3.1 J4.3 J4.4 J5.6 J5.10 J5.12 J5.13 J5.14 J6.4 J7.11 J7.12 LBL1.0 Q1.9@2010.75,2937.15 Q1.9@2051.8,2834.99 Q1.9@2051.8,2880.26 Q1.9@2051.8,2925.54 Q1.9@2104.16,2834.99 Q1.9@2104.16,2874.95 Q1.9@2104.16,2880.26 Q1.9@2104.16,2925.54 Q1.9@2156.52,2834.99 Q1.9@2156.52,2880.26 Q1.9@2156.52,2925.54 Q1.9@2197.56,2937.15 S1.2 SH-J1.0 SH-J2.0 SH-J3.0 SH-J4.0 SH-J5.0 SH-J6.0 SH-J7.0 SH-J8.0 SH-J9.0 SH-J10.0 SH-J11.0 SH-J12.0 SH-J13.0 SH-J14.0 SH-J15.0 SH-J16.0 SH-J17.0 SH-J18.0 SH-J19.0 SH-J20.0 SH-J21.0 SH-J22.0 SH-J23.0 SH-J24.0 U2.3 U2.6 U2.9 U3.11 U3.20 U3.21 U5.3 U5.4 U5.5 U5.6 U5.7 U5.8 U5.10 U5.12 U5.13 U5.18 U5.19 U5.22 U5.23 U5.24 U5.25 U5.26 U5.27 U5.28 U5.29 U5.30 U5.31 U5.32 U5.33 U5.34 U5.35 U5.36 U5.41 U5.42 U5.45 U5.46 U5.47 U5.48 U6.7@897.1,3528.82 U6.7@932.53,3528.82

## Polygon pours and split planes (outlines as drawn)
GND on Top Layer "TOP_LAYER_GND_P238" (solid, remove dead copper, pour order 238): 2.97,-3.71 3227.38,-3.71 3227.38,4075.03 2.97,4075.03
VM on Top Layer "TOP_LAYER_NONET_P-001" (solid, pour order 86): 2165.35,1657.48 1570.87,1657.48 1570.87,997 3153.54,997 3153.54,1661.42 2559.06,1661.42 2559.06,1141.73 2448.82,1031.5 2275.59,1031.5 2165.35,1141.73
VBAT on Top Layer "TOP_LAYER_VBAT_P201" (solid, pour order 201): 2169,3550 2169,3350 2222,3297 2476.38,3297 2476.38,2964.57 1808.15,2964.57 1808.15,3320 1670,3320 1670,3550
VM on Top Layer "TOP_LAYER_VM_P167" (solid, pour order 167): 2240.16,1397.64 2488.19,1397.64 2488.19,2381.89 1732.28,2381.89 1732.28,1854.33 2240.16,1854.33
GND on Top Layer "TOP_LAYER_GND_P129" (solid, pour order 129): 2240.16,1397.64 2476.38,1397.64 2476.38,1090.55 2236.22,1090.55
P_IN on Top Layer "TOP_LAYER_P_IN_P207" (solid, pour order 207): 2488.19,2389.76 2488.19,2959.46 1716.54,2959.46 1716.54,2389.76
EZFET_USB_Shield on Top Layer "TOP_LAYER_EZFET_USB_SHIELD_P173" (solid, remove dead copper, pour order 173): 828.96,4067.16 1305.04,4067.16 1305.04,3859.28 828.96,3859.28
NetF1_2 on Top Layer "TOP_LAYER_NETF1_2_P223" (solid, pour order 223): 1691,3560 2050,3560 2170,3440 2170,3300 2640,3300 2640,4078.74 1691,4078.74
OUT1 on Top Layer "TOP_LAYER_OUT1_P119" (solid, pour order 119): 2362.2,992 2362.2,936 2503.94,936 2503.94,78.74 3149.61,78.74 3149.61,992
OUT2 on Top Layer "TOP_LAYER_OUT2_P125" (solid, pour order 125): 2350.39,992 2350.39,935 2204.72,935 2204.72,78.74 1570.87,78.74 1570.87,992
OUT1 on Bottom Layer "TOP_LAYER_NONET_P-001" (solid, pour order 205): 2389.76,80.71 3149.61,80.71 3149.61,987 2358.27,987 2358.27,936 2507.87,936 2507.87,141.73 2389.76,141.73
GND on Bottom Layer "BOTTOM_LAYER_GND_P232" (solid, remove dead copper, pour order 232): 0,0 3224.41,0 3224.41,4078.74 0,4078.74
VM on Bottom Layer "BOTTOM_LAYER_VM_P219" (solid, pour order 219): 1574.8,991 3149.61,991 3149.61,1655.51 1574.8,1655.51
VM on Bottom Layer "TOP_LAYER_NONET_P-001" (solid, pour order 165): 1736.22,2362.2 2488.19,2362.2 2488.19,2007.39 1941.42,2007.39 1736.22,2212.6
P_IN on Bottom Layer "BOTTOM_LAYER_P_IN_P174" (solid, pour order 174): 2488.19,2373.23 2488.19,3141.73 1736.22,3141.73 1736.22,2373.23
VBAT on Bottom Layer "BOTTOM_LAYER_VBAT_P237" (solid, pour order 237): 2172,3550 2172,3350 2225,3297 2479.38,3297 2479.38,2964.57 1900,2964.57 1900,3310 1890,3320 1673,3320 1673,3550
NetF1_2 on Bottom Layer "BOTTOM_LAYER_NETF1_2_P231" (solid, pour order 231): 1687,3560.63 2149.37,3560.63 2166,3544 2166,3365 2222,3309 2636,3309 2636,4056 1687,4056
OUT2 on Bottom Layer "TOP_LAYER_NONET_P-001" (solid, pour order 204): 2318.9,80.71 2318.9,141.73 2204.72,141.73 2204.72,935 2358.27,935 2358.27,987 1574.8,987 1574.8,80.71
GND on Bottom Layer "BOTTOM_LAYER_GND_P235" (solid, pour order 235): 2496.06,1407.55 2212.6,1407.55 2212.6,911.42 2496.06,911.42
EZFET_USB_Shield on Bottom Layer "BOTTOM_LAYER_EZFET_USB_SHIELD_P211" (solid, remove dead copper, pour order 211): 846.96,4067.16 1323.04,4067.16 1323.04,3859.28 846.96,3859.28
VM on Signal Layer 2 "SIGNAL_LAYER_2_VM_P160" (solid, pour order 160): 3149.61,1653.54 3149.61,78.74 1574.8,78.74 1574.8,1653.54
GND on Signal Layer 2 "SIGNAL_LAYER_2_GND_P199" (solid, pour order 199): -3.59,-8.73 3220.82,-8.73 3220.82,4070.01 -3.59,4070.01
VM on Signal Layer 2 "SIGNAL_LAYER_2_VM_P175" (solid, pour order 175): 1618.11,1665.35 2493,1665.35 2493,2366.14 1618.11,2366.14
VDD on Signal Layer 2 "SIGNAL_LAYER_2_VDD_P194" (solid, pour order 194): 1251.97,2574.8 1259.84,2566.93 1614.17,2566.93 1614.17,1448.82 1259.84,1448.82
3V3_MCU on Signal Layer 2 "SIGNAL_LAYER_2_3V3_MCU_P192" (solid, pour order 192): 0,2503.94 952.76,2503.94 952.76,2665.35 1165.35,2665.35 1165.35,1452.76 0,1452.76
P_IN on Signal Layer 2 "SIGNAL_LAYER_2_P_IN_P198" (solid, pour order 198): 2488.19,2373.23 2488.19,3141.73 1736.22,3141.73 1736.22,2373.23
NetF1_2 on Signal Layer 2 "SIGNAL_LAYER_2_NETF1_2_P234" (solid, pour order 234): 1694,3557.63 2156.37,3557.63 2173,3541 2173,3362 2229,3306 2643,3306 2643,4053 1694,4053
VBAT on Signal Layer 2 "SIGNAL_LAYER_2_VBAT_P233" (solid, pour order 233): 2170,3550 2170,3350 2223,3297 2477.38,3297 2477.38,2964.57 1898,2964.57 1898,3310 1888,3320 1671,3320 1671,3550
EZFET_VCC on Signal Layer 2 "SIGNAL_LAYER_2_EZFET_VCC_P132" (solid, remove dead copper, pour order 132): 8.99,2518.8 937.86,2518.8 937.86,3524.84 792.38,3524.84 792.27,3524.96 792.27,4067.37 10.03,4067.37 8.99,4068.41
VM on Signal Layer 2 "SIGNAL_LAYER_2_VM_P177" (solid, pour order 177): 2165.35,1692.91 2165.35,1629.92 2559.06,1629.92 2559.06,1692.91
EZFET_VBUS on Signal Layer 2 "SIGNAL_LAYER_2_EZFET_VBUS_P136" (solid, remove dead copper, pour order 136): 792.27,4067.37 1412.99,4067.37 1413.03,4067.41 1416.99,4063.45 1416.99,3519.39 793.66,3519.39
GND on Signal Layer 1 "TOP_LAYER_NONET_P-001" (solid, pour order 225): 1574.8,1653.54 3149.61,1653.54 3149.61,78.74 1574.8,78.74
GND on Signal Layer 1 "SIGNAL_LAYER_1_GND_P184" (solid, pour order 184): 7.87,4082.68 3228.35,4082.68 3224.41,4078.74 3224.41,1661.42 1555.12,1661.42 1555.12,0 -12.02,0
GND on Signal Layer 1 "SIGNAL_LAYER_1_GND_P190" (solid, pour order 190): 2165.35,1614.17 2165.35,1692.91 2559.06,1692.91 2559.06,1614.17

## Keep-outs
Keep-Out Layer:
  text ".Layer_Name" at 577,-858.49 h25

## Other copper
Top Layer:
  pour cut-out: 1570.87,78.74 3224.41,78.74 3224.41,0 1570.87,0
  pour cut-out: 3153.54,1657.48 3224.41,1657.48 3224.41,0 3153.54,0
  text ".Layer_Name" at 577,-858.49 h25
Bottom Layer:
  pour cut-out: 3224.41,1653.54 3161.42,1653.54 3161.42,0 3220.47,0 3224.41,-7.87
  pour cut-out: 1574.8,78.74 3224.41,78.74 3224.41,0 1574.8,0
  text ".Layer_Name" at 577,-858.49 h25

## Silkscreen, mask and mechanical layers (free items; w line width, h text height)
Top Overlay:
  circle w20: c2240.72,3040.22 r7
  circle w20: c1559.96,1934.8 r7
  circle w20: c515.62,3341.92 r7
  rectangle: 1261,3351 1335.98,3416
  rectangle: 1525,3352 1601,3412
  lines w5: 1269.22,2855.76 1269.22,3415.76
  lines w7.87: 1574.8,78.74 1574.8,1653.54 3149.61,1653.54 3149.61,78.74 1574.8,78.74
  lines w10: 778.53,4003.94 869.08,4003.94 869.08,3909.45 ; 1147.24,2855 1600,2855 1600,3413.88 1147.24,3413.88 1147.24,2855
  text "For EZFET-LITE Flashing Only" at 184.04,4019.69 h25
  text "1" at 884.83,3992.13 h25
  text "+BAT" at 1966,3832 h45
  text "GND" at 3004,3826 h45
  text "'.PRJ_Number'.PCB_Rev" at 1334,3650 h40
  text "TP#" at 1162,3361 h60
  text "Net S/H" at 1331,3352 h60
  text "nSLEEP" at 1323.22,3320.76 h25
  text "PWR" at 52.05,3317.24 h25
  text "MODE" at 145.25,3317.26 h25
  text "TP4" at 1163.52,3315.52 h25
  text "IPROPI" at 1323.22,3270.76 h25
  text "TP7" at 1163.52,3265.52 h25
  text "nFAULT" at 1323.22,3220.76 h25
  text "TP10" at 1163.52,3215.52 h25
  text "SDO/MODE" at 1323.22,3170.76 h25
  text "TP11" at 1163.52,3165.52 h25
  text "SDI/ITRIP" at 1323.22,3120.76 h25
  text "TP12" at 1163.52,3115.52 h25
  text "GND" at 3183.07,3076.74 h35 r90
  text "SCLK/SR" at 1323.22,3070.76 h25
  text "TP13" at 1163.52,3065.52 h25
  text "nSCS/DIAG" at 1323.22,3020.76 h25
  text "TP14" at 1163.52,3015.52 h25
  text "PH/IN2" at 1323.22,2970.76 h25
  text "TP15" at 1163.52,2965.52 h25
  text "TP16" at 1165.52,2921.52 h25
  text "EN/IN1" at 1323.22,2920.76 h25
  text "TP17" at 1165.52,2871.52 h25
  text "DRVOFF" at 1323.22,2870.76 h25
  text "VDD" at 1031,2844 h35 r90
  text "3V3_MCU" at 1127,2844 h35 r90
  text "3V3_LDO" at 913.97,2835.64 h35 r90
  text "GND" at 1196,2676 h25 r90
  text "+" at 2907.88,2579.27 h35 r90
  text "-" at 3073.44,2566.61 h35
  text "+" at 2465.48,2563.89 h35 r90
  text "-" at 2630.14,2553.03 h35
  text "GND" at 61,2488 h25 r270
  text "nSLEEP" at 836.91,2415.33 h30
  text "3V3" at 325.76,2400.81 h25 r270
  text ">>RX" at 428.13,2400.81 h25 r270
  text "<<TX" at 526.55,2400.81 h25 r270
  text "TDIO" at 624.98,2400.81 h25 r270
  text "TCK" at 727.34,2400.81 h25 r270
  text "nFAULT" at 1476.38,2350.39 h25
  text "IPROPI" at 849.41,2324.78 h30
  text "nFAULT" at 836.91,2226.36 h30
  text "SDO/MODE" at 819.07,2115.55 h25
  text "+" at 2460.68,2105.25 h35 r90
  text "RST" at 86.61,2102.36 h25
  text "PUSH" at 287.4,2102.36 h25
  text "+" at 2909.69,2101.59 h35 r90
  text "-" at 2624.86,2101.2 h35
  text "-" at 3074.35,2088.02 h35
  text "SDI/ITRIP" at 804.89,2008.09 h25
  text "SCLK/SR" at 831.06,1912.89 h25
  text "nSCS/DIAG" at 785.24,1818.54 h25
  text "GND" at 2856.21,1809.68 h35
  text "VM" at 2153,1808 h45
  text "PH/IN2" at 837.78,1719.04 h30
  text "EN/IN1" at 846.11,1620.61 h30
  text "DRV8263 VQFN" at 1598.43,1596.68 h35
  text "3V3" at 692,1593 h35 r90
  text "Status" at 496,1548 h35 r90
  text "40mm x 40mm" at 1590,1546 h35
  text "DRVOFF" at 833.62,1517.94 h30
  text "4 layers" at 1595,1491 h35
  text "2oz copper" at 1593.93,1439.29 h35
  text "VM" at 2580,1340 h55
  text "VM" at 1784.76,1333.79 h55
  text "680" at 1279.13,839.68 h25 r45
  text "470" at 1379.13,839.68 h25 r45
  text "6.8k" at 679.13,829.68 h25 r45
  text "4.7k" at 779.13,829.68 h25 r45
  text "3.3k" at 879.13,829.68 h25 r45
  text "2.2k" at 979.13,829.68 h25 r45
  text "1.5k" at 1079.13,829.68 h25 r45
  text "1.0k" at 1179.13,829.68 h25 r45
  text "LVL4" at 169.29,826.77 h25 r45
  text "LVL3" at 271.65,826.77 h25 r45
  text "LVL5" at 70.87,822.83 h25 r45
  text "LVL2" at 370.08,822.83 h25 r45
  text "LVL1" at 468.5,822.83 h25 r45
  text "ITRIP" at 244.09,751.97 h35
  text "IPROPI" at 980,740 h35
  text "GND" at 2295,706 h55
  text "OUT2" at 1773.09,695.79 h55
  text "OUT1" at 2806.56,695.79 h55
  text "LVL3" at 70.87,106.3 h25 r45
  text "LVL4" at 551.18,106.3 h25 r45
  text "LVL3" at 653.54,106.3 h25 r45
  text "LVL4" at 1129.92,106.3 h25 r45
  text "LVL3" at 1232.28,106.3 h25 r45
  text "LVL2" at 169.29,102.36 h25 r45
  text "LVL1" at 267.72,102.36 h25 r45
  text "LVL5" at 452.76,102.36 h25 r45
  text "LVL2" at 751.97,102.36 h25 r45
  text "LVL1" at 850.39,102.36 h25 r45
  text "LVL5" at 1031.5,102.36 h25 r45
  text "LVL2" at 1330.71,102.36 h25 r45
  text "LVL1" at 1429.13,102.36 h25 r45
  text "MODE" at 118.11,39.37 h35
  text "SLEW RATE" at 507.87,39.37 h35
  text "DIAG" at 1188.98,39.37 h35
  text ".Layer_Name" at 577,-858.49 h25
Bottom Overlay:
  lines w5: 2275.5,861.36 2440.99,861.36 2440.99,1125.89 2275.5,1125.89 2275.5,861.36
  text "ID1" at 160.11,2007.4 h25
  text "ID3" at 404.54,2007.4 h25
  text "ID2" at 282.33,2004.42 h25
  text "0" at 433.19,1909.77 h25
  text "1" at 424.42,1791.73 h25
  text "0" at 444.2,1617.04 h25
  text "1" at 430.64,1480.25 h25
  text "ID5" at 411.99,1381.42 h25
  text "ID4" at 287.82,1377.99 h25
  text "ID0" at 175.68,1375.76 h25
  text ".Layer_Name" at 577,-858.49 h25
Top Paste:
  text ".Layer_Name" at 577,-858.49 h25
Bottom Paste:
  text ".Layer_Name" at 577,-858.49 h25
Top Solder:
  text ".Layer_Name" at 577,-858.49 h25
  text ".Layer_Name" at 577,-858.49 h25
Bottom Solder:
  text ".Layer_Name" at 577,-858.49 h25
Drill Guide:
  text ".Layer_Name" at 577,-858.49 h25
M1 Board Outline:
  lines w7.87: 3216.54,0 3216.54,4073.9
  lines w10: 3216.54,0 0,0 0,4076.1 3216.54,4073.9
  text ".Layer_Name" at 577,-858.49 h25
M2 Board Dimensions:
  rectangle: 0,-275 125,-150
  rectangle: 125,-400 500,-275
  lines w7: 0,-275 1000,-275 ; 125,-400 125,-150 ; 250,-400 250,-150 ; 500,-400 500,-150 ; 750,-400 750,-150 ; 0,-400 1000,-400 1000,-150 0,-150 0,-400
  text ".Layer_Name" at 577,-858.49 h25
M3 3D STEP Top:
  text ".Layer_Name" at 577,-858.49 h25
M4 3D STEP Bottom:
  text ".Layer_Name" at 577,-858.49 h25
M5 Assembly Top:
  lines w10: -292,-930.17 6308,-930.17 ; -292,-726.83 6310,-726.83 ; -292,-523.5 -292,-1133.5 3713,-1133.5 6310,-1133.5 6310,-523.5 -291.5,-523.5 -291.5,-1133.5 1284,-1133.5 ; 2173,-1133.5 2173,-523.5 ; 3440,-726.83 3440,-523.5 ; 4280,-726.83 4280,-523.5 ; 4902,-1140 4902,-937.17
  text "COMPONENTS MARKED 'DNP' SHOULD NOT BE POPULATED." at 1153.5,-318.5 h25
  text "ASSEMBLY VARIANT:" at 1153,-434 h25
  text ".VariantName" at 2189,-434 h25
  text "PCB VIEWED FROM TOP SIDE" at -228.5,-655.67 h25
  text "BOARD #:" at 2248,-655.67 h25
  text ".PRJ_Number" at 2793.5,-655.67 h25
  text "REV:" at 3638,-655.67 h25
  text ".PCB_Rev" at 3929.5,-655.67 h25
  text "SVN REV:" at 4476,-655.67 h25
  text ".VersionControl_RevNumber" at 4982,-655.67 h25
  text "TID #:" at 2248,-859 h25
  text ".TID" at 2793.5,-859 h25
  text "PLOT NAME =" at -228.5,-1064.34 h25
  text ".plot_File_Name" at 577,-1064.34 h25
  text "GENERATED    :" at 2250,-1064.34 h25
  text ".Print_Date" at 3119.5,-1064.34 h25
  text ".Print_Time" at 3848.5,-1064.34 h25
  text "TEXAS INSTRUMENTS" at 5113,-1064.34 h25
M6 Assembly Bottom:
  lines w10: -292.5,-727.33 6309.5,-727.33 ; -290.5,-930.67 6309.5,-930.67 ; 1115.5,-1140.5 1115.5,-937.67 ; 1737.5,-727.33 1737.5,-524 ; 2577.5,-727.33 2577.5,-524 ; 3844.5,-1134 3844.5,-524 ; 4733.5,-1134 6309,-1134 6309,-524 -292.5,-524 -292.5,-1134 2304.5,-1134 6309.5,-1134 6309.5,-524
  text "COMPONENTS MARKED 'DNP' SHOULD NOT BE POPULATED." at 6102,-318 h25
  text ".VariantName" at 5058,-434 h25
  text "ASSEMBLY VARIANT:" at 6097,-434 h25
  text ".VersionControl_RevNumber" at 1035.5,-656.17 h25
  text "SVN REV:" at 1541.5,-656.17 h25
  text ".PCB_Rev" at 2088,-656.17 h25
  text "REV:" at 2379.5,-656.17 h25
  text ".PRJ_Number" at 3224,-656.17 h25
  text "BOARD #:" at 3769.5,-656.17 h25
  text "PCB VIEWED FROM BOTTOM SIDE" at 6246,-656.17 h25
  text ".TID" at 3224,-859.5 h25
  text "TID #:" at 3769.5,-859.5 h25
  text "TEXAS INSTRUMENTS" at 904.5,-1064.84 h25
  text ".Print_Time" at 2169,-1064.84 h25
  text ".Print_Date" at 2898,-1064.84 h25
  text "GENERATED    :" at 3767.5,-1064.84 h25
  text ".plot_File_Name" at 5440.5,-1064.84 h25
  text "PLOT NAME =" at 6246,-1064.84 h25
M9 Title Sheet:
  drawing of 57 lines, arcs and shapes, not listed
  text "1" at 739.84,8036.5 h25
  text "2" at 3235.5,8036.5 h25
  text "3" at 5724.84,8036.5 h25
  text "4" at 8231.51,8036.5 h25
  text "5" at 10730.5,8036.5 h25
  text "6" at 13235.5,8036.5 h25
  text "A" at -416.5,6893.5 h25
  text "A" at 14383.5,6893.5 h25
  text "B" at -416.5,4513.5 h25
  text "B" at 14383.5,4513.5 h25
  text "C" at -416.5,2138.5 h25
  text "C" at 14383.5,2138.5 h25
  text "PROJECT TITLE:" at 11343.5,277.5 h25
  text ".PRJ_Title" at 11393.5,144.17 h25
  text "DESIGNED FOR:" at 11343.5,-23.5 h25
  text ".PRJ_Customer" at 11393.5,-163.5 h25
  text "D" at -416.5,-231.5 h25
  text "D" at 14383.5,-231.5 h25
  text "FILE NAME:" at 11343.5,-323.5 h25
  text ".PCB_File_Name_No_Path" at 11393.5,-443.5 h25
  text "Texas Instruments (TI) and/or its licensors do not warrant the accuracy or completeness of this specification" at 6374,-605.34 h25
  text "ENGINEER:" at 11343.5,-613.5 h25
  text "LAYOUT BY:" at 12848.5,-613.5 h25
  text "or any information contained therein. TI and/or its licensors do not warrant that this design will meet" at 6329.01,-718 h25
  text ".PRJ_Engineer" at 11393.5,-768.49 h25
  text ".PCB_Layout" at 12899,-768.49 h25
  text "the specifications, will be suitable for your application or fit for any particular purpose, or will operate in" at 6329.01,-830.67 h25
  text ".Layer_Name" at 577,-858.49 h25
  text "ALTIUM DESIGNER VERSION:" at 12848.5,-923.5 h25
  text "an implementation. TI and/or its licensors do not warrant that the design is production worthy. You should" at 6329.01,-943.33 h25
  text "completely validate and test your design implementation to confirm the system functionality for your application." at 6374,-1056 h25
  text ".print_Scale" at 11393.5,-1056.83 h25
  text ".Application_BuildNumber" at 12899,-1056.83 h25
  text "1" at 739.84,-1263.5 h25
  text "2" at 3235.5,-1263.5 h25
  text "3" at 5724.84,-1263.5 h25
  text "4" at 8231.51,-1263.5 h25
  text "5" at 10730.5,-1263.5 h25
  text "6" at 13235.5,-1263.5 h25
M10 Fab Notes:
  drawing of 189 lines, arcs and shapes, not listed
  text "DESIGN INFORMATION" at 12382.02,6356.17 h25
  text "MIN. TRACK WIDTH:" at 11737.46,6224.05 h25
  text "8" at 12833.7,6224.05 h25
  text "MIL" at 12988.46,6224.05 h25
  text "MIN. CLEARANCE:" at 11737.46,6099.92 h25
  text "0.2" at 12773.7,6099.93 h25
  text "mm" at 12988.46,6099.92 h25
  text "MIN. VIA PAD SIZE:" at 11737.46,5975.8 h25
  text "24" at 12803.71,5975.8 h25
  text "MIL" at 12988.46,5975.8 h25
  text "0.05mm (2MIL)" at 12432.46,5845.9 h25
  text "MINIMUM ANNULAR RING" at 11408.23,5837.67 h25
  text "EXTERNAL" at 13140.46,5837.67 h25
  text "PER" at 11608.23,5727.55 h25
  text "IPC-D-275 CLASS 2 LEVEL C" at 11828.23,5727.54 h25
  text "MIL, HOLES" at 13316.46,5627.07 h25
  text "+/-" at 12924,5618.48 h25
  text "+/-" at 13778,5618.48 h25
  text "REGISTRATION TOLERANCES:" at 11408.23,5617.42 h25
  text "METAL" at 12608,5617.42 h25
  text "5" at 13184.2,5617.42 h25
  text "3" at 14017.2,5617.42 h25
  text "MIL" at 14133.46,5617.42 h25
  text "HOLE SIZE TOLERANCE (UNLESS OTHERWISE SPECIFIED):" at 11408.23,5519.1 h25
  text "+/-" at 13778,5516.23 h25
  text "3" at 14017.2,5515.17 h25
  text "MIL" at 14133.46,5515.17 h25
  text "MATERIAL:" at 11333.46,5377.52 h25
  text "FR-4 High Tg" at 12319.9,5249 h25
  text "X" at 12175.46,5241.01 h25
  text "FR-408" at 11754.46,5236.49 h25
  text "OTHER" at 13242.46,5236.49 h25
  text "62 MIL (1.6mm) +/-10%" at 12074.56,5093.46 h25
  text "X" at 11954.46,5091.01 h25
  text "THICKNESS:" at 11408.23,5085.24 h25
  text "OTHER" at 13359.46,5085.24 h25
  text "TOLERANCE:" at 11408.23,4946.92 h25
  text "X" at 12256.46,4946.92 h25
  text "ANSI IPC-6012 TYPE 3 CLASS 2" at 12434.48,4946.92 h25
  text "OTHER +/-" at 12434.46,4802.73 h25
  text "BOW & TWIST:" at 11408.23,4657.54 h25
  text "X" at 12256.46,4657.54 h25
  text "ANSI IPC-6012 TYPE 3 CLASS 2" at 12434.48,4657.54 h25
  text "OTHER +/-" at 12434.46,4510.85 h25
  text "DRILLING:" at 11333.46,4380.23 h25
  text "NC_DRILL FILES" at 13094.46,4275.04 h25
  text "REFERENCE:" at 11408.23,4271.1 h25
  text "X" at 12065.46,4271.01 h25
  text "AS SHOWN" at 12243.46,4271.1 h25
  text "X" at 12966.46,4271.1 h25
  text "OTHER" at 13392.46,4128.85 h25
  text "PTH COPPER THICKNESS:" at 11407.91,4125.32 h25
  text "X" at 12547.14,4125.32 h25
  text "20-30 um" at 12675.14,4125.32 h25
  text "BOARD FINISH:" at 11333.46,3977.73 h25
  text "SILKSCREEN:" at 11488.68,3867.6 h25
  text "X" at 12446.46,3867.6 h25
  text "TOP" at 12563.46,3867.6 h25
  text "X" at 12956.46,3867.6 h25
  text "BOTTOM" at 13074.46,3867.6 h25
  text "SILKSCREEN COLOR:" at 11488.68,3712.41 h25
  text "X" at 12445.46,3712.41 h25
  text "WHITE" at 12563.46,3712.41 h25
  text "OTHER" at 13074.46,3712.41 h25
  text "X" at 12576.46,3568.96 h25
  text "GREEN" at 12694.46,3568.96 h25
  text "OTHER" at 13312.46,3568.96 h25
  text "SOLDER RESIST COLOR:" at 11488.68,3562.1 h25
  text "X" at 12576.46,3414.71 h25
  text "MATTE" at 12694.46,3414.71 h25
  text "SEMI-GLOSS" at 13312,3414.07 h25
  text "IMMERSION GOLD (ENIG)" at 12394.46,3241.94 h25
  text "ENEPIG" at 13732,3234.72 h25
  text "SURFACE FINISH:" at 11333.46,3233.72 h25
  text "X" at 12216.46,3233.72 h25
  text "IMM. TIN/SILVER OR EQUIV" at 11663,3096.4 h25
  text "OTHER" at 13094.46,3092.47 h25
  text "ARRAY/PANEL:" at 11333.46,2937.09 h25
  text "CUT AND TRIM PER M1 BOARD OUTLINE" at 12394.46,2928.87 h25
  text "N.C. ROUTE" at 12394.46,2792.9 h25
  text "X" at 13082.46,2792.9 h25
  text "V. SCORE" at 13260.46,2792.9 h25
  text "CERTIFICATION:" at 11333.46,2663.77 h25
  text "MATERIALS AND WORKMANSHIP FOR ALL PCBS" at 12058.46,2663.77 h25
  text "TO MEET OR EXCEED THE REQUIREMENTS OF:" at 12058.46,2569.71 h25
  text "X" at 11695.97,2441.08 h25
  text "ANSI IPC-A-600F CLASS ->" at 11823.96,2441.08 h25
  text "X" at 13471.97,2441.08 h25
  text "2" at 13581.96,2441.08 h25
  text "1" at 13266.96,2439.58 h25
  text "3" at 13935.96,2439.58 h25
  text "X" at 12507.97,2293.39 h25
  text "RoHS" at 12635.96,2293.39 h25
  text "OTHER" at 13280.36,2293.39 h25
  text "PER ORDER" at 13677.42,2293.39 h25
  text "ALL BOARDS MUST MEET OR EXCEED UL94-V0 REQUIREMENTS." at 11361,2139.57 h25
  text "PCB MUST BEAR THE UL94V-0 UL REGISTERED MATERIAL ID NUMBER" at 11361,2023.5 h25
  text "ADDITIONAL REQUIREMENTS:" at 11333.46,1854.08 h25
  text "MICROSECTION:" at 11408.23,1746.95 h25
  text "YES" at 12313.96,1746.95 h25
  text "REQUIRED" at 13175.46,1602.62 h25
  text "BARE BOARD ELEC. TEST:" at 11408.23,1599.76 h25
  text "NONE" at 12713.96,1599.76 h25
  text "X" at 13057.46,1599.76 h25
  text "PER ORDER" at 13767.46,1599.76 h25
  text "XX MIL VIAS REQUIRE NON-CONDUCTIVE FILL AND PLANARIZE" at 11576.38,1394.82 h25
  text "XX MIL VIAS REQUIRE CONDUCTIVE FILL AND PLANARIZE" at 11584.38,1290.84 h25
  text "OUTER XX MIL TRACES REQUIRE 50 OHM SINGLE-ENDED IMPEDANCE" at 11583.39,1127.46 h25
  text "LAYER 2 & 3 (INNER LAYERS) XX MIL WIDE, XX MIL SPACE / TRACES REQUIRE 100 OHM DIFFERENTIAL IMPEDANCE" at 11575.39,891.74 h25
  text ".Layer_Name" at 577,-858.49 h25
M11 Gerber Information:
  lines w10: -292,-930.17 6308,-930.17 ; -292,-726.83 6310,-726.83 ; -292,-523.5 -292,-1133.5 3713,-1133.5 6310,-1133.5 6310,-523.5 -291.5,-523.5 -291.5,-1133.5 1284,-1133.5 ; 2173,-1133.5 2173,-523.5 ; 3440,-726.83 3440,-523.5 ; 4280,-726.83 4280,-523.5 ; 4902,-1140 4902,-937.17
  text "ALL ARTWORK VIEWED FROM TOP SIDE" at -228.5,-655.67 h25
  text "BOARD #:" at 2248,-655.67 h25
  text ".PRJ_Number" at 2793.5,-655.67 h25
  text "REV:" at 3638,-655.67 h25
  text ".PCB_Rev" at 3929.5,-655.67 h25
  text "SVN REV:" at 4476,-655.67 h25
  text ".VersionControl_RevNumber" at 4982,-655.67 h25
  text "LAYER NAME =" at -228.5,-858.49 h25
  text "TID #:" at 2248,-859 h25
  text ".TID" at 2793.5,-859 h25
  text "PLOT NAME =" at -228.5,-1064.34 h25
  text ".plot_File_Name" at 577,-1064.34 h25
  text "GENERATED    :" at 2250,-1064.34 h25
  text ".Print_Date" at 3119.5,-1064.34 h25
  text ".Print_Time" at 3848.5,-1064.34 h25
  text "TEXAS INSTRUMENTS" at 5113,-1064.34 h25
M12 Stackup:
  drawing of 295 lines, arcs and shapes, not listed
  text "Layer" at 5769.38,1029.55 h60
  text "Name" at 6179.29,1029.55 h60
  text "Material" at 7119.03,1029.55 h60
  text "Thickness" at 7978.8,1029.55 h60
  text "Constant" at 8628.63,1029.55 h60
  text "Board Layer Stack" at 9198.5,1029.55 h60
  text "Top Overlay" at 6179.29,909.55 h60
  text "Top Solder" at 6179.29,789.55 h60
  text "Solder Resist" at 7119.03,789.55 h60
  text "0.40mil" at 7978.8,789.55 h60
  text "3.5" at 8628.63,789.55 h60
  text "1" at 5769.38,669.55 h60
  text "Top Layer" at 6179.29,669.55 h60
  text "2.80mil" at 7978.8,669.55 h60
  text "Dielectric 1" at 6179.29,549.55 h60
  text "FR4 370" at 7119.03,549.55 h60
  text "11.40mil" at 7978.8,549.55 h60
  text "4.2" at 8628.63,549.55 h60
  text "2" at 5769.38,429.55 h60
  text "Signal Layer 1" at 6179.29,429.55 h60
  text "1.40mil" at 7978.8,429.55 h60
  text "Dielectric 2" at 6179.29,309.55 h60
  text "FR4 370" at 7119.03,309.55 h60
  text "30.00mil" at 7978.8,309.55 h60
  text "4.2" at 8628.63,309.55 h60
  text "3" at 5769.38,189.55 h60
  text "Signal Layer 2" at 6179.29,189.55 h60
  text "1.40mil" at 7978.8,189.55 h60
  text "Dielectric 3" at 6179.29,69.55 h60
  text "FR4 370" at 7119.03,69.55 h60
  text "11.40mil" at 7978.8,69.55 h60
  text "4.2" at 8628.63,69.55 h60
  text "4" at 5769.38,-50.45 h60
  text "Bottom Layer" at 6179.29,-50.45 h60
  text "2.80mil" at 7978.8,-50.45 h60
  text "Bottom Solder" at 6179.29,-170.45 h60
  text "Solder Resist" at 7119.03,-170.45 h60
  text "0.40mil" at 7978.8,-170.45 h60
  text "3.5" at 8628.63,-170.45 h60
  text "Bottom Overlay" at 6179.29,-290.45 h60
  text ".Layer_Name" at 577,-858.49 h25
M13 Component Bodies Top:
  text ".Layer_Name" at 577,-858.49 h25
M14 Component Bodies Bottom:
  text ".Layer_Name" at 577,-858.49 h25
M15 Courtyards Top:
  text ".Layer_Name" at 577,-858.49 h25
M16 Courtyards Bottom:
  text ".Layer_Name" at 577,-858.49 h25
Drill Drawing:
  circle w10: c134.98,7580.15 r20
  circle w10: c134.98,7580.15 r33.33
  circle w10: c134.98,6380.15 r33.33
  lines w10: 101.65,5746.82 101.65,5763.49 118.32,5780.15 101.65,5796.82 101.65,5813.48 118.32,5813.48 134.98,5796.82 151.65,5813.48 168.32,5813.48 168.32,5796.82 151.65,5780.15 168.32,5763.49 168.32,5746.82 151.65,5746.82 134.98,5763.49 118.32,5746.82 101.65,5746.82 ; 101.65,5913.49 118.32,5913.49 134.98,5896.82 151.65,5913.49 168.32,5913.49 151.65,5930.15 168.32,5946.82 151.65,5946.82 134.98,5963.48 118.32,5946.82 101.65,5946.82 118.32,5930.15 101.65,5913.49 ; 101.65,6046.82 134.98,6063.49 168.32,6046.82 151.65,6080.15 168.32,6113.48 134.98,6096.82 101.65,6113.48 118.32,6080.15 101.65,6046.82 ; 101.65,6213.49 118.32,6213.49 118.32,6196.82 151.65,6196.82 151.65,6213.49 168.32,6213.49 168.32,6246.82 151.65,6246.82 151.65,6263.48 118.32,6263.48 118.32,6246.82 101.65,6246.82 101.65,6213.49 ; 101.65,6563.48 168.32,6563.48 134.98,6496.82 101.65,6563.48 ; 101.65,6713.49 168.32,6713.49 134.98,6646.82 101.65,6713.49 ; 101.65,6813.49 118.32,6813.49 134.98,6796.82 151.65,6813.49 168.32,6813.49 151.65,6830.15 168.32,6846.82 151.65,6846.82 134.98,6863.49 118.32,6846.82 101.65,6846.82 118.32,6830.15 101.65,6813.49 ; 101.65,6980.15 134.98,6946.82 168.32,6980.15 134.98,7013.49 101.65,6980.15 ; 101.65,7113.49 118.32,7113.49 118.32,7096.82 151.65,7096.82 151.65,7113.49 168.32,7113.49 168.32,7146.82 151.65,7146.82 151.65,7163.49 118.32,7163.49 118.32,7146.82 101.65,7146.82 101.65,7113.49 ; 101.65,7246.82 168.32,7246.82 168.32,7313.49 101.65,7313.49 101.65,7246.82 ; 101.65,7396.82 168.32,7396.82 168.32,7463.49 101.65,7463.49 101.65,7396.82 ; 114.98,6550.15 154.98,6550.15 134.98,6510.15 114.98,6550.15 ; 114.98,6820.15 124.98,6820.15 134.98,6810.15 144.98,6820.15 154.98,6820.15 144.98,6830.15 154.98,6840.15 144.98,6840.15 134.98,6850.15 124.98,6840.15 114.98,6840.15 124.98,6830.15 114.98,6820.15 ; 114.98,7120.15 124.98,7120.15 124.98,7110.15 144.98,7110.15 144.98,7120.15 154.98,7120.15 154.98,7140.15 144.98,7140.15 144.98,7150.15 124.98,7150.15 124.98,7140.15 114.98,7140.15 114.98,7120.15 ; 114.98,7260.15 154.98,7260.15 154.98,7300.15 114.98,7300.15 114.98,7260.15
  lines w12: 41.86,5701.82 6442.09,5701.82 ; 41.86,7651.82 6442.09,7651.82 ; 592.73,5551.82 592.73,7801.82 ; 1230.57,5551.82 1230.57,7801.82 ; 2576.17,5551.82 2576.17,7801.82 ; 3082.05,5551.82 3082.05,7801.82 ; 3815.85,5551.82 3815.85,7801.82 ; 5315.4,5551.82 5315.4,7801.82 ; 41.86,5551.82 6442.09,5551.82 6442.09,7801.82 41.86,7801.82 41.86,5551.82
  text "Symbol" at 131.86,7696.82 h72
  text "Quantity" at 637.73,7696.82 h72
  text "Finished Hole Size" at 1275.57,7696.82 h72
  text "Plated" at 2621.17,7696.82 h72
  text "Hole Type" at 3127.05,7696.82 h72
  text "Drill Layer Pair" at 3860.85,7696.82 h72
  text "Hole Tolerance" at 5360.4,7696.82 h72
  text "39" at 637.73,7546.82 h60
  text "7.87mil (0.200mm)" at 1275.57,7546.82 h60
  text "PTH" at 2621.17,7546.82 h60
  text "Round" at 3127.05,7546.82 h60
  text "Top Layer - Bottom Layer" at 3860.85,7546.82 h60
  text "714" at 637.73,7396.82 h60
  text "13.78mil (0.350mm)" at 1275.57,7396.82 h60
  text "PTH" at 2621.17,7396.82 h60
  text "Round" at 3127.05,7396.82 h60
  text "Top Layer - Bottom Layer" at 3860.85,7396.82 h60
  text "1" at 637.73,7246.82 h60
  text "17.72mil (0.450mm)" at 1275.57,7246.82 h60
  text "PTH" at 2621.17,7246.82 h60
  text "Round" at 3127.05,7246.82 h60
  text "Top Layer - Bottom Layer" at 3860.85,7246.82 h60
  text "8" at 637.73,7096.82 h60
  text "35.43mil (0.900mm)" at 1275.57,7096.82 h60
  text "PTH" at 2621.17,7096.82 h60
  text "Round" at 3127.05,7096.82 h60
  text "Top Layer - Bottom Layer" at 3860.85,7096.82 h60
  text "14" at 637.73,6946.82 h60
  text "40.00mil (1.016mm)" at 1275.57,6946.82 h60
  text "PTH" at 2621.17,6946.82 h60
  text "Round" at 3127.05,6946.82 h60
  text "Top Layer - Bottom Layer" at 3860.85,6946.82 h60
  text "24" at 637.73,6796.82 h60
  text "40.16mil (1.020mm)" at 1275.57,6796.82 h60
  text "PTH" at 2621.17,6796.82 h60
  text "Round" at 3127.05,6796.82 h60
  text "Top Layer - Bottom Layer" at 3860.85,6796.82 h60
  text "+/-3.15mil" at 5360.4,6796.82 h60
  text "6" at 637.73,6646.82 h60
  text "40.16mil (1.020mm)" at 1275.57,6646.82 h60
  text "PTH" at 2621.17,6646.82 h60
  text "Round" at 3127.05,6646.82 h60
  text "Top Layer - Bottom Layer" at 3860.85,6646.82 h60
  text "14" at 637.73,6496.82 h60
  text "43.31mil (1.100mm)" at 1275.57,6496.82 h60
  text "PTH" at 2621.17,6496.82 h60
  text "Round" at 3127.05,6496.82 h60
  text "Top Layer - Bottom Layer" at 3860.85,6496.82 h60
  text "+/-1.97mil" at 5360.4,6496.82 h60
  text "4" at 637.73,6346.82 h60
  text "51.18mil (1.300mm)" at 1275.57,6346.82 h60
  text "PTH" at 2621.17,6346.82 h60
  text "Round" at 3127.05,6346.82 h60
  text "Top Layer - Bottom Layer" at 3860.85,6346.82 h60
  text "16" at 637.73,6196.82 h60
  text "62.99mil (1.600mm)" at 1275.57,6196.82 h60
  text "PTH" at 2621.17,6196.82 h60
  text "Round" at 3127.05,6196.82 h60
  text "Top Layer - Bottom Layer" at 3860.85,6196.82 h60
  text "+3.94mil/-0.00mil" at 5360.4,6196.82 h60
  text "4" at 637.73,6046.82 h60
  text "62.99mil (1.600mm)" at 1275.57,6046.82 h60
  text "PTH" at 2621.17,6046.82 h60
  text "Round" at 3127.05,6046.82 h60
  text "Top Layer - Bottom Layer" at 3860.85,6046.82 h60
  text "12" at 637.73,5896.82 h60
  text "63.00mil (1.600mm)" at 1275.57,5896.82 h60
  text "PTH" at 2621.17,5896.82 h60
  text "Round" at 3127.05,5896.82 h60
  text "Top Layer - Bottom Layer" at 3860.85,5896.82 h60
  text "2" at 637.73,5746.82 h60
  text "23.62mil (0.600mm)" at 1275.57,5746.82 h60
  text "PTH" at 2621.17,5746.82 h60
  text "Slot" at 3127.05,5746.82 h60
  text "Top Layer - Bottom Layer" at 3860.85,5746.82 h60
  text "858 Total" at 637.73,5596.82 h60
  text "Slot definitions :" at 131.86,5451.84 h60
  text "Routed Path Length" at 1164.55,5451.84 h60
  text "= Calculated from tool start centre position to tool end centre position." at 2267.21,5451.84 h60
  text "Hole Length" at 1164.55,5351.87 h60
  text "= Routed Path Length + Tool Size = Slot length as defined in the PCB layout" at 1857.35,5351.87 h60
  text ".Layer_Name" at 577,-858.49 h25
Mechanical 17:
  text ".Layer_Name" at 577,-858.49 h25
Mechanical 18:
  text ".Layer_Name" at 577,-858.49 h25
Mechanical 19:
  text ".Layer_Name" at 577,-858.49 h25

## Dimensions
0,-400 to 1000,-400 on M2 Board Dimensions
0,0 to 0,4078.74 on M2 Board Dimensions
0,0 to 3224.41,0 on M2 Board Dimensions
